VERSION 5.8 ;
BUSBITCHARS "[]" ;
DIVIDERCHAR "/" ;

PROPERTYDEFINITIONS
  MACRO CatenaDesignType STRING ;
  MACRO oaTaper STRING ;
END PROPERTYDEFINITIONS

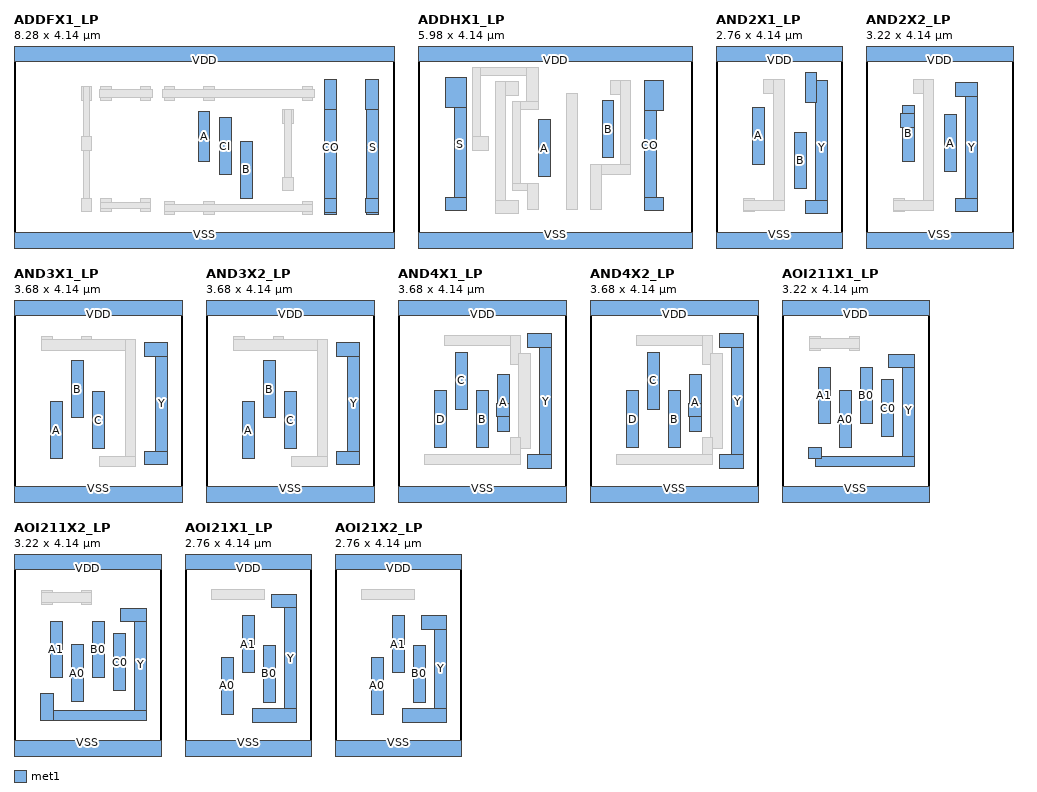
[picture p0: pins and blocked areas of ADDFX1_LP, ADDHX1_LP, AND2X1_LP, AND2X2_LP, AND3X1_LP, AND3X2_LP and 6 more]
MACRO ADDFX1_LP
  CLASS CORE ;
  ORIGIN 0 0 ;
  FOREIGN ADDFX1_LP 0 0 ;
  SIZE 8.28 BY 4.14 ;
  SYMMETRY X Y ;
  SITE CoreSite ;
  PIN A
    DIRECTION INPUT ;
    USE SIGNAL ;
    PORT
      LAYER met1 ;
        RECT 4.01 1.745 4.27 2.85 ;
    END
  END A
  PIN B
    DIRECTION INPUT ;
    USE SIGNAL ;
    PORT
      LAYER met1 ;
        RECT 4.93 0.955 5.19 2.195 ;
    END
  END B
  PIN CI
    DIRECTION INPUT ;
    USE SIGNAL ;
    PORT
      LAYER met1 ;
        RECT 4.47 1.47 4.73 2.71 ;
    END
  END CI
  PIN CO
    DIRECTION OUTPUT ;
    USE SIGNAL ;
    PORT
      LAYER met1 ;
        RECT 6.77 2.88 7.035 3.53 ;
        RECT 6.77 0.65 7.035 0.94 ;
        RECT 6.77 0.61 7.03 3.53 ;
    END
  END CO
  PIN S
    DIRECTION OUTPUT ;
    USE SIGNAL ;
    PORT
      LAYER met1 ;
        RECT 7.665 2.88 7.95 3.53 ;
        RECT 7.69 0.61 7.95 3.53 ;
        RECT 7.665 0.65 7.95 0.94 ;
    END
  END S
  PIN VDD
    DIRECTION INPUT ;
    USE POWER ;
    SHAPE ABUTMENT ;
    NETEXPR "VDD VDD!" ;
    PORT
      LAYER met1 ;
        RECT 0 3.94 8.28 4.34 ;
    END
  END VDD
  PIN VSS
    DIRECTION INPUT ;
    USE GROUND ;
    SHAPE ABUTMENT ;
    NETEXPR "VSS VSS!" ;
    PORT
      LAYER met1 ;
        RECT 0 -0.2 8.28 0.2 ;
    END
  END VSS
  OBS
    LAYER met1 ;
      RECT 6.285 3.09 6.515 3.38 ;
      RECT 4.135 3.09 4.365 3.38 ;
      RECT 3.275 3.09 3.505 3.38 ;
      RECT 3.245 3.15 6.545 3.32 ;
      RECT 6.285 0.6 6.515 0.89 ;
      RECT 4.135 0.6 4.365 0.89 ;
      RECT 3.275 0.6 3.505 0.89 ;
      RECT 3.275 0.675 6.515 0.815 ;
      RECT 5.855 2.59 6.085 2.88 ;
      RECT 5.9 1.125 6.04 2.88 ;
      RECT 5.855 1.125 6.085 1.415 ;
      RECT 2.755 3.09 2.985 3.38 ;
      RECT 1.895 3.09 2.125 3.38 ;
      RECT 1.865 3.15 3.015 3.32 ;
      RECT 2.755 0.655 2.985 0.945 ;
      RECT 1.895 0.655 2.125 0.945 ;
      RECT 1.895 0.73 2.985 0.87 ;
      RECT 1.465 3.09 1.695 3.38 ;
      RECT 1.51 0.655 1.65 3.38 ;
      RECT 1.465 2 1.695 2.29 ;
      RECT 1.465 0.655 1.695 0.945 ;
  END
  PROPERTY CatenaDesignType "deviceLevel" ;
END ADDFX1_LP

MACRO ADDHX1_LP
  CLASS CORE ;
  ORIGIN 0 0 ;
  FOREIGN ADDHX1_LP 0 0 ;
  SIZE 5.98 BY 4.14 ;
  SYMMETRY X Y ;
  SITE CoreSite ;
  PIN A
    DIRECTION INPUT ;
    USE SIGNAL ;
    PORT
      LAYER met1 ;
        RECT 2.63 1.425 2.89 2.665 ;
    END
  END A
  PIN B
    DIRECTION INPUT ;
    USE SIGNAL ;
    PORT
      LAYER met1 ;
        RECT 4.01 1.84 4.27 3.08 ;
    END
  END B
  PIN CO
    DIRECTION OUTPUT ;
    USE SIGNAL ;
    PORT
      LAYER met1 ;
        RECT 4.93 2.875 5.345 3.525 ;
        RECT 4.93 0.68 5.345 0.97 ;
        RECT 4.93 0.68 5.19 3.525 ;
    END
  END CO
  PIN S
    DIRECTION OUTPUT ;
    USE SIGNAL ;
    PORT
      LAYER met1 ;
        RECT 0.605 2.925 1.05 3.575 ;
        RECT 0.79 0.68 1.05 3.575 ;
        RECT 0.605 0.68 1.05 0.97 ;
    END
  END S
  PIN VDD
    DIRECTION INPUT ;
    USE POWER ;
    SHAPE ABUTMENT ;
    NETEXPR "VDD VDD!" ;
    PORT
      LAYER met1 ;
        RECT 0 3.94 5.98 4.34 ;
    END
  END VDD
  PIN VSS
    DIRECTION INPUT ;
    USE GROUND ;
    SHAPE ABUTMENT ;
    NETEXPR "VSS VSS!" ;
    PORT
      LAYER met1 ;
        RECT 0 -0.2 5.98 0.2 ;
    END
  END VSS
  OBS
    LAYER met1 ;
      RECT 4.195 3.22 4.64 3.51 ;
      RECT 4.41 1.46 4.64 3.51 ;
      RECT 3.765 1.46 4.64 1.69 ;
      RECT 3.765 0.705 3.995 1.69 ;
      RECT 1.19 3.63 2.615 3.8 ;
      RECT 2.355 2.89 2.615 3.8 ;
      RECT 1.19 2 1.36 3.8 ;
      RECT 2.065 2.89 2.615 3.06 ;
      RECT 2.065 1.115 2.235 3.06 ;
      RECT 1.19 2 1.54 2.29 ;
      RECT 2.065 1.115 2.615 1.285 ;
      RECT 2.385 0.705 2.615 1.285 ;
      RECT 1.68 3.2 2.185 3.49 ;
      RECT 1.68 0.615 1.91 3.49 ;
      RECT 1.68 0.615 2.185 0.905 ;
      RECT 3.245 0.705 3.475 3.235 ;
  END
  PROPERTY CatenaDesignType "deviceLevel" ;
END ADDHX1_LP

MACRO AND2X1_LP
  CLASS CORE ;
  ORIGIN 0 0 ;
  FOREIGN AND2X1_LP 0 0 ;
  SIZE 2.76 BY 4.14 ;
  SYMMETRY X Y ;
  SITE CoreSite ;
  PIN A
    DIRECTION INPUT ;
    USE SIGNAL ;
    PORT
      LAYER met1 ;
        RECT 0.79 1.695 1.05 2.935 ;
    END
  END A
  PIN B
    DIRECTION INPUT ;
    USE SIGNAL ;
    PORT
      LAYER met1 ;
        RECT 1.71 1.155 1.97 2.395 ;
    END
  END B
  PIN VDD
    DIRECTION INPUT ;
    USE POWER ;
    SHAPE ABUTMENT ;
    NETEXPR "VDD VDD!" ;
    PORT
      LAYER met1 ;
        RECT 0 3.94 2.76 4.34 ;
    END
  END VDD
  PIN VSS
    DIRECTION INPUT ;
    USE GROUND ;
    SHAPE ABUTMENT ;
    NETEXPR "VSS VSS!" ;
    PORT
      LAYER met1 ;
        RECT 0 -0.2 2.76 0.2 ;
    END
  END VSS
  PIN Y
    DIRECTION OUTPUT ;
    USE SIGNAL ;
    PORT
      LAYER met1 ;
        RECT 2.17 0.625 2.43 3.51 ;
        RECT 1.955 3.05 2.185 3.7 ;
        RECT 1.955 0.625 2.43 0.915 ;
    END
  END Y
  OBS
    LAYER met1 ;
      RECT 1.035 3.24 1.49 3.53 ;
      RECT 1.26 0.685 1.49 3.53 ;
      RECT 0.605 0.655 0.835 0.945 ;
      RECT 0.605 0.685 1.49 0.915 ;
  END
  PROPERTY CatenaDesignType "deviceLevel" ;
END AND2X1_LP

MACRO AND2X2_LP
  CLASS CORE ;
  ORIGIN 0 0 ;
  FOREIGN AND2X2_LP 0 0 ;
  SIZE 3.22 BY 4.14 ;
  SYMMETRY X Y ;
  SITE CoreSite ;
  PIN A
    DIRECTION INPUT ;
    USE SIGNAL ;
    PORT
      LAYER met1 ;
        RECT 1.71 1.535 1.97 2.775 ;
    END
  END A
  PIN B
    DIRECTION INPUT ;
    USE SIGNAL ;
    PORT
      LAYER met1 ;
        RECT 0.79 1.745 1.05 2.985 ;
        RECT 0.745 2.505 1.05 2.795 ;
    END
  END B
  PIN VDD
    DIRECTION INPUT ;
    USE POWER ;
    SHAPE ABUTMENT ;
    NETEXPR "VDD VDD!" ;
    PORT
      LAYER met1 ;
        RECT 0 3.94 3.22 4.34 ;
    END
  END VDD
  PIN VSS
    DIRECTION INPUT ;
    USE GROUND ;
    SHAPE ABUTMENT ;
    NETEXPR "VSS VSS!" ;
    PORT
      LAYER met1 ;
        RECT 0 -0.2 3.22 0.2 ;
    END
  END VSS
  PIN Y
    DIRECTION OUTPUT ;
    USE SIGNAL ;
    PORT
      LAYER met1 ;
        RECT 1.955 3.18 2.43 3.47 ;
        RECT 2.17 0.655 2.43 3.47 ;
        RECT 1.955 0.655 2.43 0.945 ;
    END
  END Y
  OBS
    LAYER met1 ;
      RECT 1.035 3.24 1.48 3.53 ;
      RECT 1.25 0.685 1.48 3.53 ;
      RECT 0.605 0.655 0.835 0.945 ;
      RECT 0.605 0.685 1.48 0.915 ;
  END
  PROPERTY CatenaDesignType "deviceLevel" ;
END AND2X2_LP

MACRO AND3X1_LP
  CLASS CORE ;
  ORIGIN 0 0 ;
  FOREIGN AND3X1_LP 0 0 ;
  SIZE 3.68 BY 4.14 ;
  SYMMETRY X Y ;
  SITE CoreSite ;
  PIN A
    DIRECTION INPUT ;
    USE SIGNAL ;
    PORT
      LAYER met1 ;
        RECT 0.79 0.815 1.05 2.055 ;
    END
  END A
  PIN B
    DIRECTION INPUT ;
    USE SIGNAL ;
    PORT
      LAYER met1 ;
        RECT 1.25 1.705 1.51 2.945 ;
    END
  END B
  PIN C
    DIRECTION INPUT ;
    USE SIGNAL ;
    PORT
      LAYER met1 ;
        RECT 1.71 1.03 1.97 2.27 ;
    END
  END C
  PIN VDD
    DIRECTION INPUT ;
    USE POWER ;
    SHAPE ABUTMENT ;
    NETEXPR "VDD VDD!" ;
    PORT
      LAYER met1 ;
        RECT 0 3.94 3.68 4.34 ;
    END
  END VDD
  PIN VSS
    DIRECTION INPUT ;
    USE GROUND ;
    SHAPE ABUTMENT ;
    NETEXPR "VSS VSS!" ;
    PORT
      LAYER met1 ;
        RECT 0 -0.2 3.68 0.2 ;
    END
  END VSS
  PIN Y
    DIRECTION OUTPUT ;
    USE SIGNAL ;
    PORT
      LAYER met1 ;
        RECT 2.845 3.045 3.35 3.335 ;
        RECT 3.09 0.69 3.35 3.335 ;
        RECT 2.845 0.69 3.35 0.98 ;
    END
  END Y
  OBS
    LAYER met1 ;
      RECT 1.465 3.175 1.695 3.465 ;
      RECT 0.605 3.175 0.835 3.465 ;
      RECT 0.605 3.175 2.65 3.405 ;
      RECT 2.42 0.64 2.65 3.405 ;
      RECT 1.865 0.64 2.65 0.87 ;
  END
  PROPERTY CatenaDesignType "deviceLevel" ;
END AND3X1_LP

MACRO AND3X2_LP
  CLASS CORE ;
  ORIGIN 0 0 ;
  FOREIGN AND3X2_LP 0 0 ;
  SIZE 3.68 BY 4.14 ;
  SYMMETRY X Y ;
  SITE CoreSite ;
  PIN A
    DIRECTION INPUT ;
    USE SIGNAL ;
    PORT
      LAYER met1 ;
        RECT 0.79 0.815 1.05 2.055 ;
    END
  END A
  PIN B
    DIRECTION INPUT ;
    USE SIGNAL ;
    PORT
      LAYER met1 ;
        RECT 1.25 1.705 1.51 2.945 ;
    END
  END B
  PIN C
    DIRECTION INPUT ;
    USE SIGNAL ;
    PORT
      LAYER met1 ;
        RECT 1.71 1.03 1.97 2.27 ;
    END
  END C
  PIN VDD
    DIRECTION INPUT ;
    USE POWER ;
    SHAPE ABUTMENT ;
    NETEXPR "VDD VDD!" ;
    PORT
      LAYER met1 ;
        RECT 0 3.94 3.68 4.34 ;
    END
  END VDD
  PIN VSS
    DIRECTION INPUT ;
    USE GROUND ;
    SHAPE ABUTMENT ;
    NETEXPR "VSS VSS!" ;
    PORT
      LAYER met1 ;
        RECT 0 -0.2 3.68 0.2 ;
    END
  END VSS
  PIN Y
    DIRECTION OUTPUT ;
    USE SIGNAL ;
    PORT
      LAYER met1 ;
        RECT 2.845 3.045 3.35 3.335 ;
        RECT 3.09 0.69 3.35 3.335 ;
        RECT 2.845 0.69 3.35 0.98 ;
    END
  END Y
  OBS
    LAYER met1 ;
      RECT 1.465 3.175 1.695 3.465 ;
      RECT 0.605 3.175 0.835 3.465 ;
      RECT 0.605 3.175 2.65 3.405 ;
      RECT 2.42 0.64 2.65 3.405 ;
      RECT 1.865 0.64 2.65 0.87 ;
  END
  PROPERTY CatenaDesignType "deviceLevel" ;
END AND3X2_LP

MACRO AND4X1_LP
  CLASS CORE ;
  ORIGIN 0 0 ;
  FOREIGN AND4X1_LP 0 0 ;
  SIZE 3.68 BY 4.14 ;
  SYMMETRY X Y ;
  SITE CoreSite ;
  PIN A
    DIRECTION INPUT ;
    USE SIGNAL ;
    PORT
      LAYER met1 ;
        RECT 2.17 1.41 2.43 2.65 ;
        RECT 2.14 1.73 2.43 2.02 ;
    END
  END A
  PIN B
    DIRECTION INPUT ;
    USE SIGNAL ;
    PORT
      LAYER met1 ;
        RECT 1.71 1.055 1.97 2.295 ;
    END
  END B
  PIN C
    DIRECTION INPUT ;
    USE SIGNAL ;
    PORT
      LAYER met1 ;
        RECT 1.25 1.89 1.51 3.13 ;
    END
  END C
  PIN D
    DIRECTION INPUT ;
    USE SIGNAL ;
    PORT
      LAYER met1 ;
        RECT 0.79 1.055 1.05 2.295 ;
    END
  END D
  PIN VDD
    DIRECTION INPUT ;
    USE POWER ;
    SHAPE ABUTMENT ;
    NETEXPR "VDD VDD!" ;
    PORT
      LAYER met1 ;
        RECT 0 3.94 3.68 4.34 ;
    END
  END VDD
  PIN VSS
    DIRECTION INPUT ;
    USE GROUND ;
    SHAPE ABUTMENT ;
    NETEXPR "VSS VSS!" ;
    PORT
      LAYER met1 ;
        RECT 0 -0.2 3.68 0.2 ;
    END
  END VSS
  PIN Y
    DIRECTION OUTPUT ;
    USE SIGNAL ;
    PORT
      LAYER met1 ;
        RECT 2.815 3.24 3.35 3.53 ;
        RECT 3.09 0.61 3.35 3.53 ;
        RECT 2.815 0.61 3.35 0.9 ;
    END
  END Y
  OBS
    LAYER met1 ;
      RECT 1.005 3.27 2.675 3.5 ;
      RECT 2.445 2.87 2.675 3.5 ;
      RECT 2.63 1.04 2.89 3.1 ;
      RECT 2.445 0.685 2.675 1.27 ;
      RECT 0.575 0.685 2.675 0.915 ;
  END
  PROPERTY CatenaDesignType "deviceLevel" ;
END AND4X1_LP

MACRO AND4X2_LP
  CLASS CORE ;
  ORIGIN 0 0 ;
  FOREIGN AND4X2_LP 0 0 ;
  SIZE 3.68 BY 4.14 ;
  SYMMETRY X Y ;
  SITE CoreSite ;
  PIN A
    DIRECTION INPUT ;
    USE SIGNAL ;
    PORT
      LAYER met1 ;
        RECT 2.17 1.41 2.43 2.65 ;
        RECT 2.14 1.73 2.43 2.02 ;
    END
  END A
  PIN B
    DIRECTION INPUT ;
    USE SIGNAL ;
    PORT
      LAYER met1 ;
        RECT 1.71 1.055 1.97 2.295 ;
    END
  END B
  PIN C
    DIRECTION INPUT ;
    USE SIGNAL ;
    PORT
      LAYER met1 ;
        RECT 1.25 1.89 1.51 3.13 ;
    END
  END C
  PIN D
    DIRECTION INPUT ;
    USE SIGNAL ;
    PORT
      LAYER met1 ;
        RECT 0.79 1.055 1.05 2.295 ;
    END
  END D
  PIN VDD
    DIRECTION INPUT ;
    USE POWER ;
    SHAPE ABUTMENT ;
    NETEXPR "VDD VDD!" ;
    PORT
      LAYER met1 ;
        RECT 0 3.94 3.68 4.34 ;
    END
  END VDD
  PIN VSS
    DIRECTION INPUT ;
    USE GROUND ;
    SHAPE ABUTMENT ;
    NETEXPR "VSS VSS!" ;
    PORT
      LAYER met1 ;
        RECT 0 -0.2 3.68 0.2 ;
    END
  END VSS
  PIN Y
    DIRECTION OUTPUT ;
    USE SIGNAL ;
    PORT
      LAYER met1 ;
        RECT 2.815 3.24 3.35 3.53 ;
        RECT 3.09 0.61 3.35 3.53 ;
        RECT 2.815 0.61 3.35 0.9 ;
    END
  END Y
  OBS
    LAYER met1 ;
      RECT 1.005 3.27 2.675 3.5 ;
      RECT 2.445 2.87 2.675 3.5 ;
      RECT 2.63 1.04 2.89 3.1 ;
      RECT 2.445 0.685 2.675 1.27 ;
      RECT 0.575 0.685 2.675 0.915 ;
  END
  PROPERTY CatenaDesignType "deviceLevel" ;
END AND4X2_LP

MACRO AOI211X1_LP
  CLASS CORE ;
  ORIGIN 0 0 ;
  FOREIGN AOI211X1_LP 0 0 ;
  SIZE 3.22 BY 4.14 ;
  SYMMETRY X Y ;
  SITE CoreSite ;
  PIN A0
    DIRECTION INPUT ;
    USE SIGNAL ;
    PORT
      LAYER met1 ;
        RECT 1.25 1.05 1.51 2.29 ;
    END
  END A0
  PIN A1
    DIRECTION INPUT ;
    USE SIGNAL ;
    PORT
      LAYER met1 ;
        RECT 0.79 1.57 1.05 2.81 ;
    END
  END A1
  PIN B0
    DIRECTION INPUT ;
    USE SIGNAL ;
    PORT
      LAYER met1 ;
        RECT 1.71 1.57 1.97 2.81 ;
    END
  END B0
  PIN C0
    DIRECTION INPUT ;
    USE SIGNAL ;
    PORT
      LAYER met1 ;
        RECT 2.17 1.29 2.43 2.53 ;
    END
  END C0
  PIN VDD
    DIRECTION INPUT ;
    USE POWER ;
    SHAPE ABUTMENT ;
    NETEXPR "VDD VDD!" ;
    PORT
      LAYER met1 ;
        RECT 0 3.94 3.22 4.34 ;
    END
  END VDD
  PIN VSS
    DIRECTION INPUT ;
    USE GROUND ;
    SHAPE ABUTMENT ;
    NETEXPR "VSS VSS!" ;
    PORT
      LAYER met1 ;
        RECT 0 -0.2 3.22 0.2 ;
    END
  END VSS
  PIN Y
    DIRECTION OUTPUT ;
    USE SIGNAL ;
    PORT
      LAYER met1 ;
        RECT 2.33 2.79 2.89 3.08 ;
        RECT 2.63 0.64 2.89 3.08 ;
        RECT 0.72 0.64 2.89 0.87 ;
        RECT 0.575 0.82 0.865 1.05 ;
    END
  END Y
  OBS
    LAYER met1 ;
      RECT 1.465 3.18 1.695 3.47 ;
      RECT 0.605 3.18 0.835 3.47 ;
      RECT 0.605 3.21 1.695 3.44 ;
  END
  PROPERTY CatenaDesignType "deviceLevel" ;
END AOI211X1_LP

MACRO AOI211X2_LP
  CLASS CORE ;
  ORIGIN 0 0 ;
  FOREIGN AOI211X2_LP 0 0 ;
  SIZE 3.22 BY 4.14 ;
  SYMMETRY X Y ;
  SITE CoreSite ;
  PIN A0
    DIRECTION INPUT ;
    USE SIGNAL ;
    PORT
      LAYER met1 ;
        RECT 1.25 1.05 1.51 2.29 ;
    END
  END A0
  PIN A1
    DIRECTION INPUT ;
    USE SIGNAL ;
    PORT
      LAYER met1 ;
        RECT 0.79 1.57 1.05 2.81 ;
    END
  END A1
  PIN B0
    DIRECTION INPUT ;
    USE SIGNAL ;
    PORT
      LAYER met1 ;
        RECT 1.71 1.57 1.97 2.81 ;
    END
  END B0
  PIN C0
    DIRECTION INPUT ;
    USE SIGNAL ;
    PORT
      LAYER met1 ;
        RECT 2.17 1.29 2.43 2.53 ;
    END
  END C0
  PIN VDD
    DIRECTION INPUT ;
    USE POWER ;
    SHAPE ABUTMENT ;
    NETEXPR "VDD VDD!" ;
    PORT
      LAYER met1 ;
        RECT 0 3.94 3.22 4.34 ;
    END
  END VDD
  PIN VSS
    DIRECTION INPUT ;
    USE GROUND ;
    SHAPE ABUTMENT ;
    NETEXPR "VSS VSS!" ;
    PORT
      LAYER met1 ;
        RECT 0 -0.2 3.22 0.2 ;
    END
  END VSS
  PIN Y
    DIRECTION OUTPUT ;
    USE SIGNAL ;
    PORT
      LAYER met1 ;
        RECT 2.33 2.79 2.89 3.08 ;
        RECT 2.63 0.64 2.89 3.08 ;
        RECT 0.575 0.64 2.89 0.87 ;
        RECT 0.575 0.64 0.865 1.23 ;
    END
  END Y
  OBS
    LAYER met1 ;
      RECT 1.465 3.18 1.695 3.47 ;
      RECT 0.605 3.18 0.835 3.47 ;
      RECT 0.605 3.21 1.695 3.44 ;
  END
  PROPERTY CatenaDesignType "deviceLevel" ;
END AOI211X2_LP

MACRO AOI21X1_LP
  CLASS CORE ;
  ORIGIN 0 0 ;
  FOREIGN AOI21X1_LP 0 0 ;
  SIZE 2.76 BY 4.14 ;
  SYMMETRY X Y ;
  SITE CoreSite ;
  PIN A0
    DIRECTION INPUT ;
    USE SIGNAL ;
    PORT
      LAYER met1 ;
        RECT 0.79 0.775 1.05 2.015 ;
    END
  END A0
  PIN A1
    DIRECTION INPUT ;
    USE SIGNAL ;
    PORT
      LAYER met1 ;
        RECT 1.25 1.685 1.51 2.925 ;
    END
  END A1
  PIN B0
    DIRECTION INPUT ;
    USE SIGNAL ;
    PORT
      LAYER met1 ;
        RECT 1.71 1.04 1.97 2.28 ;
    END
  END B0
  PIN VDD
    DIRECTION INPUT ;
    USE POWER ;
    SHAPE ABUTMENT ;
    NETEXPR "VDD VDD!" ;
    PORT
      LAYER met1 ;
        RECT 0 3.94 2.76 4.34 ;
    END
  END VDD
  PIN VSS
    DIRECTION INPUT ;
    USE GROUND ;
    SHAPE ABUTMENT ;
    NETEXPR "VSS VSS!" ;
    PORT
      LAYER met1 ;
        RECT 0 -0.2 2.76 0.2 ;
    END
  END VSS
  PIN Y
    DIRECTION OUTPUT ;
    USE SIGNAL ;
    PORT
      LAYER met1 ;
        RECT 1.895 3.095 2.43 3.385 ;
        RECT 2.17 0.61 2.43 3.385 ;
        RECT 1.465 0.61 2.43 0.9 ;
    END
  END Y
  OBS
    LAYER met1 ;
      RECT 0.575 3.27 1.725 3.5 ;
  END
  PROPERTY CatenaDesignType "deviceLevel" ;
END AOI21X1_LP

MACRO AOI21X2_LP
  CLASS CORE ;
  ORIGIN 0 0 ;
  FOREIGN AOI21X2_LP 0 0 ;
  SIZE 2.76 BY 4.14 ;
  SYMMETRY X Y ;
  SITE CoreSite ;
  PIN A0
    DIRECTION INPUT ;
    USE SIGNAL ;
    PORT
      LAYER met1 ;
        RECT 0.79 0.775 1.05 2.015 ;
    END
  END A0
  PIN A1
    DIRECTION INPUT ;
    USE SIGNAL ;
    PORT
      LAYER met1 ;
        RECT 1.25 1.685 1.51 2.925 ;
    END
  END A1
  PIN B0
    DIRECTION INPUT ;
    USE SIGNAL ;
    PORT
      LAYER met1 ;
        RECT 1.71 1.04 1.97 2.28 ;
    END
  END B0
  PIN VDD
    DIRECTION INPUT ;
    USE POWER ;
    SHAPE ABUTMENT ;
    NETEXPR "VDD VDD!" ;
    PORT
      LAYER met1 ;
        RECT 0 3.94 2.76 4.34 ;
    END
  END VDD
  PIN VSS
    DIRECTION INPUT ;
    USE GROUND ;
    SHAPE ABUTMENT ;
    NETEXPR "VSS VSS!" ;
    PORT
      LAYER met1 ;
        RECT 0 -0.2 2.76 0.2 ;
    END
  END VSS
  PIN Y
    DIRECTION OUTPUT ;
    USE SIGNAL ;
    PORT
      LAYER met1 ;
        RECT 1.895 2.635 2.43 2.925 ;
        RECT 2.17 0.61 2.43 2.925 ;
        RECT 1.465 0.61 2.43 0.9 ;
    END
  END Y
  OBS
    LAYER met1 ;
      RECT 0.575 3.27 1.725 3.5 ;
  END
  PROPERTY CatenaDesignType "deviceLevel" ;
END AOI21X2_LP

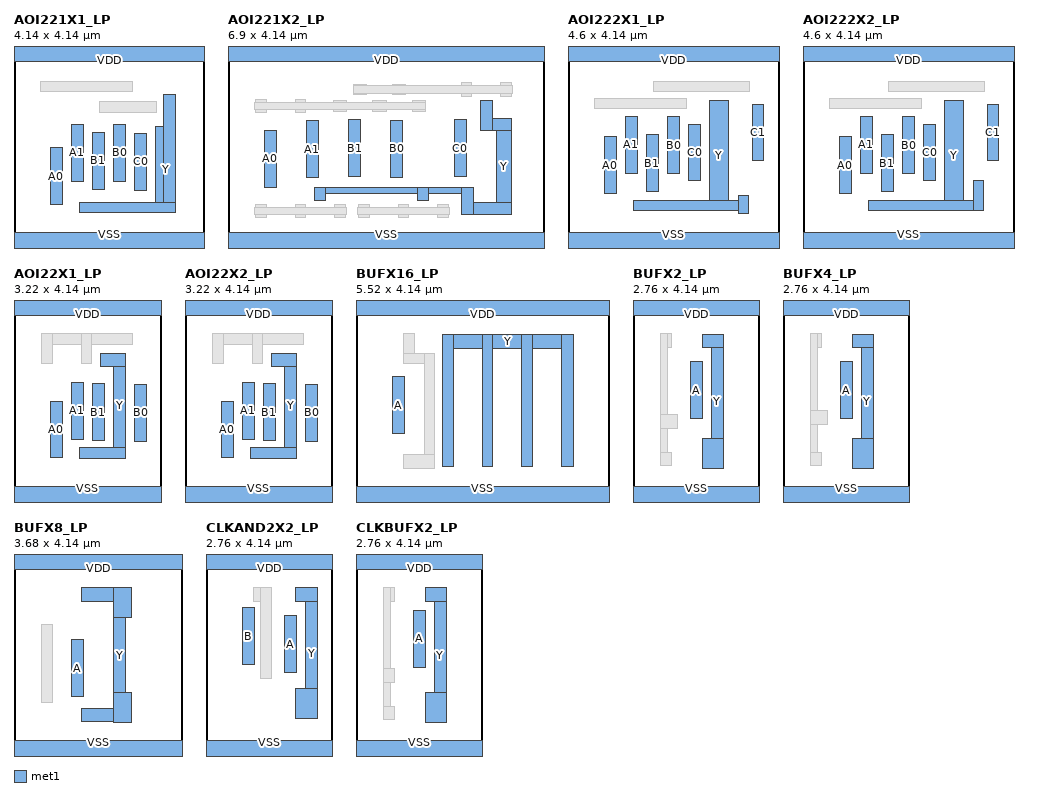
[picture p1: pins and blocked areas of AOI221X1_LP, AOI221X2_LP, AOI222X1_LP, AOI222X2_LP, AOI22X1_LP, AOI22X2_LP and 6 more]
MACRO AOI221X1_LP
  CLASS CORE ;
  ORIGIN 0 0 ;
  FOREIGN AOI221X1_LP 0 0 ;
  SIZE 4.14 BY 4.14 ;
  SYMMETRY X Y ;
  SITE CoreSite ;
  PIN A0
    DIRECTION INPUT ;
    USE SIGNAL ;
    PORT
      LAYER met1 ;
        RECT 0.79 0.81 1.05 2.05 ;
    END
  END A0
  PIN A1
    DIRECTION INPUT ;
    USE SIGNAL ;
    PORT
      LAYER met1 ;
        RECT 1.25 1.325 1.51 2.565 ;
    END
  END A1
  PIN B0
    DIRECTION INPUT ;
    USE SIGNAL ;
    PORT
      LAYER met1 ;
        RECT 2.17 1.325 2.43 2.565 ;
    END
  END B0
  PIN B1
    DIRECTION INPUT ;
    USE SIGNAL ;
    PORT
      LAYER met1 ;
        RECT 1.71 1.15 1.97 2.39 ;
    END
  END B1
  PIN C0
    DIRECTION INPUT ;
    USE SIGNAL ;
    PORT
      LAYER met1 ;
        RECT 2.63 1.13 2.89 2.37 ;
    END
  END C0
  PIN VDD
    DIRECTION INPUT ;
    USE POWER ;
    SHAPE ABUTMENT ;
    NETEXPR "VDD VDD!" ;
    PORT
      LAYER met1 ;
        RECT 0 3.94 4.14 4.34 ;
    END
  END VDD
  PIN VSS
    DIRECTION INPUT ;
    USE GROUND ;
    SHAPE ABUTMENT ;
    NETEXPR "VSS VSS!" ;
    PORT
      LAYER met1 ;
        RECT 0 -0.2 4.14 0.2 ;
    END
  END VSS
  PIN Y
    DIRECTION OUTPUT ;
    USE SIGNAL ;
    PORT
      LAYER met1 ;
        RECT 3.26 0.64 3.52 3.215 ;
        RECT 3.09 0.64 3.52 2.525 ;
        RECT 1.435 0.64 3.52 0.87 ;
    END
  END Y
  OBS
    LAYER met1 ;
      RECT 1.865 2.83 3.105 3.06 ;
      RECT 0.575 3.27 2.585 3.5 ;
  END
  PROPERTY CatenaDesignType "deviceLevel" ;
END AOI221X1_LP

MACRO AOI221X2_LP
  CLASS CORE ;
  ORIGIN 0 0 ;
  FOREIGN AOI221X2_LP 0 0 ;
  SIZE 6.9 BY 4.14 ;
  SYMMETRY X Y ;
  SITE CoreSite ;
  PIN A0
    DIRECTION INPUT ;
    USE SIGNAL ;
    PORT
      LAYER met1 ;
        RECT 0.79 1.19 1.05 2.43 ;
    END
  END A0
  PIN A1
    DIRECTION INPUT ;
    USE SIGNAL ;
    PORT
      LAYER met1 ;
        RECT 1.71 1.4 1.97 2.64 ;
    END
  END A1
  PIN B0
    DIRECTION INPUT ;
    USE SIGNAL ;
    PORT
      LAYER met1 ;
        RECT 3.55 1.415 3.81 2.655 ;
    END
  END B0
  PIN B1
    DIRECTION INPUT ;
    USE SIGNAL ;
    PORT
      LAYER met1 ;
        RECT 2.63 1.42 2.89 2.66 ;
    END
  END B1
  PIN C0
    DIRECTION INPUT ;
    USE SIGNAL ;
    PORT
      LAYER met1 ;
        RECT 4.93 1.425 5.19 2.665 ;
    END
  END C0
  PIN VDD
    DIRECTION INPUT ;
    USE POWER ;
    SHAPE ABUTMENT ;
    NETEXPR "VDD VDD!" ;
    PORT
      LAYER met1 ;
        RECT 0 3.94 6.9 4.34 ;
    END
  END VDD
  PIN VSS
    DIRECTION INPUT ;
    USE GROUND ;
    SHAPE ABUTMENT ;
    NETEXPR "VSS VSS!" ;
    PORT
      LAYER met1 ;
        RECT 0 -0.2 6.9 0.2 ;
    END
  END VSS
  PIN Y
    DIRECTION OUTPUT ;
    USE SIGNAL ;
    PORT
      LAYER met1 ;
        RECT 5.51 2.43 6.175 2.69 ;
        RECT 5.85 0.59 6.175 2.69 ;
        RECT 5.08 0.59 6.175 0.85 ;
        RECT 5.51 2.43 5.77 3.08 ;
        RECT 1.895 1.05 5.34 1.19 ;
        RECT 5.08 0.59 5.34 1.19 ;
        RECT 4.135 0.9 4.365 1.19 ;
        RECT 1.895 0.9 2.125 1.19 ;
    END
  END Y
  OBS
    LAYER met1 ;
      RECT 5.945 3.18 6.175 3.47 ;
      RECT 5.085 3.18 5.315 3.47 ;
      RECT 3.585 3.21 3.875 3.44 ;
      RECT 2.725 3.21 3.015 3.44 ;
      RECT 2.725 3.24 6.205 3.41 ;
      RECT 4.565 0.53 4.795 0.82 ;
      RECT 3.705 0.53 3.935 0.82 ;
      RECT 2.845 0.53 3.075 0.82 ;
      RECT 2.815 0.59 4.825 0.76 ;
      RECT 1.465 2.82 1.695 3.11 ;
      RECT 0.605 2.82 0.835 3.11 ;
      RECT 4.015 2.85 4.305 3.08 ;
      RECT 3.155 2.85 3.445 3.08 ;
      RECT 2.295 2.85 2.585 3.08 ;
      RECT 0.575 2.88 4.305 3.05 ;
      RECT 2.325 0.53 2.555 0.82 ;
      RECT 1.465 0.53 1.695 0.82 ;
      RECT 0.605 0.53 0.835 0.82 ;
      RECT 0.575 0.59 2.585 0.76 ;
  END
  PROPERTY CatenaDesignType "deviceLevel" ;
END AOI221X2_LP

MACRO AOI222X1_LP
  CLASS CORE ;
  ORIGIN 0 0 ;
  FOREIGN AOI222X1_LP 0 0 ;
  SIZE 4.6 BY 4.14 ;
  SYMMETRY X Y ;
  SITE CoreSite ;
  PIN A0
    DIRECTION INPUT ;
    USE SIGNAL ;
    PORT
      LAYER met1 ;
        RECT 0.79 1.05 1.05 2.29 ;
    END
  END A0
  PIN A1
    DIRECTION INPUT ;
    USE SIGNAL ;
    PORT
      LAYER met1 ;
        RECT 1.25 1.495 1.51 2.735 ;
    END
  END A1
  PIN B0
    DIRECTION INPUT ;
    USE SIGNAL ;
    PORT
      LAYER met1 ;
        RECT 2.17 1.49 2.43 2.73 ;
    END
  END B0
  PIN B1
    DIRECTION INPUT ;
    USE SIGNAL ;
    PORT
      LAYER met1 ;
        RECT 1.71 1.1 1.97 2.34 ;
    END
  END B1
  PIN C0
    DIRECTION INPUT ;
    USE SIGNAL ;
    PORT
      LAYER met1 ;
        RECT 2.63 1.33 2.89 2.57 ;
    END
  END C0
  PIN C1
    DIRECTION INPUT ;
    USE SIGNAL ;
    PORT
      LAYER met1 ;
        RECT 4.01 1.765 4.27 3.005 ;
    END
  END C1
  PIN VDD
    DIRECTION INPUT ;
    USE POWER ;
    SHAPE ABUTMENT ;
    NETEXPR "VDD VDD!" ;
    PORT
      LAYER met1 ;
        RECT 0 3.94 4.6 4.34 ;
    END
  END VDD
  PIN VSS
    DIRECTION INPUT ;
    USE GROUND ;
    SHAPE ABUTMENT ;
    NETEXPR "VSS VSS!" ;
    PORT
      LAYER met1 ;
        RECT 0 -0.2 4.6 0.2 ;
    END
  END VSS
  PIN Y
    DIRECTION OUTPUT ;
    USE SIGNAL ;
    PORT
      LAYER met1 ;
        RECT 3.705 0.62 3.935 1.005 ;
        RECT 1.435 0.68 3.935 0.91 ;
        RECT 3.09 0.68 3.505 3.09 ;
    END
  END Y
  OBS
    LAYER met1 ;
      RECT 1.865 3.27 3.965 3.5 ;
      RECT 0.575 2.9 2.585 3.13 ;
  END
  PROPERTY CatenaDesignType "deviceLevel" ;
END AOI222X1_LP

MACRO AOI222X2_LP
  CLASS CORE ;
  ORIGIN 0 0 ;
  FOREIGN AOI222X2_LP 0 0 ;
  SIZE 4.6 BY 4.14 ;
  SYMMETRY X Y ;
  SITE CoreSite ;
  PIN A0
    DIRECTION INPUT ;
    USE SIGNAL ;
    PORT
      LAYER met1 ;
        RECT 0.79 1.05 1.05 2.29 ;
    END
  END A0
  PIN A1
    DIRECTION INPUT ;
    USE SIGNAL ;
    PORT
      LAYER met1 ;
        RECT 1.25 1.495 1.51 2.735 ;
    END
  END A1
  PIN B0
    DIRECTION INPUT ;
    USE SIGNAL ;
    PORT
      LAYER met1 ;
        RECT 2.17 1.49 2.43 2.73 ;
    END
  END B0
  PIN B1
    DIRECTION INPUT ;
    USE SIGNAL ;
    PORT
      LAYER met1 ;
        RECT 1.71 1.1 1.97 2.34 ;
    END
  END B1
  PIN C0
    DIRECTION INPUT ;
    USE SIGNAL ;
    PORT
      LAYER met1 ;
        RECT 2.63 1.33 2.89 2.57 ;
    END
  END C0
  PIN C1
    DIRECTION INPUT ;
    USE SIGNAL ;
    PORT
      LAYER met1 ;
        RECT 4.01 1.765 4.27 3.005 ;
    END
  END C1
  PIN VDD
    DIRECTION INPUT ;
    USE POWER ;
    SHAPE ABUTMENT ;
    NETEXPR "VDD VDD!" ;
    PORT
      LAYER met1 ;
        RECT 0 3.94 4.6 4.34 ;
    END
  END VDD
  PIN VSS
    DIRECTION INPUT ;
    USE GROUND ;
    SHAPE ABUTMENT ;
    NETEXPR "VSS VSS!" ;
    PORT
      LAYER met1 ;
        RECT 0 -0.2 4.6 0.2 ;
    END
  END VSS
  PIN Y
    DIRECTION OUTPUT ;
    USE SIGNAL ;
    PORT
      LAYER met1 ;
        RECT 3.705 0.68 3.935 1.33 ;
        RECT 1.435 0.68 3.935 0.91 ;
        RECT 3.09 0.68 3.505 3.09 ;
    END
  END Y
  OBS
    LAYER met1 ;
      RECT 1.865 3.27 3.965 3.5 ;
      RECT 0.575 2.9 2.585 3.13 ;
  END
  PROPERTY CatenaDesignType "deviceLevel" ;
END AOI222X2_LP

MACRO AOI22X1_LP
  CLASS CORE ;
  ORIGIN 0 0 ;
  FOREIGN AOI22X1_LP 0 0 ;
  SIZE 3.22 BY 4.14 ;
  SYMMETRY X Y ;
  SITE CoreSite ;
  PIN A0
    DIRECTION INPUT ;
    USE SIGNAL ;
    PORT
      LAYER met1 ;
        RECT 0.79 0.83 1.05 2.07 ;
    END
  END A0
  PIN A1
    DIRECTION INPUT ;
    USE SIGNAL ;
    PORT
      LAYER met1 ;
        RECT 1.25 1.24 1.51 2.48 ;
    END
  END A1
  PIN B0
    DIRECTION INPUT ;
    USE SIGNAL ;
    PORT
      LAYER met1 ;
        RECT 2.63 1.195 2.89 2.435 ;
    END
  END B0
  PIN B1
    DIRECTION INPUT ;
    USE SIGNAL ;
    PORT
      LAYER met1 ;
        RECT 1.71 1.205 1.97 2.445 ;
    END
  END B1
  PIN VDD
    DIRECTION INPUT ;
    USE POWER ;
    SHAPE ABUTMENT ;
    NETEXPR "VDD VDD!" ;
    PORT
      LAYER met1 ;
        RECT 0 3.94 3.22 4.34 ;
    END
  END VDD
  PIN VSS
    DIRECTION INPUT ;
    USE GROUND ;
    SHAPE ABUTMENT ;
    NETEXPR "VSS VSS!" ;
    PORT
      LAYER met1 ;
        RECT 0 -0.2 3.22 0.2 ;
    END
  END VSS
  PIN Y
    DIRECTION OUTPUT ;
    USE SIGNAL ;
    PORT
      LAYER met1 ;
        RECT 1.895 2.82 2.43 3.11 ;
        RECT 2.17 0.82 2.43 3.11 ;
        RECT 1.435 0.82 2.43 1.05 ;
    END
  END Y
  OBS
    LAYER met1 ;
      RECT 0.605 3.3 2.585 3.53 ;
      RECT 1.465 2.88 1.695 3.53 ;
      RECT 0.605 2.88 0.835 3.53 ;
  END
  PROPERTY CatenaDesignType "deviceLevel" ;
END AOI22X1_LP

MACRO AOI22X2_LP
  CLASS CORE ;
  ORIGIN 0 0 ;
  FOREIGN AOI22X2_LP 0 0 ;
  SIZE 3.22 BY 4.14 ;
  SYMMETRY X Y ;
  SITE CoreSite ;
  PIN A0
    DIRECTION INPUT ;
    USE SIGNAL ;
    PORT
      LAYER met1 ;
        RECT 0.79 0.83 1.05 2.07 ;
    END
  END A0
  PIN A1
    DIRECTION INPUT ;
    USE SIGNAL ;
    PORT
      LAYER met1 ;
        RECT 1.25 1.24 1.51 2.48 ;
    END
  END A1
  PIN B0
    DIRECTION INPUT ;
    USE SIGNAL ;
    PORT
      LAYER met1 ;
        RECT 2.63 1.195 2.89 2.435 ;
    END
  END B0
  PIN B1
    DIRECTION INPUT ;
    USE SIGNAL ;
    PORT
      LAYER met1 ;
        RECT 1.71 1.205 1.97 2.445 ;
    END
  END B1
  PIN VDD
    DIRECTION INPUT ;
    USE POWER ;
    SHAPE ABUTMENT ;
    NETEXPR "VDD VDD!" ;
    PORT
      LAYER met1 ;
        RECT 0 3.94 3.22 4.34 ;
    END
  END VDD
  PIN VSS
    DIRECTION INPUT ;
    USE GROUND ;
    SHAPE ABUTMENT ;
    NETEXPR "VSS VSS!" ;
    PORT
      LAYER met1 ;
        RECT 0 -0.2 3.22 0.2 ;
    END
  END VSS
  PIN Y
    DIRECTION OUTPUT ;
    USE SIGNAL ;
    PORT
      LAYER met1 ;
        RECT 1.895 2.82 2.43 3.11 ;
        RECT 2.17 0.82 2.43 3.11 ;
        RECT 1.435 0.82 2.43 1.05 ;
    END
  END Y
  OBS
    LAYER met1 ;
      RECT 0.605 3.3 2.585 3.53 ;
      RECT 1.465 2.88 1.695 3.53 ;
      RECT 0.605 2.88 0.835 3.53 ;
  END
  PROPERTY CatenaDesignType "deviceLevel" ;
END AOI22X2_LP

MACRO BUFX16_LP
  CLASS CORE ;
  ORIGIN 0 0 ;
  FOREIGN BUFX16_LP 0 0 ;
  SIZE 5.52 BY 4.14 ;
  SYMMETRY X Y ;
  SITE CoreSite ;
  PIN A
    DIRECTION INPUT ;
    USE SIGNAL ;
    PORT
      LAYER met1 ;
        RECT 0.79 1.355 1.05 2.595 ;
    END
  END A
  PIN VDD
    DIRECTION INPUT ;
    USE POWER ;
    SHAPE ABUTMENT ;
    NETEXPR "VDD VDD!" ;
    PORT
      LAYER met1 ;
        RECT 0 3.94 5.52 4.34 ;
    END
  END VDD
  PIN VSS
    DIRECTION INPUT ;
    USE GROUND ;
    SHAPE ABUTMENT ;
    NETEXPR "VSS VSS!" ;
    PORT
      LAYER met1 ;
        RECT 0 -0.2 5.52 0.2 ;
    END
  END VSS
  PIN Y
    DIRECTION OUTPUT ;
    USE SIGNAL ;
    PORT
      LAYER met1 ;
        RECT 1.895 3.22 4.73 3.51 ;
        RECT 4.47 0.635 4.73 3.51 ;
        RECT 3.615 0.635 3.845 3.51 ;
        RECT 2.755 0.635 2.985 3.51 ;
        RECT 1.895 0.635 2.125 3.51 ;
    END
  END Y
  OBS
    LAYER met1 ;
      RECT 1.035 2.88 1.265 3.53 ;
      RECT 1.035 2.88 1.72 3.11 ;
      RECT 1.49 0.61 1.72 3.11 ;
      RECT 1.035 0.61 1.72 0.9 ;
  END
  PROPERTY CatenaDesignType "deviceLevel" ;
END BUFX16_LP

MACRO BUFX2_LP
  CLASS CORE ;
  ORIGIN 0 0 ;
  FOREIGN BUFX2_LP 0 0 ;
  SIZE 2.76 BY 4.14 ;
  SYMMETRY X Y ;
  SITE CoreSite ;
  PIN A
    DIRECTION INPUT ;
    USE SIGNAL ;
    PORT
      LAYER met1 ;
        RECT 1.25 1.685 1.51 2.925 ;
    END
  END A
  PIN VDD
    DIRECTION INPUT ;
    USE POWER ;
    SHAPE ABUTMENT ;
    NETEXPR "VDD VDD!" ;
    PORT
      LAYER met1 ;
        RECT 0 3.94 2.76 4.34 ;
    END
  END VDD
  PIN VSS
    DIRECTION INPUT ;
    USE GROUND ;
    SHAPE ABUTMENT ;
    NETEXPR "VSS VSS!" ;
    PORT
      LAYER met1 ;
        RECT 0 -0.2 2.76 0.2 ;
    END
  END VSS
  PIN Y
    DIRECTION OUTPUT ;
    USE SIGNAL ;
    PORT
      LAYER met1 ;
        RECT 1.525 3.23 1.97 3.52 ;
        RECT 1.71 0.61 1.97 3.52 ;
        RECT 1.525 0.61 1.97 1.26 ;
    END
  END Y
  OBS
    LAYER met1 ;
      RECT 0.605 3.24 0.835 3.53 ;
      RECT 0.605 0.655 0.745 3.53 ;
      RECT 0.605 1.48 0.975 1.77 ;
      RECT 0.605 0.655 0.835 0.945 ;
  END
  PROPERTY CatenaDesignType "deviceLevel" ;
END BUFX2_LP

MACRO BUFX4_LP
  CLASS CORE ;
  ORIGIN 0 0 ;
  FOREIGN BUFX4_LP 0 0 ;
  SIZE 2.76 BY 4.14 ;
  SYMMETRY X Y ;
  SITE CoreSite ;
  PIN A
    DIRECTION INPUT ;
    USE SIGNAL ;
    PORT
      LAYER met1 ;
        RECT 1.25 1.685 1.51 2.925 ;
    END
  END A
  PIN VDD
    DIRECTION INPUT ;
    USE POWER ;
    SHAPE ABUTMENT ;
    NETEXPR "VDD VDD!" ;
    PORT
      LAYER met1 ;
        RECT 0 3.94 2.76 4.34 ;
    END
  END VDD
  PIN VSS
    DIRECTION INPUT ;
    USE GROUND ;
    SHAPE ABUTMENT ;
    NETEXPR "VSS VSS!" ;
    PORT
      LAYER met1 ;
        RECT 0 -0.2 2.76 0.2 ;
    END
  END VSS
  PIN Y
    DIRECTION OUTPUT ;
    USE SIGNAL ;
    PORT
      LAYER met1 ;
        RECT 1.525 3.23 1.97 3.52 ;
        RECT 1.71 0.61 1.97 3.52 ;
        RECT 1.525 0.61 1.97 1.26 ;
    END
  END Y
  OBS
    LAYER met1 ;
      RECT 0.605 3.24 0.835 3.53 ;
      RECT 0.605 0.655 0.745 3.53 ;
      RECT 0.605 1.565 0.975 1.855 ;
      RECT 0.605 0.655 0.835 0.945 ;
  END
  PROPERTY CatenaDesignType "deviceLevel" ;
END BUFX4_LP

MACRO BUFX8_LP
  CLASS CORE ;
  ORIGIN 0 0 ;
  FOREIGN BUFX8_LP 0 0 ;
  SIZE 3.68 BY 4.14 ;
  SYMMETRY X Y ;
  SITE CoreSite ;
  PIN A
    DIRECTION INPUT ;
    USE SIGNAL ;
    PORT
      LAYER met1 ;
        RECT 1.25 1.165 1.51 2.405 ;
    END
  END A
  PIN VDD
    DIRECTION INPUT ;
    USE POWER ;
    SHAPE ABUTMENT ;
    NETEXPR "VDD VDD!" ;
    PORT
      LAYER met1 ;
        RECT 0 3.94 3.68 4.34 ;
    END
  END VDD
  PIN VSS
    DIRECTION INPUT ;
    USE GROUND ;
    SHAPE ABUTMENT ;
    NETEXPR "VSS VSS!" ;
    PORT
      LAYER met1 ;
        RECT 0 -0.2 3.68 0.2 ;
    END
  END VSS
  PIN Y
    DIRECTION OUTPUT ;
    USE SIGNAL ;
    PORT
      LAYER met1 ;
        RECT 1.465 3.24 2.555 3.53 ;
        RECT 2.17 2.88 2.555 3.53 ;
        RECT 2.17 0.61 2.555 1.26 ;
        RECT 2.17 0.61 2.43 3.53 ;
        RECT 1.465 0.615 2.555 0.905 ;
    END
  END Y
  OBS
    LAYER met1 ;
      RECT 0.605 1.04 0.835 2.73 ;
  END
  PROPERTY CatenaDesignType "deviceLevel" ;
END BUFX8_LP

MACRO CLKAND2X2_LP
  CLASS CORE ;
  ORIGIN 0 0 ;
  FOREIGN CLKAND2X2_LP 0 0 ;
  SIZE 2.76 BY 4.14 ;
  SYMMETRY X Y ;
  SITE CoreSite ;
  PIN A
    DIRECTION INPUT ;
    USE SIGNAL ;
    PORT
      LAYER met1 ;
        RECT 1.71 1.685 1.97 2.925 ;
    END
  END A
  PIN B
    DIRECTION INPUT ;
    USE SIGNAL ;
    PORT
      LAYER met1 ;
        RECT 0.79 1.855 1.05 3.095 ;
    END
  END B
  PIN VDD
    DIRECTION INPUT ;
    USE POWER ;
    SHAPE ABUTMENT ;
    NETEXPR "VDD VDD!" ;
    PORT
      LAYER met1 ;
        RECT 0 3.94 2.76 4.34 ;
    END
  END VDD
  PIN VSS
    DIRECTION INPUT ;
    USE GROUND ;
    SHAPE ABUTMENT ;
    NETEXPR "VSS VSS!" ;
    PORT
      LAYER met1 ;
        RECT 0 -0.2 2.76 0.2 ;
    END
  END VSS
  PIN Y
    DIRECTION OUTPUT ;
    USE SIGNAL ;
    PORT
      LAYER met1 ;
        RECT 1.95 3.24 2.43 3.53 ;
        RECT 2.17 0.68 2.43 3.53 ;
        RECT 1.955 0.68 2.43 1.33 ;
    END
  END Y
  OBS
    LAYER met1 ;
      RECT 1.035 3.24 1.42 3.53 ;
      RECT 1.19 1.55 1.42 3.53 ;
  END
  PROPERTY CatenaDesignType "deviceLevel" ;
END CLKAND2X2_LP

MACRO CLKBUFX2_LP
  CLASS CORE ;
  ORIGIN 0 0 ;
  FOREIGN CLKBUFX2_LP 0 0 ;
  SIZE 2.76 BY 4.14 ;
  SYMMETRY X Y ;
  SITE CoreSite ;
  PIN A
    DIRECTION INPUT ;
    USE SIGNAL ;
    PORT
      LAYER met1 ;
        RECT 1.25 1.805 1.51 3.045 ;
    END
  END A
  PIN VDD
    DIRECTION INPUT ;
    USE POWER ;
    SHAPE ABUTMENT ;
    NETEXPR "VDD VDD!" ;
    PORT
      LAYER met1 ;
        RECT 0 3.94 2.76 4.34 ;
    END
  END VDD
  PIN VSS
    DIRECTION INPUT ;
    USE GROUND ;
    SHAPE ABUTMENT ;
    NETEXPR "VSS VSS!" ;
    PORT
      LAYER met1 ;
        RECT 0 -0.2 2.76 0.2 ;
    END
  END VSS
  PIN Y
    DIRECTION OUTPUT ;
    USE SIGNAL ;
    PORT
      LAYER met1 ;
        RECT 1.525 3.24 1.97 3.53 ;
        RECT 1.71 0.61 1.97 3.53 ;
        RECT 1.525 0.61 1.97 1.26 ;
    END
  END Y
  OBS
    LAYER met1 ;
      RECT 0.605 3.24 0.835 3.53 ;
      RECT 0.605 0.655 0.745 3.53 ;
      RECT 0.605 1.48 0.835 1.77 ;
      RECT 0.605 0.655 0.835 0.945 ;
  END
  PROPERTY CatenaDesignType "deviceLevel" ;
END CLKBUFX2_LP

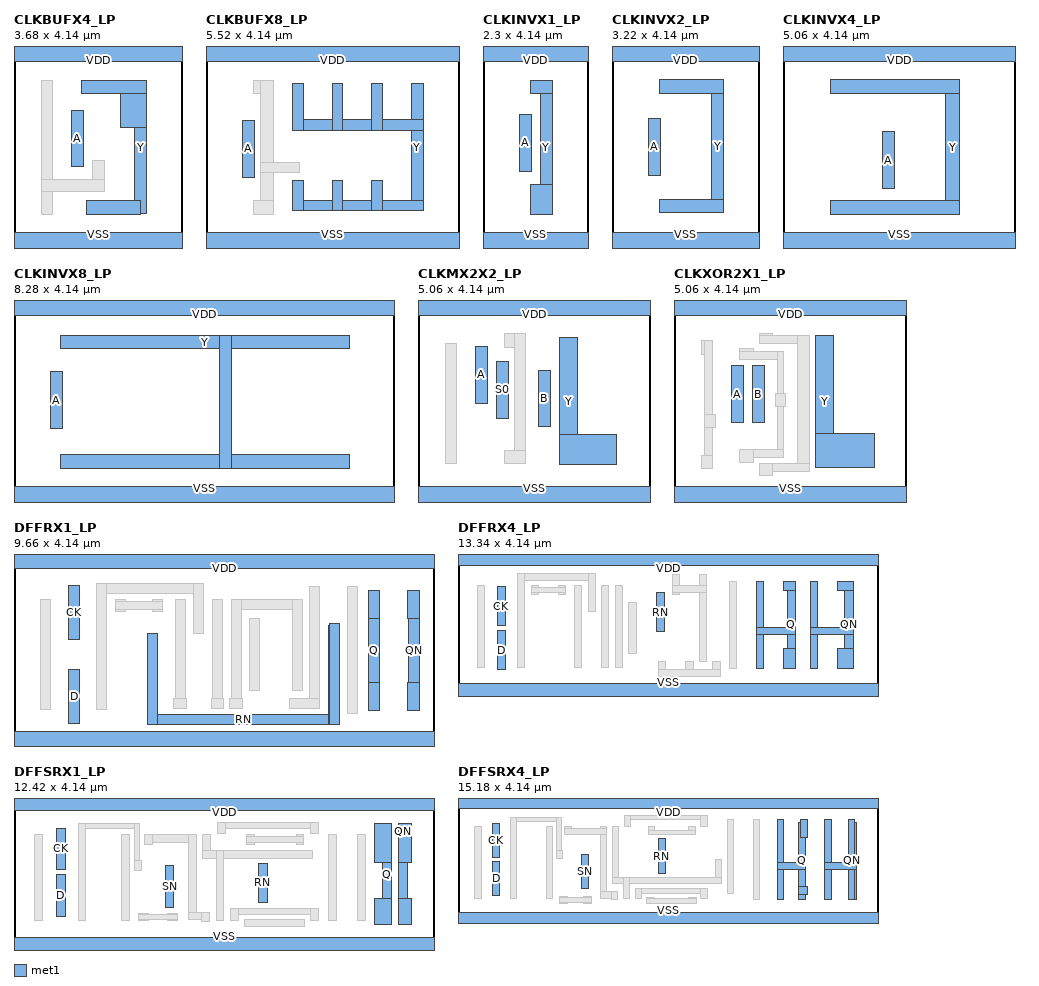
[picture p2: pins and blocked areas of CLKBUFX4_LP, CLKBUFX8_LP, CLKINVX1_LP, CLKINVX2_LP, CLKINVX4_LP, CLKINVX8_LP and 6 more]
MACRO CLKBUFX4_LP
  CLASS CORE ;
  ORIGIN 0 0 ;
  FOREIGN CLKBUFX4_LP 0 0 ;
  SIZE 3.68 BY 4.14 ;
  SYMMETRY X Y ;
  SITE CoreSite ;
  PIN A
    DIRECTION INPUT ;
    USE SIGNAL ;
    PORT
      LAYER met1 ;
        RECT 1.25 1.635 1.51 2.875 ;
    END
  END A
  PIN VDD
    DIRECTION INPUT ;
    USE POWER ;
    SHAPE ABUTMENT ;
    NETEXPR "VDD VDD!" ;
    PORT
      LAYER met1 ;
        RECT 0 3.94 3.68 4.34 ;
    END
  END VDD
  PIN VSS
    DIRECTION INPUT ;
    USE GROUND ;
    SHAPE ABUTMENT ;
    NETEXPR "VSS VSS!" ;
    PORT
      LAYER met1 ;
        RECT 0 -0.2 3.68 0.2 ;
    END
  END VSS
  PIN Y
    DIRECTION OUTPUT ;
    USE SIGNAL ;
    PORT
      LAYER met1 ;
        RECT 1.465 3.225 2.89 3.515 ;
        RECT 2.63 0.615 2.89 3.515 ;
        RECT 1.58 0.61 2.76 0.9 ;
        RECT 2.325 2.505 2.89 3.515 ;
    END
  END Y
  OBS
    LAYER met1 ;
      RECT 0.605 0.61 0.835 3.515 ;
      RECT 1.72 1.11 1.98 1.77 ;
      RECT 0.605 1.11 1.98 1.37 ;
  END
  PROPERTY CatenaDesignType "deviceLevel" ;
END CLKBUFX4_LP

MACRO CLKBUFX8_LP
  CLASS CORE ;
  ORIGIN 0 0 ;
  FOREIGN CLKBUFX8_LP 0 0 ;
  SIZE 5.52 BY 4.14 ;
  SYMMETRY X Y ;
  SITE CoreSite ;
  PIN A
    DIRECTION INPUT ;
    USE SIGNAL ;
    PORT
      LAYER met1 ;
        RECT 0.79 1.415 1.05 2.655 ;
    END
  END A
  PIN VDD
    DIRECTION INPUT ;
    USE POWER ;
    SHAPE ABUTMENT ;
    NETEXPR "VDD VDD!" ;
    PORT
      LAYER met1 ;
        RECT 0 3.94 5.52 4.34 ;
    END
  END VDD
  PIN VSS
    DIRECTION INPUT ;
    USE GROUND ;
    SHAPE ABUTMENT ;
    NETEXPR "VSS VSS!" ;
    PORT
      LAYER met1 ;
        RECT 0 -0.2 5.52 0.2 ;
    END
  END VSS
  PIN Y
    DIRECTION OUTPUT ;
    USE SIGNAL ;
    PORT
      LAYER met1 ;
        RECT 4.47 0.68 4.73 3.45 ;
        RECT 1.895 2.44 4.73 2.67 ;
        RECT 1.895 0.68 4.73 0.91 ;
        RECT 3.615 2.44 3.845 3.45 ;
        RECT 3.615 0.68 3.845 1.33 ;
        RECT 2.755 2.44 2.985 3.45 ;
        RECT 2.755 0.68 2.985 1.33 ;
        RECT 1.895 2.44 2.125 3.45 ;
        RECT 1.895 0.68 2.125 1.33 ;
    END
  END Y
  OBS
    LAYER met1 ;
      RECT 1.035 3.235 1.48 3.525 ;
      RECT 1.19 0.61 1.48 3.525 ;
      RECT 1.19 1.51 2.03 1.74 ;
      RECT 1.035 0.61 1.48 0.9 ;
  END
  PROPERTY CatenaDesignType "deviceLevel" ;
END CLKBUFX8_LP

MACRO CLKINVX1_LP
  CLASS CORE ;
  ORIGIN 0 0 ;
  FOREIGN CLKINVX1_LP 0 0 ;
  SIZE 2.3 BY 4.14 ;
  SYMMETRY X Y ;
  SITE CoreSite ;
  PIN A
    DIRECTION INPUT ;
    USE SIGNAL ;
    PORT
      LAYER met1 ;
        RECT 0.79 1.54 1.05 2.78 ;
    END
  END A
  PIN VDD
    DIRECTION INPUT ;
    USE POWER ;
    SHAPE ABUTMENT ;
    NETEXPR "VDD VDD!" ;
    PORT
      LAYER met1 ;
        RECT 0 3.94 2.3 4.34 ;
    END
  END VDD
  PIN VSS
    DIRECTION INPUT ;
    USE GROUND ;
    SHAPE ABUTMENT ;
    NETEXPR "VSS VSS!" ;
    PORT
      LAYER met1 ;
        RECT 0 -0.2 2.3 0.2 ;
    END
  END VSS
  PIN Y
    DIRECTION OUTPUT ;
    USE SIGNAL ;
    PORT
      LAYER met1 ;
        RECT 1.035 3.235 1.51 3.525 ;
        RECT 1.25 0.61 1.51 3.525 ;
        RECT 1.035 0.61 1.51 1.26 ;
    END
  END Y
  PROPERTY CatenaDesignType "deviceLevel" ;
END CLKINVX1_LP

MACRO CLKINVX2_LP
  CLASS CORE ;
  ORIGIN 0 0 ;
  FOREIGN CLKINVX2_LP 0 0 ;
  SIZE 3.22 BY 4.14 ;
  SYMMETRY X Y ;
  SITE CoreSite ;
  PIN A
    DIRECTION INPUT ;
    USE SIGNAL ;
    PORT
      LAYER met1 ;
        RECT 0.79 1.455 1.05 2.695 ;
    END
  END A
  PIN VDD
    DIRECTION INPUT ;
    USE POWER ;
    SHAPE ABUTMENT ;
    NETEXPR "VDD VDD!" ;
    PORT
      LAYER met1 ;
        RECT 0 3.94 3.22 4.34 ;
    END
  END VDD
  PIN VSS
    DIRECTION INPUT ;
    USE GROUND ;
    SHAPE ABUTMENT ;
    NETEXPR "VSS VSS!" ;
    PORT
      LAYER met1 ;
        RECT 0 -0.2 3.22 0.2 ;
    END
  END VSS
  PIN Y
    DIRECTION OUTPUT ;
    USE SIGNAL ;
    PORT
      LAYER met1 ;
        RECT 1.035 3.24 2.43 3.53 ;
        RECT 2.17 0.64 2.43 3.53 ;
        RECT 1.035 0.64 2.43 0.93 ;
    END
  END Y
  PROPERTY CatenaDesignType "deviceLevel" ;
END CLKINVX2_LP

MACRO CLKINVX4_LP
  CLASS CORE ;
  ORIGIN 0 0 ;
  FOREIGN CLKINVX4_LP 0 0 ;
  SIZE 5.06 BY 4.14 ;
  SYMMETRY X Y ;
  SITE CoreSite ;
  PIN A
    DIRECTION INPUT ;
    USE SIGNAL ;
    PORT
      LAYER met1 ;
        RECT 2.17 1.165 2.43 2.405 ;
    END
  END A
  PIN VDD
    DIRECTION INPUT ;
    USE POWER ;
    SHAPE ABUTMENT ;
    NETEXPR "VDD VDD!" ;
    PORT
      LAYER met1 ;
        RECT 0 3.94 5.06 4.34 ;
    END
  END VDD
  PIN VSS
    DIRECTION INPUT ;
    USE GROUND ;
    SHAPE ABUTMENT ;
    NETEXPR "VSS VSS!" ;
    PORT
      LAYER met1 ;
        RECT 0 -0.2 5.06 0.2 ;
    END
  END VSS
  PIN Y
    DIRECTION OUTPUT ;
    USE SIGNAL ;
    PORT
      LAYER met1 ;
        RECT 1.035 3.24 3.845 3.53 ;
        RECT 3.55 0.61 3.845 3.53 ;
        RECT 1.035 0.61 3.845 0.9 ;
    END
  END Y
  PROPERTY CatenaDesignType "deviceLevel" ;
END CLKINVX4_LP

MACRO CLKINVX8_LP
  CLASS CORE ;
  ORIGIN 0 0 ;
  FOREIGN CLKINVX8_LP 0 0 ;
  SIZE 8.28 BY 4.14 ;
  SYMMETRY X Y ;
  SITE CoreSite ;
  PIN A
    DIRECTION INPUT ;
    USE SIGNAL ;
    PORT
      LAYER met1 ;
        RECT 0.79 1.465 1.05 2.705 ;
    END
  END A
  PIN VDD
    DIRECTION INPUT ;
    USE POWER ;
    SHAPE ABUTMENT ;
    NETEXPR "VDD VDD!" ;
    PORT
      LAYER met1 ;
        RECT 0 3.94 8.28 4.34 ;
    END
  END VDD
  PIN VSS
    DIRECTION INPUT ;
    USE GROUND ;
    SHAPE ABUTMENT ;
    NETEXPR "VSS VSS!" ;
    PORT
      LAYER met1 ;
        RECT 0 -0.2 8.28 0.2 ;
    END
  END VSS
  PIN Y
    DIRECTION OUTPUT ;
    USE SIGNAL ;
    PORT
      LAYER met1 ;
        RECT 1.005 3.21 7.315 3.5 ;
        RECT 1.005 0.61 7.315 0.9 ;
        RECT 4.47 0.61 4.73 3.5 ;
    END
  END Y
  PROPERTY CatenaDesignType "deviceLevel" ;
END CLKINVX8_LP

MACRO CLKMX2X2_LP
  CLASS CORE ;
  ORIGIN 0 0 ;
  FOREIGN CLKMX2X2_LP 0 0 ;
  SIZE 5.06 BY 4.14 ;
  SYMMETRY X Y ;
  SITE CoreSite ;
  PIN A
    DIRECTION INPUT ;
    USE SIGNAL ;
    PORT
      LAYER met1 ;
        RECT 1.25 2.02 1.51 3.26 ;
    END
  END A
  PIN B
    DIRECTION INPUT ;
    USE SIGNAL ;
    PORT
      LAYER met1 ;
        RECT 2.63 1.505 2.89 2.745 ;
    END
  END B
  PIN S0
    DIRECTION INPUT ;
    USE SIGNAL ;
    PORT
      LAYER met1 ;
        RECT 1.71 1.69 1.97 2.93 ;
    END
  END S0
  PIN VDD
    DIRECTION INPUT ;
    USE POWER ;
    SHAPE ABUTMENT ;
    NETEXPR "VDD VDD!" ;
    PORT
      LAYER met1 ;
        RECT 0 3.94 5.06 4.34 ;
    END
  END VDD
  PIN VSS
    DIRECTION INPUT ;
    USE GROUND ;
    SHAPE ABUTMENT ;
    NETEXPR "VSS VSS!" ;
    PORT
      LAYER met1 ;
        RECT 0 -0.2 5.06 0.2 ;
    END
  END VSS
  PIN Y
    DIRECTION OUTPUT ;
    USE SIGNAL ;
    PORT
      LAYER met1 ;
        RECT 3.09 0.68 4.335 1.33 ;
        RECT 3.09 0.68 3.475 3.45 ;
    END
  END Y
  OBS
    LAYER met1 ;
      RECT 1.895 3.24 2.34 3.53 ;
      RECT 2.11 0.705 2.34 3.53 ;
      RECT 1.895 0.705 2.34 0.995 ;
      RECT 0.605 0.705 0.835 3.32 ;
  END
  PROPERTY CatenaDesignType "deviceLevel" ;
END CLKMX2X2_LP

MACRO CLKXOR2X1_LP
  CLASS CORE ;
  ORIGIN 0 0 ;
  FOREIGN CLKXOR2X1_LP 0 0 ;
  SIZE 5.06 BY 4.14 ;
  SYMMETRY X Y ;
  SITE CoreSite ;
  PIN A
    DIRECTION INPUT ;
    USE SIGNAL ;
    PORT
      LAYER met1 ;
        RECT 1.25 1.595 1.51 2.835 ;
    END
  END A
  PIN B
    DIRECTION INPUT ;
    USE SIGNAL ;
    PORT
      LAYER met1 ;
        RECT 1.71 1.595 1.97 2.835 ;
    END
  END B
  PIN VDD
    DIRECTION INPUT ;
    USE POWER ;
    SHAPE ABUTMENT ;
    NETEXPR "VDD VDD!" ;
    PORT
      LAYER met1 ;
        RECT 0 3.94 5.06 4.34 ;
    END
  END VDD
  PIN VSS
    DIRECTION INPUT ;
    USE GROUND ;
    SHAPE ABUTMENT ;
    NETEXPR "VSS VSS!" ;
    PORT
      LAYER met1 ;
        RECT 0 -0.2 5.06 0.2 ;
    END
  END VSS
  PIN Y
    DIRECTION OUTPUT ;
    USE SIGNAL ;
    PORT
      LAYER met1 ;
        RECT 3.09 0.625 4.36 1.355 ;
        RECT 3.09 0.62 3.475 3.495 ;
    END
  END Y
  OBS
    LAYER met1 ;
      RECT 1.865 3.32 2.155 3.55 ;
      RECT 1.865 3.32 2.95 3.49 ;
      RECT 2.69 0.535 2.95 3.49 ;
      RECT 1.865 0.535 2.95 0.705 ;
      RECT 1.865 0.45 2.155 0.705 ;
      RECT 1.435 2.98 1.725 3.21 ;
      RECT 1.435 2.98 2.395 3.15 ;
      RECT 2.255 0.845 2.395 3.15 ;
      RECT 2.205 1.95 2.435 2.24 ;
      RECT 1.435 0.845 2.395 1.015 ;
      RECT 1.435 0.735 1.725 1.015 ;
      RECT 0.605 3.09 0.835 3.38 ;
      RECT 0.665 0.6 0.835 3.38 ;
      RECT 0.665 1.495 0.895 1.785 ;
      RECT 0.605 0.6 0.835 0.89 ;
  END
  PROPERTY CatenaDesignType "deviceLevel" ;
END CLKXOR2X1_LP

MACRO DFFRX1_LP
  CLASS CORE ;
  ORIGIN 0 0 ;
  FOREIGN DFFRX1_LP 0 0 ;
  SIZE 9.66 BY 4.14 ;
  SYMMETRY X Y ;
  SITE CoreSite ;
  PIN CK
    DIRECTION INPUT ;
    USE SIGNAL ;
    PORT
      LAYER met1 ;
        RECT 1.25 2.315 1.51 3.555 ;
    END
  END CK
  PIN D
    DIRECTION INPUT ;
    USE SIGNAL ;
    PORT
      LAYER met1 ;
        RECT 1.25 0.385 1.51 1.625 ;
    END
  END D
  PIN Q
    DIRECTION OUTPUT ;
    USE SIGNAL ;
    PORT
      LAYER met1 ;
        RECT 8.15 2.8 8.415 3.45 ;
        RECT 8.15 0.68 8.415 1.33 ;
        RECT 8.15 0.68 8.41 3.45 ;
    END
  END Q
  PIN QN
    DIRECTION OUTPUT ;
    USE SIGNAL ;
    PORT
      LAYER met1 ;
        RECT 9.045 2.8 9.33 3.45 ;
        RECT 9.07 0.68 9.33 3.45 ;
        RECT 9.045 0.68 9.33 1.33 ;
    END
  END QN
  PIN RN
    DIRECTION INPUT ;
    USE SIGNAL ;
    PORT
      LAYER met1 ;
        RECT 7.23 0.36 7.49 2.645 ;
        RECT 7.245 0.36 7.475 2.67 ;
        RECT 3.06 0.36 7.49 0.59 ;
        RECT 3.06 0.36 3.29 2.455 ;
    END
  END RN
  PIN VDD
    DIRECTION INPUT ;
    USE POWER ;
    SHAPE ABUTMENT ;
    NETEXPR "VDD VDD!" ;
    PORT
      LAYER met1 ;
        RECT 0 3.94 9.66 4.34 ;
    END
  END VDD
  PIN VSS
    DIRECTION INPUT ;
    USE GROUND ;
    SHAPE ABUTMENT ;
    NETEXPR "VSS VSS!" ;
    PORT
      LAYER met1 ;
        RECT 0 -0.2 9.66 0.2 ;
    END
  END VSS
  OBS
    LAYER met1 ;
      RECT 6.805 0.735 7.035 3.53 ;
      RECT 6.345 0.735 7.035 0.965 ;
      RECT 4.995 3.005 6.63 3.235 ;
      RECT 6.4 1.145 6.63 3.235 ;
      RECT 4.995 0.735 5.225 3.235 ;
      RECT 4.965 0.735 5.255 0.965 ;
      RECT 4.565 0.735 4.795 3.235 ;
      RECT 4.535 0.735 4.825 0.965 ;
      RECT 1.895 3.375 4.365 3.605 ;
      RECT 4.135 2.455 4.365 3.605 ;
      RECT 1.895 0.705 2.125 3.605 ;
      RECT 3.705 0.73 3.935 3.235 ;
      RECT 3.675 0.73 3.965 0.96 ;
      RECT 3.185 2.945 3.415 3.235 ;
      RECT 2.325 2.945 2.555 3.235 ;
      RECT 2.325 3.005 3.415 3.175 ;
      RECT 7.665 0.61 7.895 3.53 ;
      RECT 5.425 1.145 5.655 2.795 ;
      RECT 0.605 0.705 0.835 3.235 ;
  END
  PROPERTY CatenaDesignType "deviceLevel" ;
END DFFRX1_LP

MACRO DFFRX4_LP
  CLASS CORE ;
  ORIGIN 0 0 ;
  FOREIGN DFFRX4_LP 0 0 ;
  SIZE 13.34 BY 4.14 ;
  SYMMETRY X Y ;
  SITE CoreSite ;
  PIN CK
    DIRECTION INPUT ;
    USE SIGNAL ;
    PORT
      LAYER met1 ;
        RECT 1.25 2.045 1.51 3.285 ;
    END
  END CK
  PIN D
    DIRECTION INPUT ;
    USE SIGNAL ;
    PORT
      LAYER met1 ;
        RECT 1.25 0.645 1.51 1.885 ;
    END
  END D
  PIN Q
    DIRECTION OUTPUT ;
    USE SIGNAL ;
    PORT
      LAYER met1 ;
        RECT 10.335 3.16 10.71 3.45 ;
        RECT 10.45 0.68 10.71 3.45 ;
        RECT 9.475 1.77 10.71 2 ;
        RECT 10.335 0.68 10.71 1.33 ;
        RECT 9.475 0.68 9.705 3.45 ;
    END
  END Q
  PIN QN
    DIRECTION OUTPUT ;
    USE SIGNAL ;
    PORT
      LAYER met1 ;
        RECT 12.055 3.16 12.55 3.45 ;
        RECT 12.29 0.68 12.55 3.45 ;
        RECT 11.195 1.77 12.55 2 ;
        RECT 12.055 0.68 12.55 1.33 ;
        RECT 11.195 0.68 11.425 3.45 ;
    END
  END QN
  PIN RN
    DIRECTION INPUT ;
    USE SIGNAL ;
    PORT
      LAYER met1 ;
        RECT 6.31 1.85 6.57 3.09 ;
    END
  END RN
  PIN VDD
    DIRECTION INPUT ;
    USE POWER ;
    SHAPE ABUTMENT ;
    NETEXPR "VDD VDD!" ;
    PORT
      LAYER met1 ;
        RECT 0 3.94 13.34 4.34 ;
    END
  END VDD
  PIN VSS
    DIRECTION INPUT ;
    USE GROUND ;
    SHAPE ABUTMENT ;
    NETEXPR "VSS VSS!" ;
    PORT
      LAYER met1 ;
        RECT 0 -0.2 13.34 0.2 ;
    END
  END VSS
  OBS
    LAYER met1 ;
      RECT 8.095 0.43 8.325 0.9 ;
      RECT 7.235 0.43 7.465 0.9 ;
      RECT 6.375 0.43 6.605 0.9 ;
      RECT 6.375 0.43 8.325 0.66 ;
      RECT 7.665 0.89 7.895 3.68 ;
      RECT 6.805 3.03 7.035 3.68 ;
      RECT 6.805 3.1 7.895 3.33 ;
      RECT 1.895 3.47 4.365 3.7 ;
      RECT 4.135 2.505 4.365 3.7 ;
      RECT 1.895 0.705 2.125 3.7 ;
      RECT 3.185 3.03 3.415 3.32 ;
      RECT 2.325 3.03 2.555 3.32 ;
      RECT 2.325 3.09 3.415 3.26 ;
      RECT 8.615 0.68 8.845 3.45 ;
      RECT 5.425 1.145 5.655 2.795 ;
      RECT 4.995 0.705 5.225 3.32 ;
      RECT 4.565 0.705 4.795 3.32 ;
      RECT 3.705 0.705 3.935 3.32 ;
      RECT 0.605 0.705 0.835 3.32 ;
  END
  PROPERTY CatenaDesignType "deviceLevel" ;
END DFFRX4_LP

MACRO DFFSRX1_LP
  CLASS CORE ;
  ORIGIN 0 0 ;
  FOREIGN DFFSRX1_LP 0 0 ;
  SIZE 12.42 BY 4.14 ;
  SYMMETRY X Y ;
  SITE CoreSite ;
  PIN CK
    DIRECTION INPUT ;
    USE SIGNAL ;
    PORT
      LAYER met1 ;
        RECT 1.25 2.19 1.51 3.43 ;
    END
  END CK
  PIN D
    DIRECTION INPUT ;
    USE SIGNAL ;
    PORT
      LAYER met1 ;
        RECT 1.25 0.805 1.51 2.045 ;
    END
  END D
  PIN Q
    DIRECTION OUTPUT ;
    USE SIGNAL ;
    PORT
      LAYER met1 ;
        RECT 10.675 2.42 11.17 3.57 ;
        RECT 10.91 0.57 11.17 3.57 ;
        RECT 10.675 0.57 11.17 1.35 ;
    END
  END Q
  PIN QN
    DIRECTION OUTPUT ;
    USE SIGNAL ;
    PORT
      LAYER met1 ;
        RECT 11.37 2.42 11.765 3.57 ;
        RECT 11.37 0.57 11.765 1.35 ;
        RECT 11.37 0.57 11.63 3.57 ;
    END
  END QN
  PIN RN
    DIRECTION INPUT ;
    USE SIGNAL ;
    PORT
      LAYER met1 ;
        RECT 7.23 1.23 7.49 2.395 ;
    END
  END RN
  PIN SN
    DIRECTION INPUT ;
    USE SIGNAL ;
    PORT
      LAYER met1 ;
        RECT 4.47 1.075 4.73 2.315 ;
    END
  END SN
  PIN VDD
    DIRECTION INPUT ;
    USE POWER ;
    SHAPE ABUTMENT ;
    NETEXPR "VDD VDD!" ;
    PORT
      LAYER met1 ;
        RECT 0 3.94 12.42 4.34 ;
    END
  END VDD
  PIN VSS
    DIRECTION INPUT ;
    USE GROUND ;
    SHAPE ABUTMENT ;
    NETEXPR "VSS VSS!" ;
    PORT
      LAYER met1 ;
        RECT 0 -0.2 12.42 0.2 ;
    END
  END VSS
  OBS
    LAYER met1 ;
      RECT 6.405 0.875 9.005 1.045 ;
      RECT 8.775 0.705 9.005 1.045 ;
      RECT 6.405 0.705 6.635 1.045 ;
      RECT 6.015 3.425 9.005 3.595 ;
      RECT 8.775 3.26 9.005 3.595 ;
      RECT 6.015 3.26 6.245 3.595 ;
      RECT 5.585 2.535 5.815 3.235 ;
      RECT 5.585 2.535 8.84 2.765 ;
      RECT 5.975 0.705 6.205 2.765 ;
      RECT 8.345 2.945 8.575 3.235 ;
      RECT 6.875 2.945 7.105 3.235 ;
      RECT 6.875 3.005 8.575 3.175 ;
      RECT 3.865 3.005 5.385 3.235 ;
      RECT 5.155 0.715 5.385 3.235 ;
      RECT 3.865 2.945 4.095 3.235 ;
      RECT 5.155 0.715 5.775 0.945 ;
      RECT 5.545 0.655 5.775 0.945 ;
      RECT 4.535 0.685 4.825 0.915 ;
      RECT 3.675 0.685 3.965 0.915 ;
      RECT 3.675 0.715 4.825 0.885 ;
      RECT 1.895 3.405 3.725 3.575 ;
      RECT 3.555 2.165 3.725 3.575 ;
      RECT 1.895 0.705 2.125 3.575 ;
      RECT 3.555 2.165 3.785 2.455 ;
      RECT 10.155 0.705 10.385 3.235 ;
      RECT 9.295 0.705 9.525 3.235 ;
      RECT 6.805 0.505 8.605 0.735 ;
      RECT 3.185 0.705 3.415 3.235 ;
      RECT 0.605 0.705 0.835 3.235 ;
  END
  PROPERTY CatenaDesignType "deviceLevel" ;
END DFFSRX1_LP

MACRO DFFSRX4_LP
  CLASS CORE ;
  ORIGIN 0 0 ;
  FOREIGN DFFSRX4_LP 0 0 ;
  SIZE 15.18 BY 4.14 ;
  SYMMETRY X Y ;
  SITE CoreSite ;
  PIN CK
    DIRECTION INPUT ;
    USE SIGNAL ;
    PORT
      LAYER met1 ;
        RECT 1.25 2.19 1.51 3.43 ;
    END
  END CK
  PIN D
    DIRECTION INPUT ;
    USE SIGNAL ;
    PORT
      LAYER met1 ;
        RECT 1.25 0.805 1.51 2.045 ;
    END
  END D
  PIN Q
    DIRECTION OUTPUT ;
    USE SIGNAL ;
    PORT
      LAYER met1 ;
        RECT 12.395 2.905 12.625 3.555 ;
        RECT 12.29 0.86 12.625 1.15 ;
        RECT 12.29 0.68 12.55 3.45 ;
        RECT 11.535 1.77 12.55 2 ;
        RECT 11.535 0.68 11.765 3.555 ;
    END
  END Q
  PIN QN
    DIRECTION OUTPUT ;
    USE SIGNAL ;
    PORT
      LAYER met1 ;
        RECT 14.115 0.68 14.39 3.45 ;
        RECT 14.115 0.68 14.345 3.555 ;
        RECT 13.255 1.77 14.39 2 ;
        RECT 13.255 0.68 13.485 3.555 ;
    END
  END QN
  PIN RN
    DIRECTION INPUT ;
    USE SIGNAL ;
    PORT
      LAYER met1 ;
        RECT 7.23 1.62 7.49 2.86 ;
    END
  END RN
  PIN SN
    DIRECTION INPUT ;
    USE SIGNAL ;
    PORT
      LAYER met1 ;
        RECT 4.47 1.06 4.73 2.3 ;
    END
  END SN
  PIN VDD
    DIRECTION INPUT ;
    USE POWER ;
    SHAPE ABUTMENT ;
    NETEXPR "VDD VDD!" ;
    PORT
      LAYER met1 ;
        RECT 0 3.94 15.18 4.34 ;
    END
  END VDD
  PIN VSS
    DIRECTION INPUT ;
    USE GROUND ;
    SHAPE ABUTMENT ;
    NETEXPR "VSS VSS!" ;
    PORT
      LAYER met1 ;
        RECT 0 -0.2 15.18 0.2 ;
    END
  END VSS
  OBS
    LAYER met1 ;
      RECT 5.585 1.25 5.815 3.32 ;
      RECT 9.295 1.25 9.525 2.115 ;
      RECT 5.585 1.25 9.525 1.48 ;
      RECT 5.975 0.705 6.205 1.48 ;
      RECT 6.405 0.88 9.005 1.05 ;
      RECT 8.775 0.705 9.005 1.05 ;
      RECT 6.405 0.705 6.635 1.05 ;
      RECT 6.015 3.545 9.005 3.715 ;
      RECT 8.775 3.325 9.005 3.715 ;
      RECT 6.015 3.325 6.245 3.715 ;
      RECT 8.315 0.51 8.605 0.74 ;
      RECT 6.805 0.51 7.095 0.74 ;
      RECT 6.805 0.54 8.605 0.71 ;
      RECT 8.345 3.005 8.575 3.32 ;
      RECT 6.875 3.005 7.105 3.32 ;
      RECT 6.875 3.005 8.575 3.175 ;
      RECT 5.155 0.715 5.385 3.32 ;
      RECT 3.865 3.005 4.095 3.32 ;
      RECT 3.865 3.005 5.385 3.235 ;
      RECT 5.155 0.715 5.775 0.945 ;
      RECT 5.545 0.655 5.775 0.945 ;
      RECT 4.535 0.54 4.825 0.77 ;
      RECT 3.675 0.54 3.965 0.77 ;
      RECT 3.675 0.57 4.825 0.74 ;
      RECT 1.895 3.475 3.725 3.645 ;
      RECT 3.555 2.165 3.725 3.645 ;
      RECT 1.895 0.705 2.125 3.645 ;
      RECT 3.555 2.165 3.785 2.455 ;
      RECT 10.675 0.68 10.905 3.555 ;
      RECT 9.725 0.88 9.955 3.57 ;
      RECT 3.185 0.705 3.415 3.32 ;
      RECT 0.605 0.705 0.835 3.32 ;
  END
  PROPERTY CatenaDesignType "deviceLevel" ;
END DFFSRX4_LP

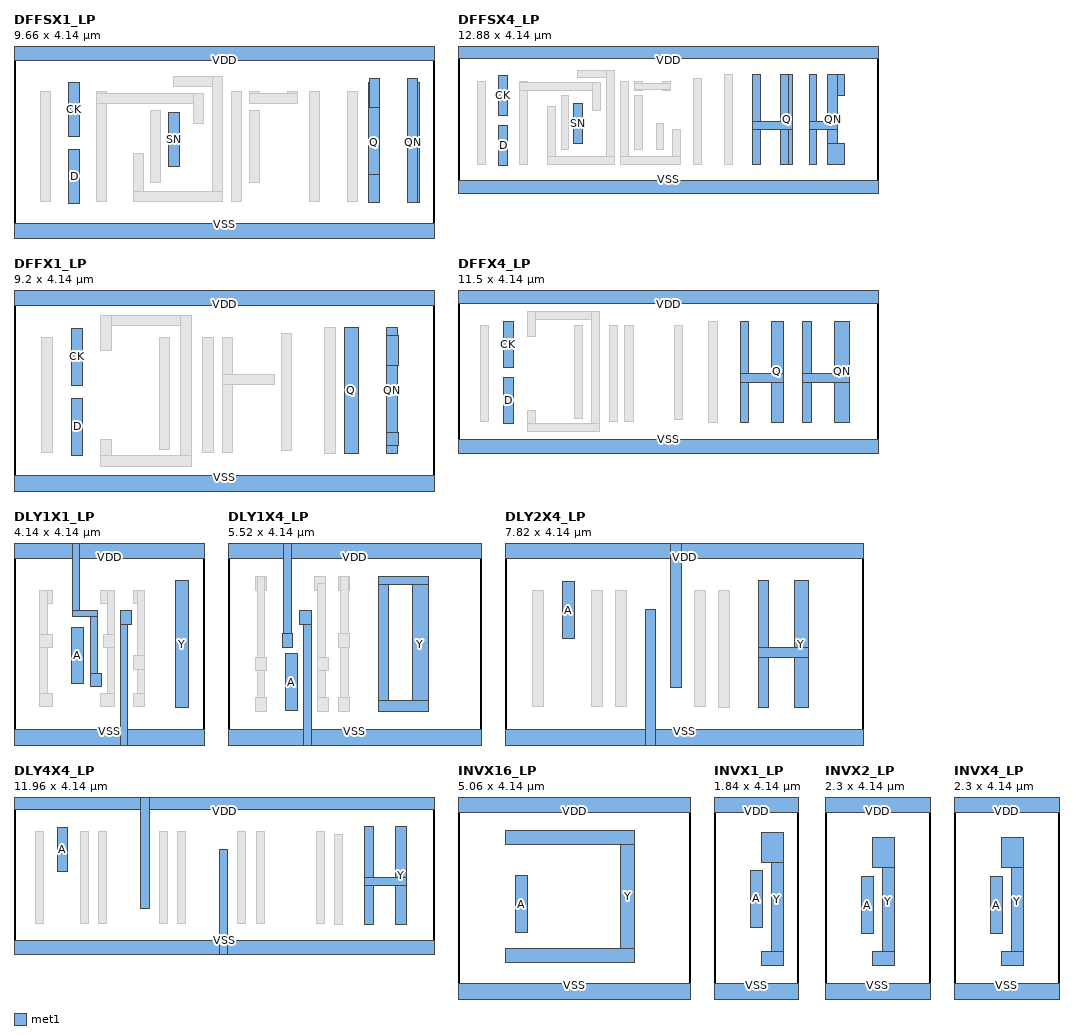
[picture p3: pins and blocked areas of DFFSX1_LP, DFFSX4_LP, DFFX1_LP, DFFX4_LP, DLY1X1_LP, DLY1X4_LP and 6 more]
MACRO DFFSX1_LP
  CLASS CORE ;
  ORIGIN 0 0 ;
  FOREIGN DFFSX1_LP 0 0 ;
  SIZE 9.66 BY 4.14 ;
  SYMMETRY X Y ;
  SITE CoreSite ;
  PIN CK
    DIRECTION INPUT ;
    USE SIGNAL ;
    PORT
      LAYER met1 ;
        RECT 1.25 2.19 1.51 3.43 ;
    END
  END CK
  PIN D
    DIRECTION INPUT ;
    USE SIGNAL ;
    PORT
      LAYER met1 ;
        RECT 1.25 0.655 1.51 1.895 ;
    END
  END D
  PIN Q
    DIRECTION OUTPUT ;
    USE SIGNAL ;
    PORT
      LAYER met1 ;
        RECT 8.185 2.875 8.415 3.525 ;
        RECT 8.15 0.68 8.415 1.33 ;
        RECT 8.15 0.68 8.41 3.45 ;
    END
  END Q
  PIN QN
    DIRECTION OUTPUT ;
    USE SIGNAL ;
    PORT
      LAYER met1 ;
        RECT 9.045 0.68 9.33 3.45 ;
        RECT 9.045 0.68 9.275 3.525 ;
    END
  END QN
  PIN SN
    DIRECTION INPUT ;
    USE SIGNAL ;
    PORT
      LAYER met1 ;
        RECT 3.545 1.5 3.805 2.74 ;
    END
  END SN
  PIN VDD
    DIRECTION INPUT ;
    USE POWER ;
    SHAPE ABUTMENT ;
    NETEXPR "VDD VDD!" ;
    PORT
      LAYER met1 ;
        RECT 0 3.94 9.66 4.34 ;
    END
  END VDD
  PIN VSS
    DIRECTION INPUT ;
    USE GROUND ;
    SHAPE ABUTMENT ;
    NETEXPR "VSS VSS!" ;
    PORT
      LAYER met1 ;
        RECT 0 -0.2 9.66 0.2 ;
    END
  END VSS
  OBS
    LAYER met1 ;
      RECT 6.285 2.945 6.515 3.235 ;
      RECT 5.425 2.945 5.655 3.235 ;
      RECT 5.425 2.945 6.515 3.175 ;
      RECT 3.675 3.355 4.795 3.585 ;
      RECT 4.565 0.705 4.795 3.585 ;
      RECT 2.755 0.705 2.985 1.795 ;
      RECT 2.755 0.705 4.795 0.935 ;
      RECT 1.895 0.705 2.125 3.235 ;
      RECT 1.895 2.965 4.365 3.195 ;
      RECT 4.135 2.505 4.365 3.195 ;
      RECT 7.665 0.705 7.895 3.235 ;
      RECT 6.805 0.705 7.035 3.235 ;
      RECT 5.425 1.145 5.655 2.795 ;
      RECT 4.995 0.705 5.225 3.235 ;
      RECT 3.145 1.145 3.375 2.795 ;
      RECT 0.605 0.705 0.835 3.235 ;
  END
  PROPERTY CatenaDesignType "deviceLevel" ;
END DFFSX1_LP

MACRO DFFSX4_LP
  CLASS CORE ;
  ORIGIN 0 0 ;
  FOREIGN DFFSX4_LP 0 0 ;
  SIZE 12.88 BY 4.14 ;
  SYMMETRY X Y ;
  SITE CoreSite ;
  PIN CK
    DIRECTION INPUT ;
    USE SIGNAL ;
    PORT
      LAYER met1 ;
        RECT 1.25 2.19 1.51 3.43 ;
    END
  END CK
  PIN D
    DIRECTION INPUT ;
    USE SIGNAL ;
    PORT
      LAYER met1 ;
        RECT 1.25 0.655 1.51 1.895 ;
    END
  END D
  PIN Q
    DIRECTION OUTPUT ;
    USE SIGNAL ;
    PORT
      LAYER met1 ;
        RECT 9.905 0.68 10.25 3.45 ;
        RECT 9.905 0.68 10.135 3.455 ;
        RECT 9.045 1.77 10.25 2 ;
        RECT 9.045 0.68 9.275 3.455 ;
    END
  END Q
  PIN QN
    DIRECTION OUTPUT ;
    USE SIGNAL ;
    PORT
      LAYER met1 ;
        RECT 11.625 2.805 11.855 3.455 ;
        RECT 11.345 0.68 11.855 1.33 ;
        RECT 11.345 0.68 11.63 3.45 ;
        RECT 10.765 1.77 11.63 2 ;
        RECT 10.765 0.68 10.995 3.455 ;
    END
  END QN
  PIN SN
    DIRECTION INPUT ;
    USE SIGNAL ;
    PORT
      LAYER met1 ;
        RECT 3.55 1.33 3.81 2.57 ;
    END
  END SN
  PIN VDD
    DIRECTION INPUT ;
    USE POWER ;
    SHAPE ABUTMENT ;
    NETEXPR "VDD VDD!" ;
    PORT
      LAYER met1 ;
        RECT 0 3.94 12.88 4.34 ;
    END
  END VDD
  PIN VSS
    DIRECTION INPUT ;
    USE GROUND ;
    SHAPE ABUTMENT ;
    NETEXPR "VSS VSS!" ;
    PORT
      LAYER met1 ;
        RECT 0 -0.2 12.88 0.2 ;
    END
  END VSS
  OBS
    LAYER met1 ;
      RECT 4.995 0.705 5.225 3.235 ;
      RECT 6.59 0.705 6.82 1.775 ;
      RECT 4.995 0.705 6.82 0.935 ;
      RECT 6.285 2.945 6.515 3.235 ;
      RECT 5.425 2.945 5.655 3.235 ;
      RECT 5.425 3.005 6.515 3.175 ;
      RECT 3.675 3.355 4.795 3.585 ;
      RECT 4.565 0.705 4.795 3.585 ;
      RECT 2.755 0.705 2.985 2.455 ;
      RECT 2.755 0.705 4.795 0.935 ;
      RECT 1.895 0.705 2.125 3.235 ;
      RECT 1.895 2.965 4.365 3.195 ;
      RECT 4.135 2.335 4.365 3.195 ;
      RECT 8.185 0.68 8.415 3.455 ;
      RECT 7.235 0.7 7.465 3.315 ;
      RECT 6.075 1.145 6.305 1.945 ;
      RECT 5.425 1.145 5.655 2.795 ;
      RECT 3.17 1.145 3.4 2.795 ;
      RECT 0.605 0.705 0.835 3.235 ;
  END
  PROPERTY CatenaDesignType "deviceLevel" ;
END DFFSX4_LP

MACRO DFFX1_LP
  CLASS CORE ;
  ORIGIN 0 0 ;
  FOREIGN DFFX1_LP 0 0 ;
  SIZE 9.2 BY 4.14 ;
  SYMMETRY X Y ;
  SITE CoreSite ;
  PIN CK
    DIRECTION INPUT ;
    USE SIGNAL ;
    PORT
      LAYER met1 ;
        RECT 1.25 2.19 1.51 3.43 ;
    END
  END CK
  PIN D
    DIRECTION INPUT ;
    USE SIGNAL ;
    PORT
      LAYER met1 ;
        RECT 1.25 0.655 1.51 1.895 ;
    END
  END D
  PIN Q
    DIRECTION OUTPUT ;
    USE SIGNAL ;
    PORT
      LAYER met1 ;
        RECT 7.23 0.68 7.555 3.45 ;
    END
  END Q
  PIN QN
    DIRECTION OUTPUT ;
    USE SIGNAL ;
    PORT
      LAYER met1 ;
        RECT 8.15 2.62 8.415 3.27 ;
        RECT 8.15 0.86 8.415 1.15 ;
        RECT 8.15 0.68 8.41 3.45 ;
    END
  END QN
  PIN VDD
    DIRECTION INPUT ;
    USE POWER ;
    SHAPE ABUTMENT ;
    NETEXPR "VDD VDD!" ;
    PORT
      LAYER met1 ;
        RECT 0 3.94 9.2 4.34 ;
    END
  END VDD
  PIN VSS
    DIRECTION INPUT ;
    USE GROUND ;
    SHAPE ABUTMENT ;
    NETEXPR "VSS VSS!" ;
    PORT
      LAYER met1 ;
        RECT 0 -0.2 9.2 0.2 ;
    END
  END VSS
  OBS
    LAYER met1 ;
      RECT 4.565 0.705 4.795 3.235 ;
      RECT 4.565 2.195 5.715 2.425 ;
      RECT 1.895 3.485 3.88 3.715 ;
      RECT 3.65 0.415 3.88 3.715 ;
      RECT 1.895 2.945 2.125 3.715 ;
      RECT 1.895 0.415 2.125 0.995 ;
      RECT 1.895 0.415 3.88 0.645 ;
      RECT 6.805 0.68 7.035 3.45 ;
      RECT 5.855 0.745 6.085 3.315 ;
      RECT 4.135 0.705 4.365 3.235 ;
      RECT 3.185 0.785 3.415 3.235 ;
      RECT 0.605 0.705 0.835 3.235 ;
  END
  PROPERTY CatenaDesignType "deviceLevel" ;
END DFFX1_LP

MACRO DFFX4_LP
  CLASS CORE ;
  ORIGIN 0 0 ;
  FOREIGN DFFX4_LP 0 0 ;
  SIZE 11.5 BY 4.14 ;
  SYMMETRY X Y ;
  SITE CoreSite ;
  PIN CK
    DIRECTION INPUT ;
    USE SIGNAL ;
    PORT
      LAYER met1 ;
        RECT 1.25 2.19 1.51 3.43 ;
    END
  END CK
  PIN D
    DIRECTION INPUT ;
    USE SIGNAL ;
    PORT
      LAYER met1 ;
        RECT 1.25 0.655 1.51 1.895 ;
    END
  END D
  PIN Q
    DIRECTION OUTPUT ;
    USE SIGNAL ;
    PORT
      LAYER met1 ;
        RECT 8.585 0.68 8.91 3.45 ;
        RECT 7.725 1.77 8.91 2 ;
        RECT 7.725 0.68 7.955 3.45 ;
    END
  END Q
  PIN QN
    DIRECTION OUTPUT ;
    USE SIGNAL ;
    PORT
      LAYER met1 ;
        RECT 10.305 0.68 10.71 3.45 ;
        RECT 9.445 1.77 10.71 2 ;
        RECT 9.445 0.68 9.675 3.45 ;
    END
  END QN
  PIN VDD
    DIRECTION INPUT ;
    USE POWER ;
    SHAPE ABUTMENT ;
    NETEXPR "VDD VDD!" ;
    PORT
      LAYER met1 ;
        RECT 0 3.94 11.5 4.34 ;
    END
  END VDD
  PIN VSS
    DIRECTION INPUT ;
    USE GROUND ;
    SHAPE ABUTMENT ;
    NETEXPR "VSS VSS!" ;
    PORT
      LAYER met1 ;
        RECT 0 -0.2 11.5 0.2 ;
    END
  END VSS
  OBS
    LAYER met1 ;
      RECT 1.895 3.485 3.88 3.715 ;
      RECT 3.65 0.415 3.88 3.715 ;
      RECT 1.895 3.03 2.125 3.715 ;
      RECT 1.895 0.415 2.125 0.995 ;
      RECT 1.895 0.415 3.88 0.645 ;
      RECT 6.865 0.68 7.095 3.45 ;
      RECT 5.915 0.745 6.145 3.315 ;
      RECT 4.565 0.705 4.795 3.32 ;
      RECT 4.135 0.705 4.365 3.32 ;
      RECT 3.185 0.785 3.415 3.32 ;
      RECT 0.605 0.705 0.835 3.32 ;
  END
  PROPERTY CatenaDesignType "deviceLevel" ;
END DFFX4_LP

MACRO DLY1X1_LP
  CLASS CORE ;
  ORIGIN 0 0 ;
  FOREIGN DLY1X1_LP 0 0 ;
  SIZE 4.14 BY 4.14 ;
  SYMMETRY X Y ;
  SITE CoreSite ;
  PIN A
    DIRECTION INPUT ;
    USE SIGNAL ;
    PORT
      LAYER met1 ;
        RECT 1.25 1.2 1.51 2.44 ;
    END
  END A
  PIN VDD
    DIRECTION INPUT ;
    USE POWER ;
    SHAPE ABUTMENT ;
    NETEXPR "VDD VDD!" ;
    PORT
      LAYER met1 ;
        RECT 0 3.94 4.14 4.34 ;
        RECT 1.675 1.145 1.905 1.435 ;
        RECT 1.28 2.66 1.815 2.8 ;
        RECT 1.675 1.145 1.815 2.8 ;
        RECT 1.28 2.66 1.42 4.34 ;
    END
  END VDD
  PIN VSS
    DIRECTION INPUT ;
    USE GROUND ;
    SHAPE ABUTMENT ;
    NETEXPR "VSS VSS!" ;
    PORT
      LAYER met1 ;
        RECT 0 -0.2 4.14 0.2 ;
        RECT 2.325 2.505 2.555 2.795 ;
        RECT 2.325 -0.2 2.465 2.795 ;
    END
  END VSS
  PIN Y
    DIRECTION OUTPUT ;
    USE SIGNAL ;
    PORT
      LAYER met1 ;
        RECT 3.525 0.68 3.81 3.45 ;
    END
  END Y
  OBS
    LAYER met1 ;
      RECT 2.605 2.955 2.835 3.245 ;
      RECT 2.695 0.705 2.835 3.245 ;
      RECT 2.605 1.525 2.835 1.815 ;
      RECT 2.605 0.705 2.835 0.995 ;
      RECT 1.895 2.955 2.185 3.245 ;
      RECT 2.045 0.705 2.185 3.245 ;
      RECT 1.955 1.995 2.185 2.285 ;
      RECT 1.895 0.705 2.185 0.995 ;
      RECT 0.55 2.945 0.835 3.235 ;
      RECT 0.55 0.705 0.72 3.235 ;
      RECT 0.55 1.995 0.835 2.285 ;
      RECT 0.55 0.705 0.835 0.995 ;
  END
  PROPERTY CatenaDesignType "deviceLevel" ;
END DLY1X1_LP

MACRO DLY1X4_LP
  CLASS CORE ;
  ORIGIN 0 0 ;
  FOREIGN DLY1X4_LP 0 0 ;
  SIZE 5.52 BY 4.14 ;
  SYMMETRY X Y ;
  SITE CoreSite ;
  PIN A
    DIRECTION INPUT ;
    USE SIGNAL ;
    PORT
      LAYER met1 ;
        RECT 1.25 0.62 1.51 1.86 ;
    END
  END A
  PIN VDD
    DIRECTION INPUT ;
    USE POWER ;
    SHAPE ABUTMENT ;
    NETEXPR "VDD VDD!" ;
    PORT
      LAYER met1 ;
        RECT 0 3.94 5.52 4.34 ;
        RECT 1.185 2 1.415 2.29 ;
        RECT 1.215 2 1.385 4.34 ;
    END
  END VDD
  PIN VSS
    DIRECTION INPUT ;
    USE GROUND ;
    SHAPE ABUTMENT ;
    NETEXPR "VSS VSS!" ;
    PORT
      LAYER met1 ;
        RECT 0 -0.2 5.52 0.2 ;
        RECT 1.555 2.505 1.82 2.795 ;
        RECT 1.65 -0.2 1.82 2.795 ;
    END
  END VSS
  PIN Y
    DIRECTION OUTPUT ;
    USE SIGNAL ;
    PORT
      LAYER met1 ;
        RECT 3.275 3.36 4.365 3.53 ;
        RECT 4.01 0.61 4.365 3.53 ;
        RECT 3.275 0.61 4.365 0.84 ;
        RECT 3.275 0.61 3.505 3.53 ;
    END
  END Y
  OBS
    LAYER met1 ;
      RECT 2.415 3.24 2.645 3.53 ;
      RECT 2.445 0.61 2.615 3.53 ;
      RECT 2.415 2 2.645 2.29 ;
      RECT 2.415 0.61 2.645 0.9 ;
      RECT 1.895 3.24 2.125 3.53 ;
      RECT 1.96 0.61 2.13 3.385 ;
      RECT 1.96 1.485 2.19 1.775 ;
      RECT 1.96 0.61 2.19 0.9 ;
      RECT 0.605 3.24 0.835 3.53 ;
      RECT 0.635 0.61 0.805 3.53 ;
      RECT 0.6 1.485 0.83 1.775 ;
      RECT 0.605 0.61 0.835 0.9 ;
  END
  PROPERTY CatenaDesignType "deviceLevel" ;
END DLY1X4_LP

MACRO DLY2X4_LP
  CLASS CORE ;
  ORIGIN 0 0 ;
  FOREIGN DLY2X4_LP 0 0 ;
  SIZE 7.82 BY 4.14 ;
  SYMMETRY X Y ;
  SITE CoreSite ;
  PIN A
    DIRECTION INPUT ;
    USE SIGNAL ;
    PORT
      LAYER met1 ;
        RECT 1.25 2.19 1.51 3.43 ;
    END
  END A
  PIN VDD
    DIRECTION INPUT ;
    USE POWER ;
    SHAPE ABUTMENT ;
    NETEXPR "VDD VDD!" ;
    PORT
      LAYER met1 ;
        RECT 0 3.94 7.82 4.34 ;
        RECT 3.615 1.125 3.845 4.34 ;
    END
  END VDD
  PIN VSS
    DIRECTION INPUT ;
    USE GROUND ;
    SHAPE ABUTMENT ;
    NETEXPR "VSS VSS!" ;
    PORT
      LAYER met1 ;
        RECT 0 -0.2 7.82 0.2 ;
        RECT 3.06 -0.2 3.29 2.815 ;
    END
  END VSS
  PIN Y
    DIRECTION OUTPUT ;
    USE SIGNAL ;
    PORT
      LAYER met1 ;
        RECT 6.31 0.68 6.605 3.45 ;
        RECT 5.515 1.77 6.605 2 ;
        RECT 5.515 0.68 5.745 3.45 ;
    END
  END Y
  OBS
    LAYER met1 ;
      RECT 4.655 0.68 4.885 3.235 ;
      RECT 4.135 0.705 4.365 3.235 ;
      RECT 2.415 0.705 2.645 3.235 ;
      RECT 1.895 0.705 2.125 3.235 ;
      RECT 0.605 0.705 0.835 3.235 ;
  END
  PROPERTY CatenaDesignType "deviceLevel" ;
END DLY2X4_LP

MACRO DLY4X4_LP
  CLASS CORE ;
  ORIGIN 0 0 ;
  FOREIGN DLY4X4_LP 0 0 ;
  SIZE 11.96 BY 4.14 ;
  SYMMETRY X Y ;
  SITE CoreSite ;
  PIN A
    DIRECTION INPUT ;
    USE SIGNAL ;
    PORT
      LAYER met1 ;
        RECT 1.25 2.19 1.51 3.43 ;
    END
  END A
  PIN VDD
    DIRECTION INPUT ;
    USE POWER ;
    SHAPE ABUTMENT ;
    NETEXPR "VDD VDD!" ;
    PORT
      LAYER met1 ;
        RECT 0 3.94 11.96 4.34 ;
        RECT 3.615 1.125 3.845 4.34 ;
    END
  END VDD
  PIN VSS
    DIRECTION INPUT ;
    USE GROUND ;
    SHAPE ABUTMENT ;
    NETEXPR "VSS VSS!" ;
    PORT
      LAYER met1 ;
        RECT 0 -0.2 11.965 0.2 ;
        RECT 5.855 -0.2 6.085 2.815 ;
    END
  END VSS
  PIN Y
    DIRECTION OUTPUT ;
    USE SIGNAL ;
    PORT
      LAYER met1 ;
        RECT 10.855 0.68 11.17 3.45 ;
        RECT 9.995 1.77 11.17 2 ;
        RECT 9.995 0.68 10.225 3.45 ;
    END
  END Y
  OBS
    LAYER met1 ;
      RECT 9.135 0.68 9.365 3.235 ;
      RECT 8.615 0.705 8.845 3.32 ;
      RECT 6.895 0.705 7.125 3.32 ;
      RECT 6.375 0.705 6.605 3.32 ;
      RECT 4.655 0.705 4.885 3.32 ;
      RECT 4.135 0.705 4.365 3.32 ;
      RECT 2.415 0.705 2.645 3.32 ;
      RECT 1.895 0.705 2.125 3.32 ;
      RECT 0.605 0.705 0.835 3.32 ;
  END
  PROPERTY CatenaDesignType "deviceLevel" ;
END DLY4X4_LP

MACRO INVX16_LP
  CLASS CORE ;
  ORIGIN 0 0 ;
  FOREIGN INVX16_LP 0 0 ;
  SIZE 5.06 BY 4.14 ;
  SYMMETRY X Y ;
  SITE CoreSite ;
  PIN A
    DIRECTION INPUT ;
    USE SIGNAL ;
    PORT
      LAYER met1 ;
        RECT 1.25 1.315 1.51 2.555 ;
    END
  END A
  PIN VDD
    DIRECTION INPUT ;
    USE POWER ;
    SHAPE ABUTMENT ;
    NETEXPR "VDD VDD!" ;
    PORT
      LAYER met1 ;
        RECT 0 3.94 5.06 4.34 ;
    END
  END VDD
  PIN VSS
    DIRECTION INPUT ;
    USE GROUND ;
    SHAPE ABUTMENT ;
    NETEXPR "VSS VSS!" ;
    PORT
      LAYER met1 ;
        RECT 0 -0.2 5.06 0.2 ;
    END
  END VSS
  PIN Y
    DIRECTION OUTPUT ;
    USE SIGNAL ;
    PORT
      LAYER met1 ;
        RECT 1.035 3.24 3.845 3.53 ;
        RECT 3.55 0.675 3.845 3.53 ;
        RECT 1.035 0.675 3.845 0.965 ;
    END
  END Y
  PROPERTY CatenaDesignType "deviceLevel" ;
END INVX16_LP

MACRO INVX1_LP
  CLASS CORE ;
  ORIGIN 0 0 ;
  FOREIGN INVX1_LP 0 0 ;
  SIZE 1.84 BY 4.14 ;
  SYMMETRY X Y ;
  SITE CoreSite ;
  PIN A
    DIRECTION INPUT ;
    USE SIGNAL ;
    PORT
      LAYER met1 ;
        RECT 0.79 1.43 1.05 2.67 ;
    END
  END A
  PIN VDD
    DIRECTION INPUT ;
    USE POWER ;
    SHAPE ABUTMENT ;
    NETEXPR "VDD VDD!" ;
    PORT
      LAYER met1 ;
        RECT 0 3.94 1.84 4.34 ;
    END
  END VDD
  PIN VSS
    DIRECTION INPUT ;
    USE GROUND ;
    SHAPE ABUTMENT ;
    NETEXPR "VSS VSS!" ;
    PORT
      LAYER met1 ;
        RECT 0 -0.2 1.84 0.2 ;
    END
  END VSS
  PIN Y
    DIRECTION OUTPUT ;
    USE SIGNAL ;
    PORT
      LAYER met1 ;
        RECT 1.035 2.84 1.51 3.49 ;
        RECT 1.25 0.605 1.51 3.49 ;
        RECT 1.035 0.605 1.51 0.895 ;
    END
  END Y
END INVX1_LP

MACRO INVX2_LP
  CLASS CORE ;
  ORIGIN 0 0 ;
  FOREIGN INVX2_LP 0 0 ;
  SIZE 2.3 BY 4.14 ;
  SYMMETRY X Y ;
  SITE CoreSite ;
  PIN A
    DIRECTION INPUT ;
    USE SIGNAL ;
    PORT
      LAYER met1 ;
        RECT 0.79 1.29 1.05 2.53 ;
    END
  END A
  PIN VDD
    DIRECTION INPUT ;
    USE POWER ;
    SHAPE ABUTMENT ;
    NETEXPR "VDD VDD!" ;
    PORT
      LAYER met1 ;
        RECT 0 3.94 2.3 4.34 ;
    END
  END VDD
  PIN VSS
    DIRECTION INPUT ;
    USE GROUND ;
    SHAPE ABUTMENT ;
    NETEXPR "VSS VSS!" ;
    PORT
      LAYER met1 ;
        RECT 0 -0.2 2.3 0.2 ;
    END
  END VSS
  PIN Y
    DIRECTION OUTPUT ;
    USE SIGNAL ;
    PORT
      LAYER met1 ;
        RECT 1.035 2.735 1.51 3.385 ;
        RECT 1.25 0.61 1.51 3.385 ;
        RECT 1.035 0.61 1.51 0.9 ;
    END
  END Y
  PROPERTY CatenaDesignType "deviceLevel" ;
END INVX2_LP

MACRO INVX4_LP
  CLASS CORE ;
  ORIGIN 0 0 ;
  FOREIGN INVX4_LP 0 0 ;
  SIZE 2.3 BY 4.14 ;
  SYMMETRY X Y ;
  SITE CoreSite ;
  PIN A
    DIRECTION INPUT ;
    USE SIGNAL ;
    PORT
      LAYER met1 ;
        RECT 0.79 1.29 1.05 2.53 ;
    END
  END A
  PIN VDD
    DIRECTION INPUT ;
    USE POWER ;
    SHAPE ABUTMENT ;
    NETEXPR "VDD VDD!" ;
    PORT
      LAYER met1 ;
        RECT 0 3.94 2.3 4.34 ;
    END
  END VDD
  PIN VSS
    DIRECTION INPUT ;
    USE GROUND ;
    SHAPE ABUTMENT ;
    NETEXPR "VSS VSS!" ;
    PORT
      LAYER met1 ;
        RECT 0 -0.2 2.3 0.2 ;
    END
  END VSS
  PIN Y
    DIRECTION OUTPUT ;
    USE SIGNAL ;
    PORT
      LAYER met1 ;
        RECT 1.035 2.735 1.51 3.385 ;
        RECT 1.25 0.61 1.51 3.385 ;
        RECT 1.035 0.61 1.51 0.9 ;
    END
  END Y
  PROPERTY CatenaDesignType "deviceLevel" ;
END INVX4_LP

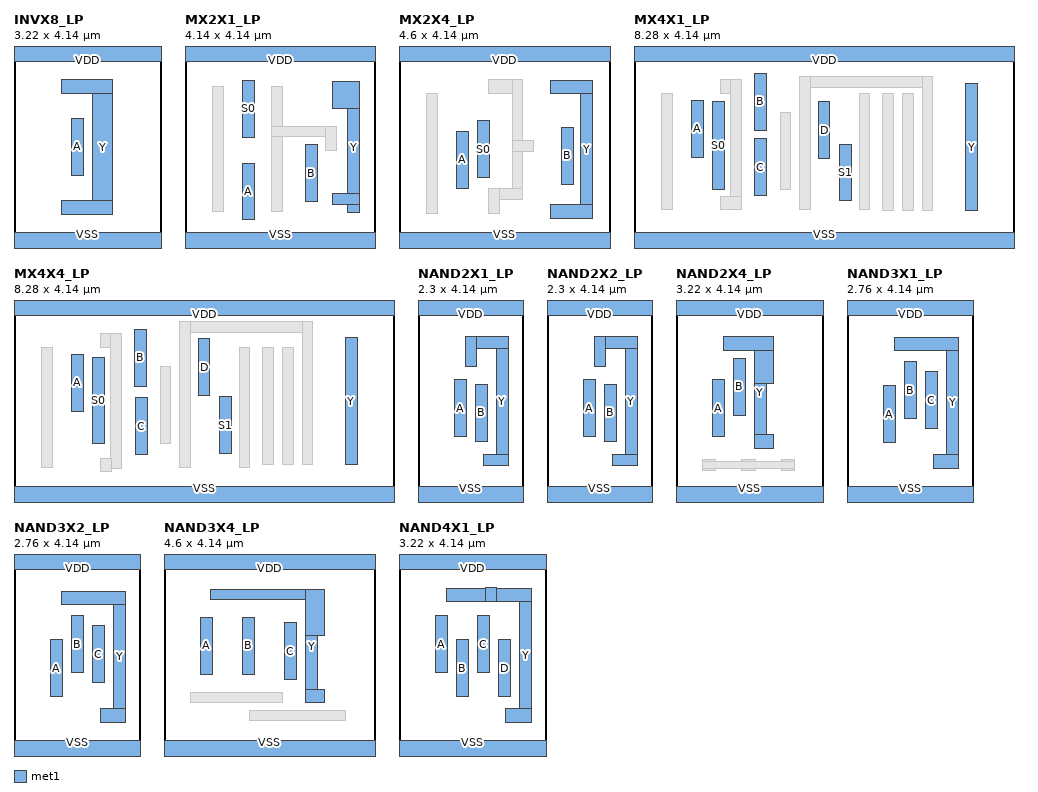
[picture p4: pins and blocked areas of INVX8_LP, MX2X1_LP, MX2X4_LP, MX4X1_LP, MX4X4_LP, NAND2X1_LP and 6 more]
MACRO INVX8_LP
  CLASS CORE ;
  ORIGIN 0 0 ;
  FOREIGN INVX8_LP 0 0 ;
  SIZE 3.22 BY 4.14 ;
  SYMMETRY X Y ;
  SITE CoreSite ;
  PIN A
    DIRECTION INPUT ;
    USE SIGNAL ;
    PORT
      LAYER met1 ;
        RECT 1.25 1.455 1.51 2.695 ;
    END
  END A
  PIN VDD
    DIRECTION INPUT ;
    USE POWER ;
    SHAPE ABUTMENT ;
    NETEXPR "VDD VDD!" ;
    PORT
      LAYER met1 ;
        RECT 0 3.94 3.22 4.34 ;
    END
  END VDD
  PIN VSS
    DIRECTION INPUT ;
    USE GROUND ;
    SHAPE ABUTMENT ;
    NETEXPR "VSS VSS!" ;
    PORT
      LAYER met1 ;
        RECT 0 -0.2 3.22 0.2 ;
    END
  END VSS
  PIN Y
    DIRECTION OUTPUT ;
    USE SIGNAL ;
    PORT
      LAYER met1 ;
        RECT 1.035 3.24 2.155 3.53 ;
        RECT 1.71 0.61 2.155 3.53 ;
        RECT 1.035 0.61 2.155 0.9 ;
    END
  END Y
  PROPERTY CatenaDesignType "deviceLevel" ;
END INVX8_LP

MACRO MX2X1_LP
  CLASS CORE ;
  ORIGIN 0 0 ;
  FOREIGN MX2X1_LP 0 0 ;
  SIZE 4.14 BY 4.14 ;
  SYMMETRY X Y ;
  SITE CoreSite ;
  PIN A
    DIRECTION INPUT ;
    USE SIGNAL ;
    PORT
      LAYER met1 ;
        RECT 1.25 0.48 1.51 1.72 ;
    END
  END A
  PIN B
    DIRECTION INPUT ;
    USE SIGNAL ;
    PORT
      LAYER met1 ;
        RECT 2.63 0.875 2.89 2.115 ;
    END
  END B
  PIN S0
    DIRECTION INPUT ;
    USE SIGNAL ;
    PORT
      LAYER met1 ;
        RECT 1.25 2.28 1.51 3.52 ;
    END
  END S0
  PIN VDD
    DIRECTION INPUT ;
    USE POWER ;
    SHAPE ABUTMENT ;
    NETEXPR "VDD VDD!" ;
    PORT
      LAYER met1 ;
        RECT 0 3.94 4.14 4.34 ;
    END
  END VDD
  PIN VSS
    DIRECTION INPUT ;
    USE GROUND ;
    SHAPE ABUTMENT ;
    NETEXPR "VSS VSS!" ;
    PORT
      LAYER met1 ;
        RECT 0 -0.2 4.14 0.2 ;
    END
  END VSS
  PIN Y
    DIRECTION OUTPUT ;
    USE SIGNAL ;
    PORT
      LAYER met1 ;
        RECT 3.215 2.91 3.81 3.5 ;
        RECT 3.55 0.64 3.81 3.5 ;
        RECT 3.215 0.82 3.81 1.05 ;
    END
  END Y
  OBS
    LAYER met1 ;
      RECT 1.895 0.655 2.125 3.38 ;
      RECT 1.895 2.29 3.3 2.52 ;
      RECT 3.07 2 3.3 2.52 ;
      RECT 0.605 0.655 0.835 3.38 ;
  END
  PROPERTY CatenaDesignType "deviceLevel" ;
  PROPERTY oaTaper "virtuosoDefaultSetup" ;
END MX2X1_LP

MACRO MX2X4_LP
  CLASS CORE ;
  ORIGIN 0 0 ;
  FOREIGN MX2X4_LP 0 0 ;
  SIZE 4.6 BY 4.14 ;
  SYMMETRY X Y ;
  SITE CoreSite ;
  PIN A
    DIRECTION INPUT ;
    USE SIGNAL ;
    PORT
      LAYER met1 ;
        RECT 1.25 1.175 1.51 2.415 ;
    END
  END A
  PIN B
    DIRECTION INPUT ;
    USE SIGNAL ;
    PORT
      LAYER met1 ;
        RECT 3.55 1.255 3.81 2.495 ;
    END
  END B
  PIN S0
    DIRECTION INPUT ;
    USE SIGNAL ;
    PORT
      LAYER met1 ;
        RECT 1.71 1.405 1.97 2.645 ;
    END
  END S0
  PIN VDD
    DIRECTION INPUT ;
    USE POWER ;
    SHAPE ABUTMENT ;
    NETEXPR "VDD VDD!" ;
    PORT
      LAYER met1 ;
        RECT 0 3.94 4.6 4.34 ;
    END
  END VDD
  PIN VSS
    DIRECTION INPUT ;
    USE GROUND ;
    SHAPE ABUTMENT ;
    NETEXPR "VSS VSS!" ;
    PORT
      LAYER met1 ;
        RECT 0 -0.2 4.6 0.2 ;
    END
  END VSS
  PIN Y
    DIRECTION OUTPUT ;
    USE SIGNAL ;
    PORT
      LAYER met1 ;
        RECT 3.305 3.235 4.22 3.525 ;
        RECT 3.96 0.52 4.22 3.525 ;
        RECT 3.305 0.52 4.22 0.81 ;
    END
  END Y
  OBS
    LAYER met1 ;
      RECT 1.955 3.245 2.695 3.535 ;
      RECT 2.465 0.935 2.695 3.535 ;
      RECT 2.465 1.98 2.93 2.21 ;
      RECT 1.955 0.935 2.695 1.165 ;
      RECT 1.955 0.615 2.185 1.165 ;
      RECT 0.605 0.615 0.835 3.235 ;
  END
  PROPERTY CatenaDesignType "deviceLevel" ;
END MX2X4_LP

MACRO MX4X1_LP
  CLASS CORE ;
  ORIGIN 0 0 ;
  FOREIGN MX4X1_LP 0 0 ;
  SIZE 8.28 BY 4.14 ;
  SYMMETRY X Y ;
  SITE CoreSite ;
  PIN A
    DIRECTION INPUT ;
    USE SIGNAL ;
    PORT
      LAYER met1 ;
        RECT 1.25 1.85 1.51 3.09 ;
    END
  END A
  PIN B
    DIRECTION INPUT ;
    USE SIGNAL ;
    PORT
      LAYER met1 ;
        RECT 2.63 2.435 2.89 3.675 ;
    END
  END B
  PIN C
    DIRECTION INPUT ;
    USE SIGNAL ;
    PORT
      LAYER met1 ;
        RECT 2.63 1.005 2.89 2.245 ;
    END
  END C
  PIN D
    DIRECTION INPUT ;
    USE SIGNAL ;
    PORT
      LAYER met1 ;
        RECT 4.01 1.815 4.27 3.055 ;
    END
  END D
  PIN S0
    DIRECTION INPUT ;
    USE SIGNAL ;
    PORT
      LAYER met1 ;
        RECT 1.71 1.15 1.97 3.065 ;
    END
  END S0
  PIN S1
    DIRECTION INPUT ;
    USE SIGNAL ;
    PORT
      LAYER met1 ;
        RECT 4.47 0.895 4.73 2.135 ;
    END
  END S1
  PIN VDD
    DIRECTION INPUT ;
    USE POWER ;
    SHAPE ABUTMENT ;
    NETEXPR "VDD VDD!" ;
    PORT
      LAYER met1 ;
        RECT 0 3.94 8.28 4.34 ;
    END
  END VDD
  PIN VSS
    DIRECTION INPUT ;
    USE GROUND ;
    SHAPE ABUTMENT ;
    NETEXPR "VSS VSS!" ;
    PORT
      LAYER met1 ;
        RECT 0 -0.2 8.28 0.2 ;
    END
  END VSS
  PIN Y
    DIRECTION OUTPUT ;
    USE SIGNAL ;
    PORT
      LAYER met1 ;
        RECT 7.23 0.68 7.49 3.45 ;
    END
  END Y
  OBS
    LAYER met1 ;
      RECT 3.615 3.375 6.515 3.605 ;
      RECT 6.285 0.68 6.515 3.605 ;
      RECT 3.615 0.705 3.845 3.605 ;
      RECT 1.895 3.24 2.34 3.53 ;
      RECT 2.11 0.705 2.34 3.53 ;
      RECT 1.895 0.705 2.34 0.995 ;
      RECT 5.855 0.68 6.085 3.235 ;
      RECT 5.425 0.68 5.655 3.235 ;
      RECT 4.905 0.705 5.135 3.235 ;
      RECT 3.185 1.145 3.415 2.815 ;
      RECT 0.605 0.705 0.835 3.235 ;
  END
  PROPERTY CatenaDesignType "deviceLevel" ;
END MX4X1_LP

MACRO MX4X4_LP
  CLASS CORE ;
  ORIGIN 0 0 ;
  FOREIGN MX4X4_LP 0 0 ;
  SIZE 8.28 BY 4.14 ;
  SYMMETRY X Y ;
  SITE CoreSite ;
  PIN A
    DIRECTION INPUT ;
    USE SIGNAL ;
    PORT
      LAYER met1 ;
        RECT 1.25 1.85 1.51 3.09 ;
    END
  END A
  PIN B
    DIRECTION INPUT ;
    USE SIGNAL ;
    PORT
      LAYER met1 ;
        RECT 2.63 2.39 2.89 3.63 ;
    END
  END B
  PIN C
    DIRECTION INPUT ;
    USE SIGNAL ;
    PORT
      LAYER met1 ;
        RECT 2.65 0.905 2.91 2.145 ;
    END
  END C
  PIN D
    DIRECTION INPUT ;
    USE SIGNAL ;
    PORT
      LAYER met1 ;
        RECT 4.01 2.19 4.27 3.43 ;
    END
  END D
  PIN S0
    DIRECTION INPUT ;
    USE SIGNAL ;
    PORT
      LAYER met1 ;
        RECT 1.71 1.145 1.97 3.01 ;
    END
  END S0
  PIN S1
    DIRECTION INPUT ;
    USE SIGNAL ;
    PORT
      LAYER met1 ;
        RECT 4.47 0.925 4.73 2.165 ;
    END
  END S1
  PIN VDD
    DIRECTION INPUT ;
    USE POWER ;
    SHAPE ABUTMENT ;
    NETEXPR "VDD VDD!" ;
    PORT
      LAYER met1 ;
        RECT 0 3.94 8.28 4.34 ;
    END
  END VDD
  PIN VSS
    DIRECTION INPUT ;
    USE GROUND ;
    SHAPE ABUTMENT ;
    NETEXPR "VSS VSS!" ;
    PORT
      LAYER met1 ;
        RECT 0 -0.2 8.28 0.2 ;
    END
  END VSS
  PIN Y
    DIRECTION OUTPUT ;
    USE SIGNAL ;
    PORT
      LAYER met1 ;
        RECT 7.22 0.68 7.48 3.45 ;
    END
  END Y
  OBS
    LAYER met1 ;
      RECT 3.615 3.57 6.515 3.8 ;
      RECT 6.285 0.68 6.515 3.8 ;
      RECT 3.615 0.63 3.845 3.8 ;
      RECT 1.895 3.24 2.34 3.53 ;
      RECT 2.11 0.61 2.34 3.53 ;
      RECT 1.895 0.535 2.125 0.825 ;
      RECT 5.855 0.68 6.085 3.235 ;
      RECT 5.425 0.68 5.655 3.235 ;
      RECT 4.905 0.63 5.135 3.235 ;
      RECT 3.185 1.145 3.415 2.815 ;
      RECT 0.605 0.63 0.835 3.235 ;
  END
  PROPERTY CatenaDesignType "deviceLevel" ;
END MX4X4_LP

MACRO NAND2X1_LP
  CLASS CORE ;
  ORIGIN 0 0 ;
  FOREIGN NAND2X1_LP 0 0 ;
  SIZE 2.3 BY 4.14 ;
  SYMMETRY X Y ;
  SITE CoreSite ;
  PIN A
    DIRECTION INPUT ;
    USE SIGNAL ;
    PORT
      LAYER met1 ;
        RECT 0.79 1.29 1.05 2.53 ;
    END
  END A
  PIN B
    DIRECTION INPUT ;
    USE SIGNAL ;
    PORT
      LAYER met1 ;
        RECT 1.25 1.19 1.51 2.43 ;
    END
  END B
  PIN VDD
    DIRECTION INPUT ;
    USE POWER ;
    SHAPE ABUTMENT ;
    NETEXPR "VDD VDD!" ;
    PORT
      LAYER met1 ;
        RECT 0 3.94 2.3 4.34 ;
    END
  END VDD
  PIN VSS
    DIRECTION INPUT ;
    USE GROUND ;
    SHAPE ABUTMENT ;
    NETEXPR "VSS VSS!" ;
    PORT
      LAYER met1 ;
        RECT 0 -0.2 2.3 0.2 ;
    END
  END VSS
  PIN Y
    DIRECTION OUTPUT ;
    USE SIGNAL ;
    PORT
      LAYER met1 ;
        RECT 1.035 3.21 1.97 3.47 ;
        RECT 1.71 0.655 1.97 3.47 ;
        RECT 1.435 0.655 1.97 0.915 ;
        RECT 1.035 2.82 1.265 3.47 ;
    END
  END Y
  PROPERTY CatenaDesignType "deviceLevel" ;
END NAND2X1_LP

MACRO NAND2X2_LP
  CLASS CORE ;
  ORIGIN 0 0 ;
  FOREIGN NAND2X2_LP 0 0 ;
  SIZE 2.3 BY 4.14 ;
  SYMMETRY X Y ;
  SITE CoreSite ;
  PIN A
    DIRECTION INPUT ;
    USE SIGNAL ;
    PORT
      LAYER met1 ;
        RECT 0.79 1.29 1.05 2.53 ;
    END
  END A
  PIN B
    DIRECTION INPUT ;
    USE SIGNAL ;
    PORT
      LAYER met1 ;
        RECT 1.25 1.19 1.51 2.43 ;
    END
  END B
  PIN VDD
    DIRECTION INPUT ;
    USE POWER ;
    SHAPE ABUTMENT ;
    NETEXPR "VDD VDD!" ;
    PORT
      LAYER met1 ;
        RECT 0 3.94 2.3 4.34 ;
    END
  END VDD
  PIN VSS
    DIRECTION INPUT ;
    USE GROUND ;
    SHAPE ABUTMENT ;
    NETEXPR "VSS VSS!" ;
    PORT
      LAYER met1 ;
        RECT 0 -0.2 2.3 0.2 ;
    END
  END VSS
  PIN Y
    DIRECTION OUTPUT ;
    USE SIGNAL ;
    PORT
      LAYER met1 ;
        RECT 1.035 3.21 1.97 3.47 ;
        RECT 1.71 0.655 1.97 3.47 ;
        RECT 1.435 0.655 1.97 0.915 ;
        RECT 1.035 2.82 1.265 3.47 ;
    END
  END Y
  PROPERTY CatenaDesignType "deviceLevel" ;
END NAND2X2_LP

MACRO NAND2X4_LP
  CLASS CORE ;
  ORIGIN 0 0 ;
  FOREIGN NAND2X4_LP 0 0 ;
  SIZE 3.22 BY 4.14 ;
  SYMMETRY X Y ;
  SITE CoreSite ;
  PIN A
    DIRECTION INPUT ;
    USE SIGNAL ;
    PORT
      LAYER met1 ;
        RECT 0.79 1.29 1.05 2.53 ;
    END
  END A
  PIN B
    DIRECTION INPUT ;
    USE SIGNAL ;
    PORT
      LAYER met1 ;
        RECT 1.25 1.76 1.51 3 ;
    END
  END B
  PIN VDD
    DIRECTION INPUT ;
    USE POWER ;
    SHAPE ABUTMENT ;
    NETEXPR "VDD VDD!" ;
    PORT
      LAYER met1 ;
        RECT 0 3.94 3.22 4.34 ;
    END
  END VDD
  PIN VSS
    DIRECTION INPUT ;
    USE GROUND ;
    SHAPE ABUTMENT ;
    NETEXPR "VSS VSS!" ;
    PORT
      LAYER met1 ;
        RECT 0 -0.2 3.22 0.2 ;
    END
  END VSS
  PIN Y
    DIRECTION OUTPUT ;
    USE SIGNAL ;
    PORT
      LAYER met1 ;
        RECT 1.035 3.18 2.125 3.47 ;
        RECT 1.71 2.46 2.125 3.47 ;
        RECT 1.71 1.04 2.125 1.33 ;
        RECT 1.71 1.04 1.97 3.47 ;
    END
  END Y
  OBS
    LAYER met1 ;
      RECT 2.295 0.56 2.585 0.79 ;
      RECT 1.435 0.56 1.725 0.79 ;
      RECT 0.575 0.56 0.865 0.79 ;
      RECT 0.575 0.59 2.585 0.76 ;
  END
  PROPERTY CatenaDesignType "deviceLevel" ;
END NAND2X4_LP

MACRO NAND3X1_LP
  CLASS CORE ;
  ORIGIN 0 0 ;
  FOREIGN NAND3X1_LP 0 0 ;
  SIZE 2.76 BY 4.14 ;
  SYMMETRY X Y ;
  SITE CoreSite ;
  PIN A
    DIRECTION INPUT ;
    USE SIGNAL ;
    PORT
      LAYER met1 ;
        RECT 0.79 1.165 1.05 2.405 ;
    END
  END A
  PIN B
    DIRECTION INPUT ;
    USE SIGNAL ;
    PORT
      LAYER met1 ;
        RECT 1.25 1.685 1.51 2.925 ;
    END
  END B
  PIN C
    DIRECTION INPUT ;
    USE SIGNAL ;
    PORT
      LAYER met1 ;
        RECT 1.71 1.47 1.97 2.71 ;
    END
  END C
  PIN VDD
    DIRECTION INPUT ;
    USE POWER ;
    SHAPE ABUTMENT ;
    NETEXPR "VDD VDD!" ;
    PORT
      LAYER met1 ;
        RECT 0 3.94 2.76 4.34 ;
    END
  END VDD
  PIN VSS
    DIRECTION INPUT ;
    USE GROUND ;
    SHAPE ABUTMENT ;
    NETEXPR "VSS VSS!" ;
    PORT
      LAYER met1 ;
        RECT 0 -0.2 2.76 0.2 ;
    END
  END VSS
  PIN Y
    DIRECTION OUTPUT ;
    USE SIGNAL ;
    PORT
      LAYER met1 ;
        RECT 1.035 3.16 2.43 3.45 ;
        RECT 2.17 0.61 2.43 3.45 ;
        RECT 1.895 0.61 2.43 0.9 ;
    END
  END Y
  PROPERTY CatenaDesignType "deviceLevel" ;
END NAND3X1_LP

MACRO NAND3X2_LP
  CLASS CORE ;
  ORIGIN 0 0 ;
  FOREIGN NAND3X2_LP 0 0 ;
  SIZE 2.76 BY 4.14 ;
  SYMMETRY X Y ;
  SITE CoreSite ;
  PIN A
    DIRECTION INPUT ;
    USE SIGNAL ;
    PORT
      LAYER met1 ;
        RECT 0.79 1.165 1.05 2.405 ;
    END
  END A
  PIN B
    DIRECTION INPUT ;
    USE SIGNAL ;
    PORT
      LAYER met1 ;
        RECT 1.25 1.685 1.51 2.925 ;
    END
  END B
  PIN C
    DIRECTION INPUT ;
    USE SIGNAL ;
    PORT
      LAYER met1 ;
        RECT 1.71 1.47 1.97 2.71 ;
    END
  END C
  PIN VDD
    DIRECTION INPUT ;
    USE POWER ;
    SHAPE ABUTMENT ;
    NETEXPR "VDD VDD!" ;
    PORT
      LAYER met1 ;
        RECT 0 3.94 2.76 4.34 ;
    END
  END VDD
  PIN VSS
    DIRECTION INPUT ;
    USE GROUND ;
    SHAPE ABUTMENT ;
    NETEXPR "VSS VSS!" ;
    PORT
      LAYER met1 ;
        RECT 0 -0.2 2.76 0.2 ;
    END
  END VSS
  PIN Y
    DIRECTION OUTPUT ;
    USE SIGNAL ;
    PORT
      LAYER met1 ;
        RECT 1.035 3.16 2.43 3.45 ;
        RECT 2.17 0.61 2.43 3.45 ;
        RECT 1.895 0.61 2.43 0.9 ;
    END
  END Y
  PROPERTY CatenaDesignType "deviceLevel" ;
END NAND3X2_LP

MACRO NAND3X4_LP
  CLASS CORE ;
  ORIGIN 0 0 ;
  FOREIGN NAND3X4_LP 0 0 ;
  SIZE 4.6 BY 4.14 ;
  SYMMETRY X Y ;
  SITE CoreSite ;
  PIN A
    DIRECTION INPUT ;
    USE SIGNAL ;
    PORT
      LAYER met1 ;
        RECT 0.79 1.65 1.05 2.89 ;
    END
  END A
  PIN B
    DIRECTION INPUT ;
    USE SIGNAL ;
    PORT
      LAYER met1 ;
        RECT 1.71 1.65 1.97 2.89 ;
    END
  END B
  PIN C
    DIRECTION INPUT ;
    USE SIGNAL ;
    PORT
      LAYER met1 ;
        RECT 2.63 1.53 2.89 2.77 ;
    END
  END C
  PIN VDD
    DIRECTION INPUT ;
    USE POWER ;
    SHAPE ABUTMENT ;
    NETEXPR "VDD VDD!" ;
    PORT
      LAYER met1 ;
        RECT 0 3.94 4.6 4.34 ;
    END
  END VDD
  PIN VSS
    DIRECTION INPUT ;
    USE GROUND ;
    SHAPE ABUTMENT ;
    NETEXPR "VSS VSS!" ;
    PORT
      LAYER met1 ;
        RECT 0 -0.2 4.6 0.2 ;
    END
  END VSS
  PIN Y
    DIRECTION OUTPUT ;
    USE SIGNAL ;
    PORT
      LAYER met1 ;
        RECT 1.005 3.27 3.505 3.5 ;
        RECT 3.09 2.49 3.505 3.5 ;
        RECT 3.09 1.025 3.505 1.315 ;
        RECT 3.09 1.025 3.35 3.5 ;
    END
  END Y
  OBS
    LAYER met1 ;
      RECT 1.865 0.64 3.965 0.87 ;
      RECT 0.575 1.025 2.585 1.255 ;
  END
  PROPERTY CatenaDesignType "deviceLevel" ;
END NAND3X4_LP

MACRO NAND4X1_LP
  CLASS CORE ;
  ORIGIN 0 0 ;
  FOREIGN NAND4X1_LP 0 0 ;
  SIZE 3.22 BY 4.14 ;
  SYMMETRY X Y ;
  SITE CoreSite ;
  PIN A
    DIRECTION INPUT ;
    USE SIGNAL ;
    PORT
      LAYER met1 ;
        RECT 0.79 1.685 1.05 2.925 ;
    END
  END A
  PIN B
    DIRECTION INPUT ;
    USE SIGNAL ;
    PORT
      LAYER met1 ;
        RECT 1.25 1.165 1.51 2.405 ;
    END
  END B
  PIN C
    DIRECTION INPUT ;
    USE SIGNAL ;
    PORT
      LAYER met1 ;
        RECT 1.71 1.685 1.97 2.925 ;
    END
  END C
  PIN D
    DIRECTION INPUT ;
    USE SIGNAL ;
    PORT
      LAYER met1 ;
        RECT 2.17 1.165 2.43 2.405 ;
    END
  END D
  PIN VDD
    DIRECTION INPUT ;
    USE POWER ;
    SHAPE ABUTMENT ;
    NETEXPR "VDD VDD!" ;
    PORT
      LAYER met1 ;
        RECT 0 3.94 3.22 4.34 ;
    END
  END VDD
  PIN VSS
    DIRECTION INPUT ;
    USE GROUND ;
    SHAPE ABUTMENT ;
    NETEXPR "VSS VSS!" ;
    PORT
      LAYER met1 ;
        RECT 0 -0.2 3.22 0.2 ;
    END
  END VSS
  PIN Y
    DIRECTION OUTPUT ;
    USE SIGNAL ;
    PORT
      LAYER met1 ;
        RECT 1.035 3.23 2.89 3.52 ;
        RECT 2.63 0.61 2.89 3.52 ;
        RECT 2.325 0.61 2.89 0.9 ;
        RECT 1.895 3.23 2.125 3.53 ;
    END
  END Y
  PROPERTY CatenaDesignType "deviceLevel" ;
END NAND4X1_LP

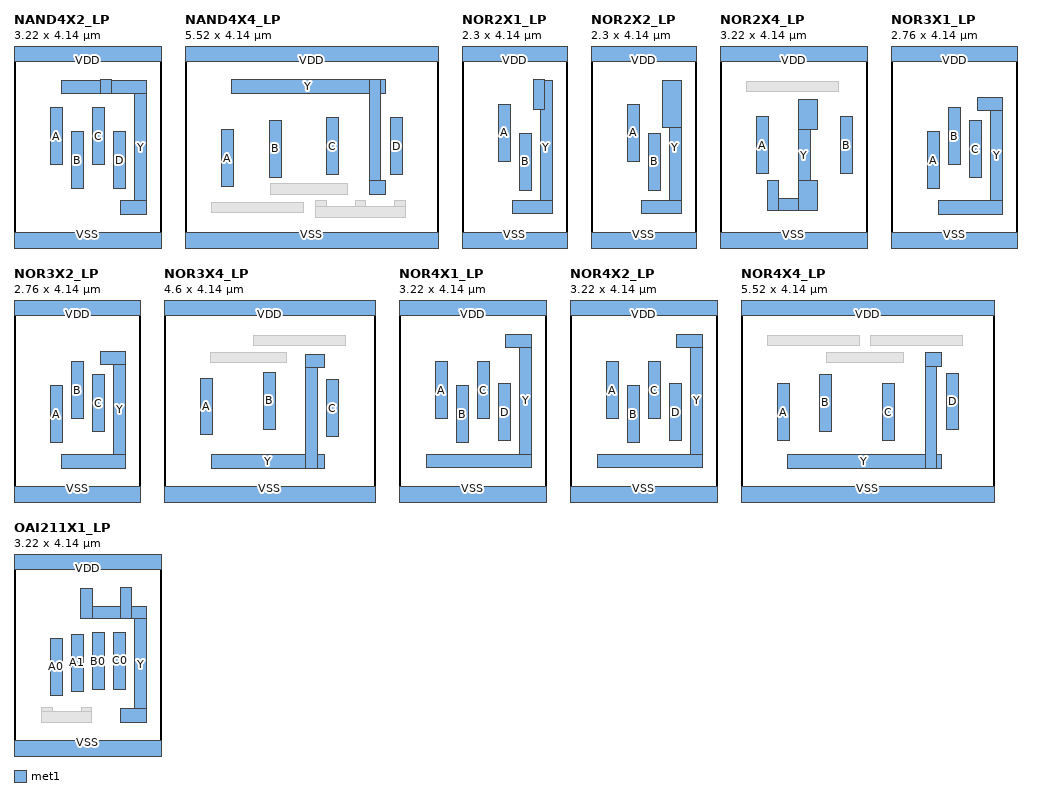
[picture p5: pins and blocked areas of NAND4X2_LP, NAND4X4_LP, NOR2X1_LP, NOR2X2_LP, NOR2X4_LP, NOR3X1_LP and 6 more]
MACRO NAND4X2_LP
  CLASS CORE ;
  ORIGIN 0 0 ;
  FOREIGN NAND4X2_LP 0 0 ;
  SIZE 3.22 BY 4.14 ;
  SYMMETRY X Y ;
  SITE CoreSite ;
  PIN A
    DIRECTION INPUT ;
    USE SIGNAL ;
    PORT
      LAYER met1 ;
        RECT 0.79 1.685 1.05 2.925 ;
    END
  END A
  PIN B
    DIRECTION INPUT ;
    USE SIGNAL ;
    PORT
      LAYER met1 ;
        RECT 1.25 1.165 1.51 2.405 ;
    END
  END B
  PIN C
    DIRECTION INPUT ;
    USE SIGNAL ;
    PORT
      LAYER met1 ;
        RECT 1.71 1.685 1.97 2.925 ;
    END
  END C
  PIN D
    DIRECTION INPUT ;
    USE SIGNAL ;
    PORT
      LAYER met1 ;
        RECT 2.17 1.165 2.43 2.405 ;
    END
  END D
  PIN VDD
    DIRECTION INPUT ;
    USE POWER ;
    SHAPE ABUTMENT ;
    NETEXPR "VDD VDD!" ;
    PORT
      LAYER met1 ;
        RECT 0 3.94 3.22 4.34 ;
    END
  END VDD
  PIN VSS
    DIRECTION INPUT ;
    USE GROUND ;
    SHAPE ABUTMENT ;
    NETEXPR "VSS VSS!" ;
    PORT
      LAYER met1 ;
        RECT 0 -0.2 3.22 0.2 ;
    END
  END VSS
  PIN Y
    DIRECTION OUTPUT ;
    USE SIGNAL ;
    PORT
      LAYER met1 ;
        RECT 1.035 3.23 2.89 3.52 ;
        RECT 2.63 0.61 2.89 3.52 ;
        RECT 2.325 0.61 2.89 0.9 ;
        RECT 1.895 3.23 2.125 3.53 ;
    END
  END Y
  PROPERTY CatenaDesignType "deviceLevel" ;
END NAND4X2_LP

MACRO NAND4X4_LP
  CLASS CORE ;
  ORIGIN 0 0 ;
  FOREIGN NAND4X4_LP 0 0 ;
  SIZE 5.52 BY 4.14 ;
  SYMMETRY X Y ;
  SITE CoreSite ;
  PIN A
    DIRECTION INPUT ;
    USE SIGNAL ;
    PORT
      LAYER met1 ;
        RECT 0.79 1.205 1.05 2.445 ;
    END
  END A
  PIN B
    DIRECTION INPUT ;
    USE SIGNAL ;
    PORT
      LAYER met1 ;
        RECT 1.845 1.415 2.105 2.655 ;
    END
  END B
  PIN C
    DIRECTION INPUT ;
    USE SIGNAL ;
    PORT
      LAYER met1 ;
        RECT 3.09 1.47 3.35 2.71 ;
    END
  END C
  PIN D
    DIRECTION INPUT ;
    USE SIGNAL ;
    PORT
      LAYER met1 ;
        RECT 4.47 1.47 4.73 2.71 ;
    END
  END D
  PIN VDD
    DIRECTION INPUT ;
    USE POWER ;
    SHAPE ABUTMENT ;
    NETEXPR "VDD VDD!" ;
    PORT
      LAYER met1 ;
        RECT 0 3.94 5.52 4.34 ;
    END
  END VDD
  PIN VSS
    DIRECTION INPUT ;
    USE GROUND ;
    SHAPE ABUTMENT ;
    NETEXPR "VSS VSS!" ;
    PORT
      LAYER met1 ;
        RECT 0 -0.2 5.52 0.2 ;
    END
  END VSS
  PIN Y
    DIRECTION OUTPUT ;
    USE SIGNAL ;
    PORT
      LAYER met1 ;
        RECT 1.005 3.24 4.365 3.53 ;
        RECT 4.01 1.04 4.365 1.33 ;
        RECT 4.01 1.04 4.27 3.53 ;
    END
  END Y
  OBS
    LAYER met1 ;
      RECT 4.565 0.535 4.795 0.9 ;
      RECT 3.705 0.535 3.935 0.9 ;
      RECT 2.845 0.535 3.075 0.9 ;
      RECT 2.845 0.535 4.795 0.765 ;
      RECT 1.865 1.04 3.535 1.27 ;
      RECT 0.575 0.64 2.585 0.87 ;
  END
  PROPERTY CatenaDesignType "deviceLevel" ;
END NAND4X4_LP

MACRO NOR2X1_LP
  CLASS CORE ;
  ORIGIN 0 0 ;
  FOREIGN NOR2X1_LP 0 0 ;
  SIZE 2.3 BY 4.14 ;
  SYMMETRY X Y ;
  SITE CoreSite ;
  PIN A
    DIRECTION INPUT ;
    USE SIGNAL ;
    PORT
      LAYER met1 ;
        RECT 0.79 1.76 1.05 3 ;
    END
  END A
  PIN B
    DIRECTION INPUT ;
    USE SIGNAL ;
    PORT
      LAYER met1 ;
        RECT 1.25 1.125 1.51 2.365 ;
    END
  END B
  PIN VDD
    DIRECTION INPUT ;
    USE POWER ;
    SHAPE ABUTMENT ;
    NETEXPR "VDD VDD!" ;
    PORT
      LAYER met1 ;
        RECT 0 3.94 2.3 4.34 ;
    END
  END VDD
  PIN VSS
    DIRECTION INPUT ;
    USE GROUND ;
    SHAPE ABUTMENT ;
    NETEXPR "VSS VSS!" ;
    PORT
      LAYER met1 ;
        RECT 0 -0.2 2.3 0.2 ;
    END
  END VSS
  PIN Y
    DIRECTION OUTPUT ;
    USE SIGNAL ;
    PORT
      LAYER met1 ;
        RECT 1.71 0.62 1.97 3.51 ;
        RECT 1.565 2.89 1.795 3.54 ;
        RECT 1.095 0.62 1.97 0.91 ;
    END
  END Y
  PROPERTY CatenaDesignType "deviceLevel" ;
END NOR2X1_LP

MACRO NOR2X2_LP
  CLASS CORE ;
  ORIGIN 0 0 ;
  FOREIGN NOR2X2_LP 0 0 ;
  SIZE 2.3 BY 4.14 ;
  SYMMETRY X Y ;
  SITE CoreSite ;
  PIN A
    DIRECTION INPUT ;
    USE SIGNAL ;
    PORT
      LAYER met1 ;
        RECT 0.79 1.76 1.05 3 ;
    END
  END A
  PIN B
    DIRECTION INPUT ;
    USE SIGNAL ;
    PORT
      LAYER met1 ;
        RECT 1.25 1.125 1.51 2.365 ;
    END
  END B
  PIN VDD
    DIRECTION INPUT ;
    USE POWER ;
    SHAPE ABUTMENT ;
    NETEXPR "VDD VDD!" ;
    PORT
      LAYER met1 ;
        RECT 0 3.94 2.3 4.34 ;
    END
  END VDD
  PIN VSS
    DIRECTION INPUT ;
    USE GROUND ;
    SHAPE ABUTMENT ;
    NETEXPR "VSS VSS!" ;
    PORT
      LAYER met1 ;
        RECT 0 -0.2 2.3 0.2 ;
    END
  END VSS
  PIN Y
    DIRECTION OUTPUT ;
    USE SIGNAL ;
    PORT
      LAYER met1 ;
        RECT 1.565 2.5 1.97 3.51 ;
        RECT 1.71 0.62 1.97 3.51 ;
        RECT 1.095 0.62 1.97 0.91 ;
    END
  END Y
  PROPERTY CatenaDesignType "deviceLevel" ;
END NOR2X2_LP

MACRO NOR2X4_LP
  CLASS CORE ;
  ORIGIN 0 0 ;
  FOREIGN NOR2X4_LP 0 0 ;
  SIZE 3.22 BY 4.14 ;
  SYMMETRY X Y ;
  SITE CoreSite ;
  PIN A
    DIRECTION INPUT ;
    USE SIGNAL ;
    PORT
      LAYER met1 ;
        RECT 0.79 1.49 1.05 2.73 ;
    END
  END A
  PIN B
    DIRECTION INPUT ;
    USE SIGNAL ;
    PORT
      LAYER met1 ;
        RECT 2.63 1.49 2.89 2.73 ;
    END
  END B
  PIN VDD
    DIRECTION INPUT ;
    USE POWER ;
    SHAPE ABUTMENT ;
    NETEXPR "VDD VDD!" ;
    PORT
      LAYER met1 ;
        RECT 0 3.94 3.22 4.34 ;
    END
  END VDD
  PIN VSS
    DIRECTION INPUT ;
    USE GROUND ;
    SHAPE ABUTMENT ;
    NETEXPR "VSS VSS!" ;
    PORT
      LAYER met1 ;
        RECT 0 -0.2 3.22 0.2 ;
    END
  END VSS
  PIN Y
    DIRECTION OUTPUT ;
    USE SIGNAL ;
    PORT
      LAYER met1 ;
        RECT 1.71 2.445 2.125 3.095 ;
        RECT 1.71 0.68 2.125 1.33 ;
        RECT 1.71 0.68 1.97 3.095 ;
        RECT 1.035 0.68 2.125 0.94 ;
        RECT 1.035 0.68 1.265 1.33 ;
    END
  END Y
  OBS
    LAYER met1 ;
      RECT 0.57 3.27 2.585 3.5 ;
  END
  PROPERTY CatenaDesignType "deviceLevel" ;
END NOR2X4_LP

MACRO NOR3X1_LP
  CLASS CORE ;
  ORIGIN 0 0 ;
  FOREIGN NOR3X1_LP 0 0 ;
  SIZE 2.76 BY 4.14 ;
  SYMMETRY X Y ;
  SITE CoreSite ;
  PIN A
    DIRECTION INPUT ;
    USE SIGNAL ;
    PORT
      LAYER met1 ;
        RECT 0.79 1.165 1.05 2.405 ;
    END
  END A
  PIN B
    DIRECTION INPUT ;
    USE SIGNAL ;
    PORT
      LAYER met1 ;
        RECT 1.25 1.685 1.51 2.925 ;
    END
  END B
  PIN C
    DIRECTION INPUT ;
    USE SIGNAL ;
    PORT
      LAYER met1 ;
        RECT 1.71 1.4 1.97 2.64 ;
    END
  END C
  PIN VDD
    DIRECTION INPUT ;
    USE POWER ;
    SHAPE ABUTMENT ;
    NETEXPR "VDD VDD!" ;
    PORT
      LAYER met1 ;
        RECT 0 3.94 2.76 4.34 ;
    END
  END VDD
  PIN VSS
    DIRECTION INPUT ;
    USE GROUND ;
    SHAPE ABUTMENT ;
    NETEXPR "VSS VSS!" ;
    PORT
      LAYER met1 ;
        RECT 0 -0.2 2.76 0.2 ;
    END
  END VSS
  PIN Y
    DIRECTION OUTPUT ;
    USE SIGNAL ;
    PORT
      LAYER met1 ;
        RECT 1.895 2.865 2.43 3.155 ;
        RECT 2.17 0.61 2.43 3.155 ;
        RECT 1.035 0.61 2.43 0.9 ;
    END
  END Y
  PROPERTY CatenaDesignType "deviceLevel" ;
END NOR3X1_LP

MACRO NOR3X2_LP
  CLASS CORE ;
  ORIGIN 0 0 ;
  FOREIGN NOR3X2_LP 0 0 ;
  SIZE 2.76 BY 4.14 ;
  SYMMETRY X Y ;
  SITE CoreSite ;
  PIN A
    DIRECTION INPUT ;
    USE SIGNAL ;
    PORT
      LAYER met1 ;
        RECT 0.79 1.165 1.05 2.405 ;
    END
  END A
  PIN B
    DIRECTION INPUT ;
    USE SIGNAL ;
    PORT
      LAYER met1 ;
        RECT 1.25 1.685 1.51 2.925 ;
    END
  END B
  PIN C
    DIRECTION INPUT ;
    USE SIGNAL ;
    PORT
      LAYER met1 ;
        RECT 1.71 1.4 1.97 2.64 ;
    END
  END C
  PIN VDD
    DIRECTION INPUT ;
    USE POWER ;
    SHAPE ABUTMENT ;
    NETEXPR "VDD VDD!" ;
    PORT
      LAYER met1 ;
        RECT 0 3.94 2.76 4.34 ;
    END
  END VDD
  PIN VSS
    DIRECTION INPUT ;
    USE GROUND ;
    SHAPE ABUTMENT ;
    NETEXPR "VSS VSS!" ;
    PORT
      LAYER met1 ;
        RECT 0 -0.2 2.76 0.2 ;
    END
  END VSS
  PIN Y
    DIRECTION OUTPUT ;
    USE SIGNAL ;
    PORT
      LAYER met1 ;
        RECT 1.895 2.865 2.43 3.155 ;
        RECT 2.17 0.61 2.43 3.155 ;
        RECT 1.035 0.61 2.43 0.9 ;
    END
  END Y
  PROPERTY CatenaDesignType "deviceLevel" ;
END NOR3X2_LP

MACRO NOR3X4_LP
  CLASS CORE ;
  ORIGIN 0 0 ;
  FOREIGN NOR3X4_LP 0 0 ;
  SIZE 4.6 BY 4.14 ;
  SYMMETRY X Y ;
  SITE CoreSite ;
  PIN A
    DIRECTION INPUT ;
    USE SIGNAL ;
    PORT
      LAYER met1 ;
        RECT 0.79 1.33 1.05 2.57 ;
    END
  END A
  PIN B
    DIRECTION INPUT ;
    USE SIGNAL ;
    PORT
      LAYER met1 ;
        RECT 2.17 1.455 2.43 2.695 ;
    END
  END B
  PIN C
    DIRECTION INPUT ;
    USE SIGNAL ;
    PORT
      LAYER met1 ;
        RECT 3.55 1.295 3.81 2.535 ;
    END
  END C
  PIN VDD
    DIRECTION INPUT ;
    USE POWER ;
    SHAPE ABUTMENT ;
    NETEXPR "VDD VDD!" ;
    PORT
      LAYER met1 ;
        RECT 0 3.94 4.6 4.34 ;
    END
  END VDD
  PIN VSS
    DIRECTION INPUT ;
    USE GROUND ;
    SHAPE ABUTMENT ;
    NETEXPR "VSS VSS!" ;
    PORT
      LAYER met1 ;
        RECT 0 -0.2 4.6 0.2 ;
    END
  END VSS
  PIN Y
    DIRECTION OUTPUT ;
    USE SIGNAL ;
    PORT
      LAYER met1 ;
        RECT 3.09 2.8 3.505 3.09 ;
        RECT 1.035 0.61 3.505 0.9 ;
        RECT 3.09 0.61 3.35 3.09 ;
    END
  END Y
  OBS
    LAYER met1 ;
      RECT 1.955 3.27 3.965 3.5 ;
      RECT 1.005 2.9 2.675 3.13 ;
  END
  PROPERTY CatenaDesignType "deviceLevel" ;
END NOR3X4_LP

MACRO NOR4X1_LP
  CLASS CORE ;
  ORIGIN 0 0 ;
  FOREIGN NOR4X1_LP 0 0 ;
  SIZE 3.22 BY 4.14 ;
  SYMMETRY X Y ;
  SITE CoreSite ;
  PIN A
    DIRECTION INPUT ;
    USE SIGNAL ;
    PORT
      LAYER met1 ;
        RECT 0.79 1.685 1.05 2.925 ;
    END
  END A
  PIN B
    DIRECTION INPUT ;
    USE SIGNAL ;
    PORT
      LAYER met1 ;
        RECT 1.25 1.165 1.51 2.405 ;
    END
  END B
  PIN C
    DIRECTION INPUT ;
    USE SIGNAL ;
    PORT
      LAYER met1 ;
        RECT 1.71 1.685 1.97 2.925 ;
    END
  END C
  PIN D
    DIRECTION INPUT ;
    USE SIGNAL ;
    PORT
      LAYER met1 ;
        RECT 2.17 1.205 2.43 2.445 ;
    END
  END D
  PIN VDD
    DIRECTION INPUT ;
    USE POWER ;
    SHAPE ABUTMENT ;
    NETEXPR "VDD VDD!" ;
    PORT
      LAYER met1 ;
        RECT 0 3.94 3.22 4.34 ;
    END
  END VDD
  PIN VSS
    DIRECTION INPUT ;
    USE GROUND ;
    SHAPE ABUTMENT ;
    NETEXPR "VSS VSS!" ;
    PORT
      LAYER met1 ;
        RECT 0 -0.2 3.22 0.2 ;
    END
  END VSS
  PIN Y
    DIRECTION OUTPUT ;
    USE SIGNAL ;
    PORT
      LAYER met1 ;
        RECT 2.325 3.235 2.89 3.525 ;
        RECT 2.63 0.625 2.89 3.525 ;
        RECT 0.605 0.625 2.89 0.915 ;
    END
  END Y
  PROPERTY CatenaDesignType "deviceLevel" ;
END NOR4X1_LP

MACRO NOR4X2_LP
  CLASS CORE ;
  ORIGIN 0 0 ;
  FOREIGN NOR4X2_LP 0 0 ;
  SIZE 3.22 BY 4.14 ;
  SYMMETRY X Y ;
  SITE CoreSite ;
  PIN A
    DIRECTION INPUT ;
    USE SIGNAL ;
    PORT
      LAYER met1 ;
        RECT 0.79 1.685 1.05 2.925 ;
    END
  END A
  PIN B
    DIRECTION INPUT ;
    USE SIGNAL ;
    PORT
      LAYER met1 ;
        RECT 1.25 1.165 1.51 2.405 ;
    END
  END B
  PIN C
    DIRECTION INPUT ;
    USE SIGNAL ;
    PORT
      LAYER met1 ;
        RECT 1.71 1.685 1.97 2.925 ;
    END
  END C
  PIN D
    DIRECTION INPUT ;
    USE SIGNAL ;
    PORT
      LAYER met1 ;
        RECT 2.17 1.205 2.43 2.445 ;
    END
  END D
  PIN VDD
    DIRECTION INPUT ;
    USE POWER ;
    SHAPE ABUTMENT ;
    NETEXPR "VDD VDD!" ;
    PORT
      LAYER met1 ;
        RECT 0 3.94 3.22 4.34 ;
    END
  END VDD
  PIN VSS
    DIRECTION INPUT ;
    USE GROUND ;
    SHAPE ABUTMENT ;
    NETEXPR "VSS VSS!" ;
    PORT
      LAYER met1 ;
        RECT 0 -0.2 3.22 0.2 ;
    END
  END VSS
  PIN Y
    DIRECTION OUTPUT ;
    USE SIGNAL ;
    PORT
      LAYER met1 ;
        RECT 2.325 3.235 2.89 3.525 ;
        RECT 2.63 0.625 2.89 3.525 ;
        RECT 0.605 0.625 2.89 0.915 ;
    END
  END Y
  PROPERTY CatenaDesignType "deviceLevel" ;
END NOR4X2_LP

MACRO NOR4X4_LP
  CLASS CORE ;
  ORIGIN 0 0 ;
  FOREIGN NOR4X4_LP 0 0 ;
  SIZE 5.52 BY 4.14 ;
  SYMMETRY X Y ;
  SITE CoreSite ;
  PIN A
    DIRECTION INPUT ;
    USE SIGNAL ;
    PORT
      LAYER met1 ;
        RECT 0.79 1.205 1.05 2.445 ;
    END
  END A
  PIN B
    DIRECTION INPUT ;
    USE SIGNAL ;
    PORT
      LAYER met1 ;
        RECT 1.71 1.415 1.97 2.655 ;
    END
  END B
  PIN C
    DIRECTION INPUT ;
    USE SIGNAL ;
    PORT
      LAYER met1 ;
        RECT 3.09 1.205 3.35 2.445 ;
    END
  END C
  PIN D
    DIRECTION INPUT ;
    USE SIGNAL ;
    PORT
      LAYER met1 ;
        RECT 4.47 1.44 4.73 2.68 ;
    END
  END D
  PIN VDD
    DIRECTION INPUT ;
    USE POWER ;
    SHAPE ABUTMENT ;
    NETEXPR "VDD VDD!" ;
    PORT
      LAYER met1 ;
        RECT 0 3.94 5.52 4.34 ;
    END
  END VDD
  PIN VSS
    DIRECTION INPUT ;
    USE GROUND ;
    SHAPE ABUTMENT ;
    NETEXPR "VSS VSS!" ;
    PORT
      LAYER met1 ;
        RECT 0 -0.2 5.52 0.2 ;
    END
  END VSS
  PIN Y
    DIRECTION OUTPUT ;
    USE SIGNAL ;
    PORT
      LAYER met1 ;
        RECT 4.01 2.83 4.365 3.12 ;
        RECT 1.005 0.61 4.365 0.9 ;
        RECT 4.01 0.61 4.27 3.12 ;
    END
  END Y
  OBS
    LAYER met1 ;
      RECT 2.815 3.27 4.825 3.5 ;
      RECT 1.865 2.9 3.535 3.13 ;
      RECT 0.575 3.27 2.585 3.5 ;
  END
  PROPERTY CatenaDesignType "deviceLevel" ;
END NOR4X4_LP

MACRO OAI211X1_LP
  CLASS CORE ;
  ORIGIN 0 0 ;
  FOREIGN OAI211X1_LP 0 0 ;
  SIZE 3.22 BY 4.14 ;
  SYMMETRY X Y ;
  SITE CoreSite ;
  PIN A0
    DIRECTION INPUT ;
    USE SIGNAL ;
    PORT
      LAYER met1 ;
        RECT 0.79 1.19 1.05 2.43 ;
    END
  END A0
  PIN A1
    DIRECTION INPUT ;
    USE SIGNAL ;
    PORT
      LAYER met1 ;
        RECT 1.25 1.285 1.51 2.525 ;
    END
  END A1
  PIN B0
    DIRECTION INPUT ;
    USE SIGNAL ;
    PORT
      LAYER met1 ;
        RECT 1.71 1.31 1.97 2.55 ;
    END
  END B0
  PIN C0
    DIRECTION INPUT ;
    USE SIGNAL ;
    PORT
      LAYER met1 ;
        RECT 2.17 1.32 2.43 2.56 ;
    END
  END C0
  PIN VDD
    DIRECTION INPUT ;
    USE POWER ;
    SHAPE ABUTMENT ;
    NETEXPR "VDD VDD!" ;
    PORT
      LAYER met1 ;
        RECT 0 3.94 3.22 4.34 ;
    END
  END VDD
  PIN VSS
    DIRECTION INPUT ;
    USE GROUND ;
    SHAPE ABUTMENT ;
    NETEXPR "VSS VSS!" ;
    PORT
      LAYER met1 ;
        RECT 0 -0.2 3.22 0.2 ;
    END
  END VSS
  PIN Y
    DIRECTION OUTPUT ;
    USE SIGNAL ;
    PORT
      LAYER met1 ;
        RECT 1.45 2.865 2.89 3.125 ;
        RECT 2.63 0.61 2.89 3.125 ;
        RECT 2.31 0.61 2.89 0.905 ;
        RECT 2.325 2.865 2.555 3.53 ;
        RECT 1.45 2.865 1.71 3.515 ;
    END
  END Y
  OBS
    LAYER met1 ;
      RECT 1.465 0.61 1.695 0.935 ;
      RECT 0.605 0.61 0.835 0.935 ;
      RECT 0.605 0.61 1.695 0.84 ;
  END
  PROPERTY CatenaDesignType "deviceLevel" ;
END OAI211X1_LP

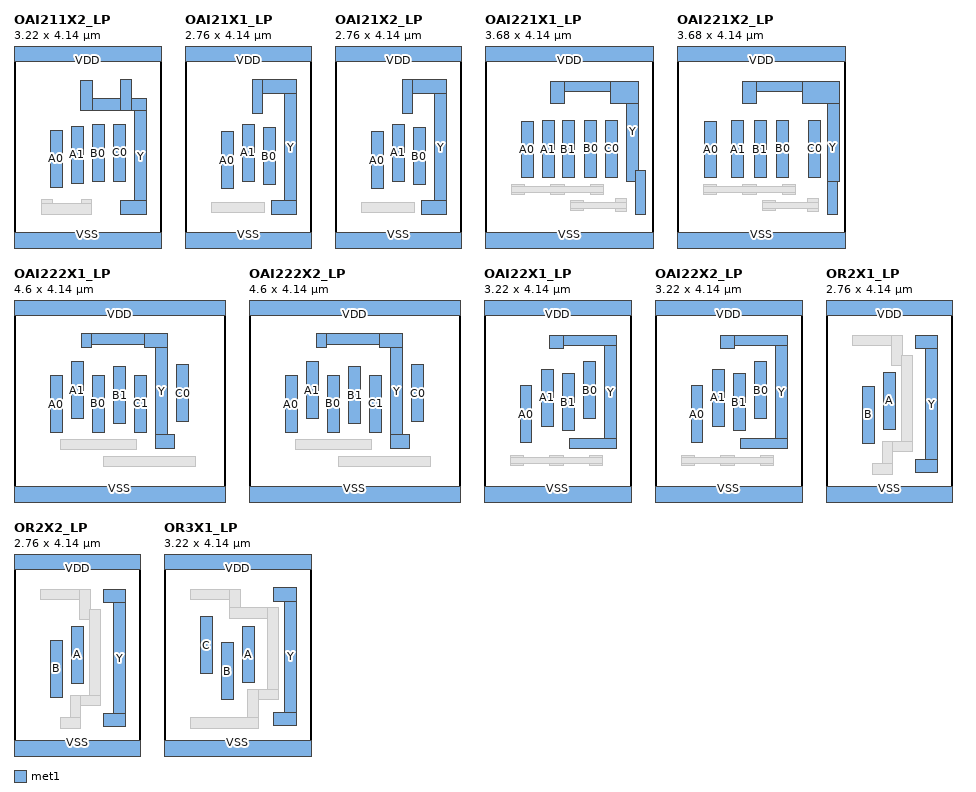
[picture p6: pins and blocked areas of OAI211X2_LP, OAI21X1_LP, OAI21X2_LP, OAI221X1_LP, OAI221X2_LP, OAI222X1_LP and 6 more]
MACRO OAI211X2_LP
  CLASS CORE ;
  ORIGIN 0 0 ;
  FOREIGN OAI211X2_LP 0 0 ;
  SIZE 3.22 BY 4.14 ;
  SYMMETRY X Y ;
  SITE CoreSite ;
  PIN A0
    DIRECTION INPUT ;
    USE SIGNAL ;
    PORT
      LAYER met1 ;
        RECT 0.79 1.19 1.05 2.43 ;
    END
  END A0
  PIN A1
    DIRECTION INPUT ;
    USE SIGNAL ;
    PORT
      LAYER met1 ;
        RECT 1.25 1.285 1.51 2.525 ;
    END
  END A1
  PIN B0
    DIRECTION INPUT ;
    USE SIGNAL ;
    PORT
      LAYER met1 ;
        RECT 1.71 1.31 1.97 2.55 ;
    END
  END B0
  PIN C0
    DIRECTION INPUT ;
    USE SIGNAL ;
    PORT
      LAYER met1 ;
        RECT 2.17 1.32 2.43 2.56 ;
    END
  END C0
  PIN VDD
    DIRECTION INPUT ;
    USE POWER ;
    SHAPE ABUTMENT ;
    NETEXPR "VDD VDD!" ;
    PORT
      LAYER met1 ;
        RECT 0 3.94 3.22 4.34 ;
    END
  END VDD
  PIN VSS
    DIRECTION INPUT ;
    USE GROUND ;
    SHAPE ABUTMENT ;
    NETEXPR "VSS VSS!" ;
    PORT
      LAYER met1 ;
        RECT 0 -0.2 3.22 0.2 ;
    END
  END VSS
  PIN Y
    DIRECTION OUTPUT ;
    USE SIGNAL ;
    PORT
      LAYER met1 ;
        RECT 1.45 2.865 2.89 3.125 ;
        RECT 2.63 0.61 2.89 3.125 ;
        RECT 2.31 0.61 2.89 0.905 ;
        RECT 2.325 2.865 2.555 3.53 ;
        RECT 1.45 2.865 1.71 3.515 ;
    END
  END Y
  OBS
    LAYER met1 ;
      RECT 1.465 0.61 1.695 0.935 ;
      RECT 0.605 0.61 0.835 0.935 ;
      RECT 0.605 0.61 1.695 0.84 ;
  END
  PROPERTY CatenaDesignType "deviceLevel" ;
END OAI211X2_LP

MACRO OAI21X1_LP
  CLASS CORE ;
  ORIGIN 0 0 ;
  FOREIGN OAI21X1_LP 0 0 ;
  SIZE 2.76 BY 4.14 ;
  SYMMETRY X Y ;
  SITE CoreSite ;
  PIN A0
    DIRECTION INPUT ;
    USE SIGNAL ;
    PORT
      LAYER met1 ;
        RECT 0.79 1.165 1.05 2.405 ;
    END
  END A0
  PIN A1
    DIRECTION INPUT ;
    USE SIGNAL ;
    PORT
      LAYER met1 ;
        RECT 1.25 1.325 1.51 2.565 ;
    END
  END A1
  PIN B0
    DIRECTION INPUT ;
    USE SIGNAL ;
    PORT
      LAYER met1 ;
        RECT 1.71 1.245 1.97 2.485 ;
    END
  END B0
  PIN VDD
    DIRECTION INPUT ;
    USE POWER ;
    SHAPE ABUTMENT ;
    NETEXPR "VDD VDD!" ;
    PORT
      LAYER met1 ;
        RECT 0 3.94 2.76 4.34 ;
    END
  END VDD
  PIN VSS
    DIRECTION INPUT ;
    USE GROUND ;
    SHAPE ABUTMENT ;
    NETEXPR "VSS VSS!" ;
    PORT
      LAYER met1 ;
        RECT 0 -0.2 2.76 0.2 ;
    END
  END VSS
  PIN Y
    DIRECTION OUTPUT ;
    USE SIGNAL ;
    PORT
      LAYER met1 ;
        RECT 1.465 3.24 2.43 3.53 ;
        RECT 2.17 0.61 2.43 3.53 ;
        RECT 1.895 0.61 2.43 0.9 ;
        RECT 1.465 2.795 1.695 3.53 ;
    END
  END Y
  OBS
    LAYER met1 ;
      RECT 0.575 0.64 1.725 0.87 ;
  END
  PROPERTY CatenaDesignType "deviceLevel" ;
END OAI21X1_LP

MACRO OAI21X2_LP
  CLASS CORE ;
  ORIGIN 0 0 ;
  FOREIGN OAI21X2_LP 0 0 ;
  SIZE 2.76 BY 4.14 ;
  SYMMETRY X Y ;
  SITE CoreSite ;
  PIN A0
    DIRECTION INPUT ;
    USE SIGNAL ;
    PORT
      LAYER met1 ;
        RECT 0.79 1.165 1.05 2.405 ;
    END
  END A0
  PIN A1
    DIRECTION INPUT ;
    USE SIGNAL ;
    PORT
      LAYER met1 ;
        RECT 1.25 1.325 1.51 2.565 ;
    END
  END A1
  PIN B0
    DIRECTION INPUT ;
    USE SIGNAL ;
    PORT
      LAYER met1 ;
        RECT 1.71 1.245 1.97 2.485 ;
    END
  END B0
  PIN VDD
    DIRECTION INPUT ;
    USE POWER ;
    SHAPE ABUTMENT ;
    NETEXPR "VDD VDD!" ;
    PORT
      LAYER met1 ;
        RECT 0 3.94 2.76 4.34 ;
    END
  END VDD
  PIN VSS
    DIRECTION INPUT ;
    USE GROUND ;
    SHAPE ABUTMENT ;
    NETEXPR "VSS VSS!" ;
    PORT
      LAYER met1 ;
        RECT 0 -0.2 2.76 0.2 ;
    END
  END VSS
  PIN Y
    DIRECTION OUTPUT ;
    USE SIGNAL ;
    PORT
      LAYER met1 ;
        RECT 1.465 3.24 2.43 3.53 ;
        RECT 2.17 0.61 2.43 3.53 ;
        RECT 1.895 0.61 2.43 0.9 ;
        RECT 1.465 2.795 1.695 3.53 ;
    END
  END Y
  OBS
    LAYER met1 ;
      RECT 0.575 0.64 1.725 0.87 ;
  END
  PROPERTY CatenaDesignType "deviceLevel" ;
END OAI21X2_LP

MACRO OAI221X1_LP
  CLASS CORE ;
  ORIGIN 0 0 ;
  FOREIGN OAI221X1_LP 0 0 ;
  SIZE 3.68 BY 4.14 ;
  SYMMETRY X Y ;
  SITE CoreSite ;
  PIN A0
    DIRECTION INPUT ;
    USE SIGNAL ;
    PORT
      LAYER met1 ;
        RECT 0.79 1.395 1.05 2.635 ;
    END
  END A0
  PIN A1
    DIRECTION INPUT ;
    USE SIGNAL ;
    PORT
      LAYER met1 ;
        RECT 1.25 1.4 1.51 2.64 ;
    END
  END A1
  PIN B0
    DIRECTION INPUT ;
    USE SIGNAL ;
    PORT
      LAYER met1 ;
        RECT 2.17 1.415 2.43 2.655 ;
    END
  END B0
  PIN B1
    DIRECTION INPUT ;
    USE SIGNAL ;
    PORT
      LAYER met1 ;
        RECT 1.685 1.405 1.945 2.645 ;
    END
  END B1
  PIN C0
    DIRECTION INPUT ;
    USE SIGNAL ;
    PORT
      LAYER met1 ;
        RECT 2.63 1.415 2.89 2.655 ;
    END
  END C0
  PIN VDD
    DIRECTION INPUT ;
    USE POWER ;
    SHAPE ABUTMENT ;
    NETEXPR "VDD VDD!" ;
    PORT
      LAYER met1 ;
        RECT 0 3.94 3.68 4.34 ;
    END
  END VDD
  PIN VSS
    DIRECTION INPUT ;
    USE GROUND ;
    SHAPE ABUTMENT ;
    NETEXPR "VSS VSS!" ;
    PORT
      LAYER met1 ;
        RECT 0 -0.2 3.68 0.2 ;
    END
  END VSS
  PIN Y
    DIRECTION OUTPUT ;
    USE SIGNAL ;
    PORT
      LAYER met1 ;
        RECT 3.275 0.61 3.505 1.555 ;
        RECT 1.435 3.27 3.35 3.5 ;
        RECT 2.725 3.025 3.35 3.5 ;
        RECT 3.09 1.325 3.35 3.5 ;
        RECT 1.435 3.025 1.725 3.5 ;
    END
  END Y
  OBS
    LAYER met1 ;
      RECT 2.845 0.655 3.075 0.945 ;
      RECT 1.865 0.685 2.155 0.915 ;
      RECT 1.865 0.73 3.075 0.87 ;
      RECT 2.295 1.025 2.585 1.255 ;
      RECT 1.435 1.025 1.725 1.255 ;
      RECT 0.575 1.025 0.865 1.255 ;
      RECT 0.575 1.07 2.585 1.21 ;
  END
  PROPERTY CatenaDesignType "deviceLevel" ;
END OAI221X1_LP

MACRO OAI221X2_LP
  CLASS CORE ;
  ORIGIN 0 0 ;
  FOREIGN OAI221X2_LP 0 0 ;
  SIZE 3.68 BY 4.14 ;
  SYMMETRY X Y ;
  SITE CoreSite ;
  PIN A0
    DIRECTION INPUT ;
    USE SIGNAL ;
    PORT
      LAYER met1 ;
        RECT 0.6 1.395 0.86 2.635 ;
    END
  END A0
  PIN A1
    DIRECTION INPUT ;
    USE SIGNAL ;
    PORT
      LAYER met1 ;
        RECT 1.19 1.4 1.45 2.64 ;
    END
  END A1
  PIN B0
    DIRECTION INPUT ;
    USE SIGNAL ;
    PORT
      LAYER met1 ;
        RECT 2.17 1.415 2.43 2.655 ;
    END
  END B0
  PIN B1
    DIRECTION INPUT ;
    USE SIGNAL ;
    PORT
      LAYER met1 ;
        RECT 1.685 1.405 1.945 2.645 ;
    END
  END B1
  PIN C0
    DIRECTION INPUT ;
    USE SIGNAL ;
    PORT
      LAYER met1 ;
        RECT 2.875 1.415 3.135 2.655 ;
    END
  END C0
  PIN VDD
    DIRECTION INPUT ;
    USE POWER ;
    SHAPE ABUTMENT ;
    NETEXPR "VDD VDD!" ;
    PORT
      LAYER met1 ;
        RECT 0 3.94 3.68 4.34 ;
    END
  END VDD
  PIN VSS
    DIRECTION INPUT ;
    USE GROUND ;
    SHAPE ABUTMENT ;
    NETEXPR "VSS VSS!" ;
    PORT
      LAYER met1 ;
        RECT 0 -0.2 3.68 0.2 ;
    END
  END VSS
  PIN Y
    DIRECTION OUTPUT ;
    USE SIGNAL ;
    PORT
      LAYER met1 ;
        RECT 1.435 3.27 3.535 3.5 ;
        RECT 3.275 1.325 3.535 3.5 ;
        RECT 3.275 0.61 3.505 3.5 ;
        RECT 2.725 3.025 3.535 3.5 ;
        RECT 1.435 3.025 1.725 3.5 ;
    END
  END Y
  OBS
    LAYER met1 ;
      RECT 2.845 0.655 3.075 0.945 ;
      RECT 1.865 0.685 2.155 0.915 ;
      RECT 1.865 0.73 3.075 0.87 ;
      RECT 2.295 1.025 2.585 1.255 ;
      RECT 1.435 1.025 1.725 1.255 ;
      RECT 0.575 1.025 0.865 1.255 ;
      RECT 0.575 1.07 2.585 1.21 ;
  END
  PROPERTY CatenaDesignType "deviceLevel" ;
END OAI221X2_LP

MACRO OAI222X1_LP
  CLASS CORE ;
  ORIGIN 0 0 ;
  FOREIGN OAI222X1_LP 0 0 ;
  SIZE 4.6 BY 4.14 ;
  SYMMETRY X Y ;
  SITE CoreSite ;
  PIN A0
    DIRECTION INPUT ;
    USE SIGNAL ;
    PORT
      LAYER met1 ;
        RECT 0.79 1.38 1.05 2.62 ;
    END
  END A0
  PIN A1
    DIRECTION INPUT ;
    USE SIGNAL ;
    PORT
      LAYER met1 ;
        RECT 1.25 1.685 1.51 2.925 ;
    END
  END A1
  PIN B0
    DIRECTION INPUT ;
    USE SIGNAL ;
    PORT
      LAYER met1 ;
        RECT 1.71 1.39 1.97 2.63 ;
    END
  END B0
  PIN B1
    DIRECTION INPUT ;
    USE SIGNAL ;
    PORT
      LAYER met1 ;
        RECT 2.17 1.58 2.43 2.82 ;
    END
  END B1
  PIN C0
    DIRECTION INPUT ;
    USE SIGNAL ;
    PORT
      LAYER met1 ;
        RECT 3.55 1.62 3.81 2.86 ;
    END
  END C0
  PIN C1
    DIRECTION INPUT ;
    USE SIGNAL ;
    PORT
      LAYER met1 ;
        RECT 2.63 1.385 2.89 2.625 ;
    END
  END C1
  PIN VDD
    DIRECTION INPUT ;
    USE POWER ;
    SHAPE ABUTMENT ;
    NETEXPR "VDD VDD!" ;
    PORT
      LAYER met1 ;
        RECT 0 3.94 4.6 4.34 ;
    END
  END VDD
  PIN VSS
    DIRECTION INPUT ;
    USE GROUND ;
    SHAPE ABUTMENT ;
    NETEXPR "VSS VSS!" ;
    PORT
      LAYER met1 ;
        RECT 0 -0.2 4.6 0.2 ;
    END
  END VSS
  PIN Y
    DIRECTION OUTPUT ;
    USE SIGNAL ;
    PORT
      LAYER met1 ;
        RECT 3.09 1.04 3.505 1.33 ;
        RECT 1.465 3.3 3.35 3.53 ;
        RECT 3.09 1.04 3.35 3.53 ;
        RECT 2.845 3.24 3.35 3.53 ;
        RECT 1.465 3.24 1.695 3.53 ;
    END
  END Y
  OBS
    LAYER met1 ;
      RECT 1.955 0.64 3.965 0.87 ;
      RECT 1.005 1.01 2.675 1.24 ;
  END
  PROPERTY CatenaDesignType "deviceLevel" ;
END OAI222X1_LP

MACRO OAI222X2_LP
  CLASS CORE ;
  ORIGIN 0 0 ;
  FOREIGN OAI222X2_LP 0 0 ;
  SIZE 4.6 BY 4.14 ;
  SYMMETRY X Y ;
  SITE CoreSite ;
  PIN A0
    DIRECTION INPUT ;
    USE SIGNAL ;
    PORT
      LAYER met1 ;
        RECT 0.79 1.38 1.05 2.62 ;
    END
  END A0
  PIN A1
    DIRECTION INPUT ;
    USE SIGNAL ;
    PORT
      LAYER met1 ;
        RECT 1.25 1.685 1.51 2.925 ;
    END
  END A1
  PIN B0
    DIRECTION INPUT ;
    USE SIGNAL ;
    PORT
      LAYER met1 ;
        RECT 1.71 1.39 1.97 2.63 ;
    END
  END B0
  PIN B1
    DIRECTION INPUT ;
    USE SIGNAL ;
    PORT
      LAYER met1 ;
        RECT 2.17 1.58 2.43 2.82 ;
    END
  END B1
  PIN C0
    DIRECTION INPUT ;
    USE SIGNAL ;
    PORT
      LAYER met1 ;
        RECT 3.55 1.62 3.81 2.86 ;
    END
  END C0
  PIN C1
    DIRECTION INPUT ;
    USE SIGNAL ;
    PORT
      LAYER met1 ;
        RECT 2.63 1.385 2.89 2.625 ;
    END
  END C1
  PIN VDD
    DIRECTION INPUT ;
    USE POWER ;
    SHAPE ABUTMENT ;
    NETEXPR "VDD VDD!" ;
    PORT
      LAYER met1 ;
        RECT 0 3.94 4.6 4.34 ;
    END
  END VDD
  PIN VSS
    DIRECTION INPUT ;
    USE GROUND ;
    SHAPE ABUTMENT ;
    NETEXPR "VSS VSS!" ;
    PORT
      LAYER met1 ;
        RECT 0 -0.2 4.6 0.2 ;
    END
  END VSS
  PIN Y
    DIRECTION OUTPUT ;
    USE SIGNAL ;
    PORT
      LAYER met1 ;
        RECT 3.09 1.04 3.505 1.33 ;
        RECT 1.465 3.3 3.35 3.53 ;
        RECT 3.09 1.04 3.35 3.53 ;
        RECT 2.845 3.24 3.35 3.53 ;
        RECT 1.465 3.24 1.695 3.53 ;
    END
  END Y
  OBS
    LAYER met1 ;
      RECT 1.955 0.64 3.965 0.87 ;
      RECT 1.005 1.01 2.675 1.24 ;
  END
  PROPERTY CatenaDesignType "deviceLevel" ;
END OAI222X2_LP

MACRO OAI22X1_LP
  CLASS CORE ;
  ORIGIN 0 0 ;
  FOREIGN OAI22X1_LP 0 0 ;
  SIZE 3.22 BY 4.14 ;
  SYMMETRY X Y ;
  SITE CoreSite ;
  PIN A0
    DIRECTION INPUT ;
    USE SIGNAL ;
    PORT
      LAYER met1 ;
        RECT 0.785 1.165 1.045 2.405 ;
    END
  END A0
  PIN A1
    DIRECTION INPUT ;
    USE SIGNAL ;
    PORT
      LAYER met1 ;
        RECT 1.25 1.52 1.51 2.76 ;
    END
  END A1
  PIN B0
    DIRECTION INPUT ;
    USE SIGNAL ;
    PORT
      LAYER met1 ;
        RECT 2.17 1.685 2.43 2.925 ;
    END
  END B0
  PIN B1
    DIRECTION INPUT ;
    USE SIGNAL ;
    PORT
      LAYER met1 ;
        RECT 1.71 1.42 1.97 2.66 ;
    END
  END B1
  PIN VDD
    DIRECTION INPUT ;
    USE POWER ;
    SHAPE ABUTMENT ;
    NETEXPR "VDD VDD!" ;
    PORT
      LAYER met1 ;
        RECT 0 3.94 3.22 4.34 ;
    END
  END VDD
  PIN VSS
    DIRECTION INPUT ;
    USE GROUND ;
    SHAPE ABUTMENT ;
    NETEXPR "VSS VSS!" ;
    PORT
      LAYER met1 ;
        RECT 0 -0.2 3.22 0.2 ;
    END
  END VSS
  PIN Y
    DIRECTION OUTPUT ;
    USE SIGNAL ;
    PORT
      LAYER met1 ;
        RECT 1.435 3.27 2.89 3.5 ;
        RECT 2.63 1.025 2.89 3.5 ;
        RECT 1.865 1.025 2.89 1.255 ;
        RECT 1.435 3.205 1.725 3.5 ;
    END
  END Y
  OBS
    LAYER met1 ;
      RECT 2.295 0.655 2.585 0.885 ;
      RECT 1.435 0.655 1.725 0.885 ;
      RECT 0.575 0.655 0.865 0.885 ;
      RECT 0.575 0.7 2.585 0.84 ;
  END
  PROPERTY CatenaDesignType "deviceLevel" ;
END OAI22X1_LP

MACRO OAI22X2_LP
  CLASS CORE ;
  ORIGIN 0 0 ;
  FOREIGN OAI22X2_LP 0 0 ;
  SIZE 3.22 BY 4.14 ;
  SYMMETRY X Y ;
  SITE CoreSite ;
  PIN A0
    DIRECTION INPUT ;
    USE SIGNAL ;
    PORT
      LAYER met1 ;
        RECT 0.785 1.165 1.045 2.405 ;
    END
  END A0
  PIN A1
    DIRECTION INPUT ;
    USE SIGNAL ;
    PORT
      LAYER met1 ;
        RECT 1.25 1.52 1.51 2.76 ;
    END
  END A1
  PIN B0
    DIRECTION INPUT ;
    USE SIGNAL ;
    PORT
      LAYER met1 ;
        RECT 2.17 1.685 2.43 2.925 ;
    END
  END B0
  PIN B1
    DIRECTION INPUT ;
    USE SIGNAL ;
    PORT
      LAYER met1 ;
        RECT 1.71 1.42 1.97 2.66 ;
    END
  END B1
  PIN VDD
    DIRECTION INPUT ;
    USE POWER ;
    SHAPE ABUTMENT ;
    NETEXPR "VDD VDD!" ;
    PORT
      LAYER met1 ;
        RECT 0 3.94 3.22 4.34 ;
    END
  END VDD
  PIN VSS
    DIRECTION INPUT ;
    USE GROUND ;
    SHAPE ABUTMENT ;
    NETEXPR "VSS VSS!" ;
    PORT
      LAYER met1 ;
        RECT 0 -0.2 3.22 0.2 ;
    END
  END VSS
  PIN Y
    DIRECTION OUTPUT ;
    USE SIGNAL ;
    PORT
      LAYER met1 ;
        RECT 1.435 3.27 2.89 3.5 ;
        RECT 2.63 1.025 2.89 3.5 ;
        RECT 1.865 1.025 2.89 1.255 ;
        RECT 1.435 3.205 1.725 3.5 ;
    END
  END Y
  OBS
    LAYER met1 ;
      RECT 2.295 0.655 2.585 0.885 ;
      RECT 1.435 0.655 1.725 0.885 ;
      RECT 0.575 0.655 0.865 0.885 ;
      RECT 0.575 0.7 2.585 0.84 ;
  END
  PROPERTY CatenaDesignType "deviceLevel" ;
END OAI22X2_LP

MACRO OR2X1_LP
  CLASS CORE ;
  ORIGIN 0 0 ;
  FOREIGN OR2X1_LP 0 0 ;
  SIZE 2.76 BY 4.14 ;
  SYMMETRY X Y ;
  SITE CoreSite ;
  PIN A
    DIRECTION INPUT ;
    USE SIGNAL ;
    PORT
      LAYER met1 ;
        RECT 1.25 1.455 1.51 2.695 ;
    END
  END A
  PIN B
    DIRECTION INPUT ;
    USE SIGNAL ;
    PORT
      LAYER met1 ;
        RECT 0.79 1.145 1.05 2.385 ;
    END
  END B
  PIN VDD
    DIRECTION INPUT ;
    USE POWER ;
    SHAPE ABUTMENT ;
    NETEXPR "VDD VDD!" ;
    PORT
      LAYER met1 ;
        RECT 0 3.94 2.76 4.34 ;
    END
  END VDD
  PIN VSS
    DIRECTION INPUT ;
    USE GROUND ;
    SHAPE ABUTMENT ;
    NETEXPR "VSS VSS!" ;
    PORT
      LAYER met1 ;
        RECT 0 -0.2 2.76 0.2 ;
    END
  END VSS
  PIN Y
    DIRECTION OUTPUT ;
    USE SIGNAL ;
    PORT
      LAYER met1 ;
        RECT 1.955 3.21 2.43 3.5 ;
        RECT 2.17 0.505 2.43 3.5 ;
        RECT 1.955 0.505 2.43 0.795 ;
    END
  END Y
  OBS
    LAYER met1 ;
      RECT 0.575 3.27 1.66 3.5 ;
      RECT 1.43 2.84 1.66 3.5 ;
      RECT 1.65 0.965 1.88 3.07 ;
      RECT 1.225 0.965 1.88 1.195 ;
      RECT 1.225 0.475 1.455 1.195 ;
      RECT 1.005 0.475 1.455 0.705 ;
  END
  PROPERTY CatenaDesignType "deviceLevel" ;
END OR2X1_LP

MACRO OR2X2_LP
  CLASS CORE ;
  ORIGIN 0 0 ;
  FOREIGN OR2X2_LP 0 0 ;
  SIZE 2.76 BY 4.14 ;
  SYMMETRY X Y ;
  SITE CoreSite ;
  PIN A
    DIRECTION INPUT ;
    USE SIGNAL ;
    PORT
      LAYER met1 ;
        RECT 1.25 1.455 1.51 2.695 ;
    END
  END A
  PIN B
    DIRECTION INPUT ;
    USE SIGNAL ;
    PORT
      LAYER met1 ;
        RECT 0.79 1.145 1.05 2.385 ;
    END
  END B
  PIN VDD
    DIRECTION INPUT ;
    USE POWER ;
    SHAPE ABUTMENT ;
    NETEXPR "VDD VDD!" ;
    PORT
      LAYER met1 ;
        RECT 0 3.94 2.76 4.34 ;
    END
  END VDD
  PIN VSS
    DIRECTION INPUT ;
    USE GROUND ;
    SHAPE ABUTMENT ;
    NETEXPR "VSS VSS!" ;
    PORT
      LAYER met1 ;
        RECT 0 -0.2 2.76 0.2 ;
    END
  END VSS
  PIN Y
    DIRECTION OUTPUT ;
    USE SIGNAL ;
    PORT
      LAYER met1 ;
        RECT 1.955 3.21 2.43 3.5 ;
        RECT 2.17 0.505 2.43 3.5 ;
        RECT 1.955 0.505 2.43 0.795 ;
    END
  END Y
  OBS
    LAYER met1 ;
      RECT 0.575 3.27 1.66 3.5 ;
      RECT 1.43 2.84 1.66 3.5 ;
      RECT 1.65 0.965 1.88 3.07 ;
      RECT 1.225 0.965 1.88 1.195 ;
      RECT 1.225 0.475 1.455 1.195 ;
      RECT 1.005 0.475 1.455 0.705 ;
  END
  PROPERTY CatenaDesignType "deviceLevel" ;
END OR2X2_LP

MACRO OR3X1_LP
  CLASS CORE ;
  ORIGIN 0 0 ;
  FOREIGN OR3X1_LP 0 0 ;
  SIZE 3.22 BY 4.14 ;
  SYMMETRY X Y ;
  SITE CoreSite ;
  PIN A
    DIRECTION INPUT ;
    USE SIGNAL ;
    PORT
      LAYER met1 ;
        RECT 1.71 1.46 1.97 2.7 ;
    END
  END A
  PIN B
    DIRECTION INPUT ;
    USE SIGNAL ;
    PORT
      LAYER met1 ;
        RECT 1.25 1.1 1.51 2.34 ;
    END
  END B
  PIN C
    DIRECTION INPUT ;
    USE SIGNAL ;
    PORT
      LAYER met1 ;
        RECT 0.79 1.665 1.05 2.905 ;
    END
  END C
  PIN VDD
    DIRECTION INPUT ;
    USE POWER ;
    SHAPE ABUTMENT ;
    NETEXPR "VDD VDD!" ;
    PORT
      LAYER met1 ;
        RECT 0 3.94 3.22 4.34 ;
    END
  END VDD
  PIN VSS
    DIRECTION INPUT ;
    USE GROUND ;
    SHAPE ABUTMENT ;
    NETEXPR "VSS VSS!" ;
    PORT
      LAYER met1 ;
        RECT 0 -0.2 3.22 0.2 ;
    END
  END VSS
  PIN Y
    DIRECTION OUTPUT ;
    USE SIGNAL ;
    PORT
      LAYER met1 ;
        RECT 2.385 3.24 2.89 3.53 ;
        RECT 2.63 0.535 2.89 3.53 ;
        RECT 2.385 0.535 2.89 0.825 ;
    END
  END Y
  OBS
    LAYER met1 ;
      RECT 0.575 3.27 1.66 3.5 ;
      RECT 1.43 2.87 1.66 3.5 ;
      RECT 1.43 2.87 2.49 3.1 ;
      RECT 2.26 1.09 2.49 3.1 ;
      RECT 1.82 1.09 2.49 1.32 ;
      RECT 1.82 0.475 2.05 1.32 ;
      RECT 0.575 0.475 2.05 0.705 ;
  END
  PROPERTY CatenaDesignType "deviceLevel" ;
END OR3X1_LP

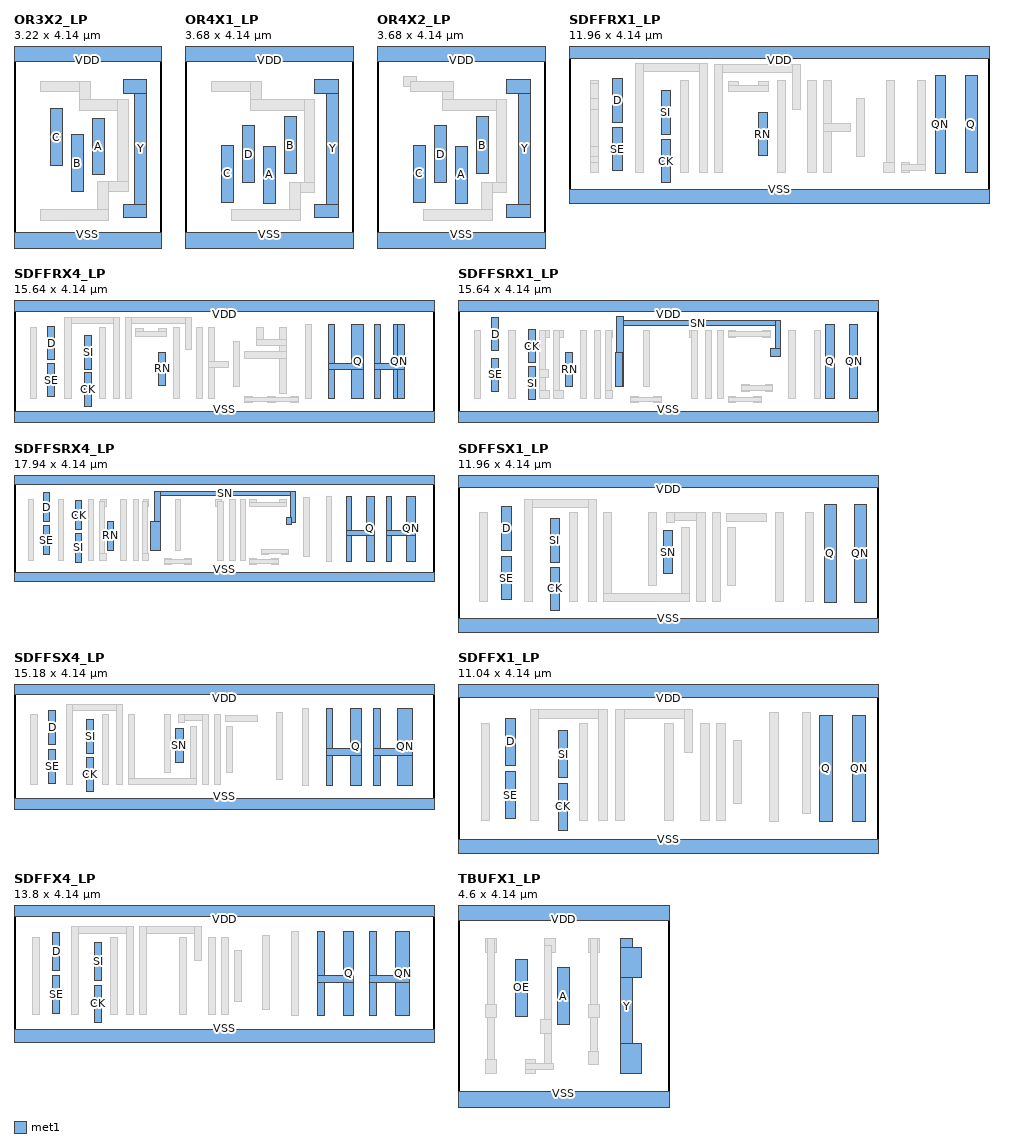
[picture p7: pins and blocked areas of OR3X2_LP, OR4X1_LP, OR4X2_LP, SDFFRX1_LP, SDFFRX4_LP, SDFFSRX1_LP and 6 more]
MACRO OR3X2_LP
  CLASS CORE ;
  ORIGIN 0 0 ;
  FOREIGN OR3X2_LP 0 0 ;
  SIZE 3.22 BY 4.14 ;
  SYMMETRY X Y ;
  SITE CoreSite ;
  PIN A
    DIRECTION INPUT ;
    USE SIGNAL ;
    PORT
      LAYER met1 ;
        RECT 1.71 1.46 1.97 2.7 ;
    END
  END A
  PIN B
    DIRECTION INPUT ;
    USE SIGNAL ;
    PORT
      LAYER met1 ;
        RECT 1.25 1.1 1.51 2.34 ;
    END
  END B
  PIN C
    DIRECTION INPUT ;
    USE SIGNAL ;
    PORT
      LAYER met1 ;
        RECT 0.79 1.665 1.05 2.905 ;
    END
  END C
  PIN VDD
    DIRECTION INPUT ;
    USE POWER ;
    SHAPE ABUTMENT ;
    NETEXPR "VDD VDD!" ;
    PORT
      LAYER met1 ;
        RECT 0 3.94 3.22 4.34 ;
    END
  END VDD
  PIN VSS
    DIRECTION INPUT ;
    USE GROUND ;
    SHAPE ABUTMENT ;
    NETEXPR "VSS VSS!" ;
    PORT
      LAYER met1 ;
        RECT 0 -0.2 3.22 0.2 ;
    END
  END VSS
  PIN Y
    DIRECTION OUTPUT ;
    USE SIGNAL ;
    PORT
      LAYER met1 ;
        RECT 2.385 3.24 2.89 3.53 ;
        RECT 2.63 0.535 2.89 3.53 ;
        RECT 2.385 0.535 2.89 0.825 ;
    END
  END Y
  OBS
    LAYER met1 ;
      RECT 0.575 3.27 1.66 3.5 ;
      RECT 1.43 2.87 1.66 3.5 ;
      RECT 1.43 2.87 2.49 3.1 ;
      RECT 2.26 1.09 2.49 3.1 ;
      RECT 1.82 1.09 2.49 1.32 ;
      RECT 1.82 0.475 2.05 1.32 ;
      RECT 0.575 0.475 2.05 0.705 ;
  END
  PROPERTY CatenaDesignType "deviceLevel" ;
END OR3X2_LP

MACRO OR4X1_LP
  CLASS CORE ;
  ORIGIN 0 0 ;
  FOREIGN OR4X1_LP 0 0 ;
  SIZE 3.68 BY 4.14 ;
  SYMMETRY X Y ;
  SITE CoreSite ;
  PIN A
    DIRECTION INPUT ;
    USE SIGNAL ;
    PORT
      LAYER met1 ;
        RECT 1.71 0.845 1.97 2.085 ;
    END
  END A
  PIN B
    DIRECTION INPUT ;
    USE SIGNAL ;
    PORT
      LAYER met1 ;
        RECT 2.17 1.485 2.43 2.725 ;
    END
  END B
  PIN C
    DIRECTION INPUT ;
    USE SIGNAL ;
    PORT
      LAYER met1 ;
        RECT 0.79 0.865 1.05 2.105 ;
    END
  END C
  PIN D
    DIRECTION INPUT ;
    USE SIGNAL ;
    PORT
      LAYER met1 ;
        RECT 1.25 1.29 1.51 2.53 ;
    END
  END D
  PIN VDD
    DIRECTION INPUT ;
    USE POWER ;
    SHAPE ABUTMENT ;
    NETEXPR "VDD VDD!" ;
    PORT
      LAYER met1 ;
        RECT 0 3.94 3.68 4.34 ;
    END
  END VDD
  PIN VSS
    DIRECTION INPUT ;
    USE GROUND ;
    SHAPE ABUTMENT ;
    NETEXPR "VSS VSS!" ;
    PORT
      LAYER met1 ;
        RECT 0 -0.2 3.68 0.2 ;
    END
  END VSS
  PIN Y
    DIRECTION OUTPUT ;
    USE SIGNAL ;
    PORT
      LAYER met1 ;
        RECT 2.815 3.24 3.35 3.53 ;
        RECT 3.09 0.535 3.35 3.53 ;
        RECT 2.815 0.535 3.35 0.825 ;
    END
  END Y
  OBS
    LAYER met1 ;
      RECT 0.575 3.27 1.66 3.5 ;
      RECT 1.43 2.87 1.66 3.5 ;
      RECT 1.43 2.87 2.83 3.1 ;
      RECT 2.6 1.07 2.83 3.1 ;
      RECT 2.28 1.07 2.83 1.3 ;
      RECT 2.28 0.475 2.51 1.3 ;
      RECT 1.005 0.475 2.51 0.705 ;
  END
  PROPERTY CatenaDesignType "deviceLevel" ;
END OR4X1_LP

MACRO OR4X2_LP
  CLASS CORE ;
  ORIGIN 0 0 ;
  FOREIGN OR4X2_LP 0 0 ;
  SIZE 3.68 BY 4.14 ;
  SYMMETRY X Y ;
  SITE CoreSite ;
  PIN A
    DIRECTION INPUT ;
    USE SIGNAL ;
    PORT
      LAYER met1 ;
        RECT 1.71 0.845 1.97 2.085 ;
    END
  END A
  PIN B
    DIRECTION INPUT ;
    USE SIGNAL ;
    PORT
      LAYER met1 ;
        RECT 2.17 1.485 2.43 2.725 ;
    END
  END B
  PIN C
    DIRECTION INPUT ;
    USE SIGNAL ;
    PORT
      LAYER met1 ;
        RECT 0.79 0.865 1.05 2.105 ;
    END
  END C
  PIN D
    DIRECTION INPUT ;
    USE SIGNAL ;
    PORT
      LAYER met1 ;
        RECT 1.25 1.29 1.51 2.53 ;
    END
  END D
  PIN VDD
    DIRECTION INPUT ;
    USE POWER ;
    SHAPE ABUTMENT ;
    NETEXPR "VDD VDD!" ;
    PORT
      LAYER met1 ;
        RECT 0 3.94 3.68 4.34 ;
    END
  END VDD
  PIN VSS
    DIRECTION INPUT ;
    USE GROUND ;
    SHAPE ABUTMENT ;
    NETEXPR "VSS VSS!" ;
    PORT
      LAYER met1 ;
        RECT 0 -0.2 3.68 0.2 ;
    END
  END VSS
  PIN Y
    DIRECTION OUTPUT ;
    USE SIGNAL ;
    PORT
      LAYER met1 ;
        RECT 2.815 3.24 3.35 3.53 ;
        RECT 3.09 0.535 3.35 3.53 ;
        RECT 2.815 0.535 3.35 0.825 ;
    END
  END Y
  OBS
    LAYER met1 ;
      RECT 0.575 3.38 0.865 3.61 ;
      RECT 1.43 2.87 1.66 3.5 ;
      RECT 0.735 3.27 1.66 3.5 ;
      RECT 1.43 2.87 2.83 3.1 ;
      RECT 2.6 1.07 2.83 3.1 ;
      RECT 2.28 1.07 2.83 1.3 ;
      RECT 2.28 0.475 2.51 1.3 ;
      RECT 1.005 0.475 2.51 0.705 ;
  END
  PROPERTY CatenaDesignType "deviceLevel" ;
END OR4X2_LP

MACRO SDFFRX1_LP
  CLASS CORE ;
  ORIGIN 0 0 ;
  FOREIGN SDFFRX1_LP 0 0 ;
  SIZE 11.96 BY 4.14 ;
  SYMMETRY X Y ;
  SITE CoreSite ;
  PIN CK
    DIRECTION INPUT ;
    USE SIGNAL ;
    PORT
      LAYER met1 ;
        RECT 2.63 0.4 2.89 1.64 ;
    END
  END CK
  PIN D
    DIRECTION INPUT ;
    USE SIGNAL ;
    PORT
      LAYER met1 ;
        RECT 1.25 2.125 1.51 3.365 ;
    END
  END D
  PIN Q
    DIRECTION OUTPUT ;
    USE SIGNAL ;
    PORT
      LAYER met1 ;
        RECT 11.285 0.685 11.63 3.455 ;
    END
  END Q
  PIN QN
    DIRECTION OUTPUT ;
    USE SIGNAL ;
    PORT
      LAYER met1 ;
        RECT 10.425 0.68 10.71 3.45 ;
    END
  END QN
  PIN RN
    DIRECTION INPUT ;
    USE SIGNAL ;
    PORT
      LAYER met1 ;
        RECT 5.39 1.17 5.65 2.41 ;
    END
  END RN
  PIN SE
    DIRECTION INPUT ;
    USE SIGNAL ;
    PORT
      LAYER met1 ;
        RECT 1.25 0.745 1.51 1.985 ;
    END
  END SE
  PIN SI
    DIRECTION INPUT ;
    USE SIGNAL ;
    PORT
      LAYER met1 ;
        RECT 2.63 1.78 2.89 3.02 ;
    END
  END SI
  PIN VDD
    DIRECTION INPUT ;
    USE POWER ;
    SHAPE ABUTMENT ;
    NETEXPR "VDD VDD!" ;
    PORT
      LAYER met1 ;
        RECT 0 3.94 11.96 4.34 ;
    END
  END VDD
  PIN VSS
    DIRECTION INPUT ;
    USE GROUND ;
    SHAPE ABUTMENT ;
    NETEXPR "VSS VSS!" ;
    PORT
      LAYER met1 ;
        RECT 0 -0.2 11.96 0.2 ;
    END
  END VSS
  OBS
    LAYER met1 ;
      RECT 9.91 0.765 10.14 3.32 ;
      RECT 9.475 0.705 9.705 0.995 ;
      RECT 9.475 0.765 10.14 0.935 ;
      RECT 9.045 0.705 9.275 3.32 ;
      RECT 8.955 0.705 9.275 0.995 ;
      RECT 7.235 0.705 7.465 3.32 ;
      RECT 7.235 1.855 8.005 2.085 ;
      RECT 4.135 3.555 6.605 3.785 ;
      RECT 6.375 2.505 6.605 3.785 ;
      RECT 4.135 0.705 4.365 3.785 ;
      RECT 5.395 3.005 5.685 3.29 ;
      RECT 4.535 3.005 4.825 3.29 ;
      RECT 4.535 3.005 5.685 3.175 ;
      RECT 1.895 3.57 3.935 3.8 ;
      RECT 3.705 0.705 3.935 3.8 ;
      RECT 1.895 0.705 2.125 3.8 ;
      RECT 0.605 3.03 0.835 3.32 ;
      RECT 0.61 0.71 0.84 3.24 ;
      RECT 0.605 2.505 0.84 2.795 ;
      RECT 0.605 1.145 0.84 1.435 ;
      RECT 0.605 0.705 0.835 0.995 ;
      RECT 8.175 1.145 8.405 2.795 ;
      RECT 6.805 0.705 7.035 3.32 ;
      RECT 5.945 0.705 6.175 3.32 ;
      RECT 3.185 0.705 3.415 3.32 ;
  END
  PROPERTY CatenaDesignType "deviceLevel" ;
END SDFFRX1_LP

MACRO SDFFRX4_LP
  CLASS CORE ;
  ORIGIN 0 0 ;
  FOREIGN SDFFRX4_LP 0 0 ;
  SIZE 15.64 BY 4.14 ;
  SYMMETRY X Y ;
  SITE CoreSite ;
  PIN CK
    DIRECTION INPUT ;
    USE SIGNAL ;
    PORT
      LAYER met1 ;
        RECT 2.63 0.4 2.89 1.64 ;
    END
  END CK
  PIN D
    DIRECTION INPUT ;
    USE SIGNAL ;
    PORT
      LAYER met1 ;
        RECT 1.25 2.13 1.51 3.37 ;
    END
  END D
  PIN Q
    DIRECTION OUTPUT ;
    USE SIGNAL ;
    PORT
      LAYER met1 ;
        RECT 12.575 0.68 13.01 3.45 ;
        RECT 11.715 1.77 13.01 2 ;
        RECT 11.715 0.68 11.945 3.45 ;
    END
  END Q
  PIN QN
    DIRECTION OUTPUT ;
    USE SIGNAL ;
    PORT
      LAYER met1 ;
        RECT 14.295 0.675 14.525 3.45 ;
        RECT 14.13 0.675 14.525 3.445 ;
        RECT 13.435 1.77 14.525 2 ;
        RECT 13.435 0.68 13.665 3.45 ;
    END
  END QN
  PIN RN
    DIRECTION INPUT ;
    USE SIGNAL ;
    PORT
      LAYER met1 ;
        RECT 5.39 1.17 5.65 2.41 ;
    END
  END RN
  PIN SE
    DIRECTION INPUT ;
    USE SIGNAL ;
    PORT
      LAYER met1 ;
        RECT 1.25 0.745 1.51 1.985 ;
    END
  END SE
  PIN SI
    DIRECTION INPUT ;
    USE SIGNAL ;
    PORT
      LAYER met1 ;
        RECT 2.63 1.78 2.89 3.02 ;
    END
  END SI
  PIN VDD
    DIRECTION INPUT ;
    USE POWER ;
    SHAPE ABUTMENT ;
    NETEXPR "VDD VDD!" ;
    PORT
      LAYER met1 ;
        RECT 0 3.94 15.64 4.34 ;
    END
  END VDD
  PIN VSS
    DIRECTION INPUT ;
    USE GROUND ;
    SHAPE ABUTMENT ;
    NETEXPR "VSS VSS!" ;
    PORT
      LAYER met1 ;
        RECT 0 -0.2 15.64 0.2 ;
    END
  END VSS
  OBS
    LAYER met1 ;
      RECT 10.305 0.54 10.595 0.77 ;
      RECT 9.445 0.54 9.735 0.77 ;
      RECT 8.585 0.54 8.875 0.77 ;
      RECT 8.585 0.57 10.595 0.74 ;
      RECT 9.905 0.88 10.135 3.315 ;
      RECT 9.045 2.665 9.275 3.315 ;
      RECT 9.045 2.665 10.135 2.895 ;
      RECT 8.575 2.195 10.135 2.425 ;
      RECT 7.235 0.705 7.465 3.32 ;
      RECT 7.235 1.855 8.005 2.085 ;
      RECT 4.135 3.465 6.605 3.695 ;
      RECT 6.375 2.505 6.605 3.695 ;
      RECT 4.135 0.705 4.365 3.695 ;
      RECT 5.395 3.005 5.685 3.29 ;
      RECT 4.535 3.005 4.825 3.29 ;
      RECT 4.535 3.005 5.685 3.175 ;
      RECT 1.895 3.47 3.935 3.7 ;
      RECT 3.705 0.705 3.935 3.7 ;
      RECT 1.895 0.705 2.125 3.7 ;
      RECT 10.855 0.68 11.085 3.45 ;
      RECT 8.175 1.145 8.405 2.795 ;
      RECT 6.805 0.705 7.035 3.32 ;
      RECT 5.945 0.705 6.175 3.32 ;
      RECT 3.185 0.705 3.415 3.32 ;
      RECT 0.605 0.705 0.835 3.32 ;
  END
  PROPERTY CatenaDesignType "deviceLevel" ;
END SDFFRX4_LP

MACRO SDFFSRX1_LP
  CLASS CORE ;
  ORIGIN 0 0 ;
  FOREIGN SDFFSRX1_LP 0 0 ;
  SIZE 15.64 BY 4.14 ;
  SYMMETRY X Y ;
  SITE CoreSite ;
  PIN CK
    DIRECTION INPUT ;
    USE SIGNAL ;
    PORT
      LAYER met1 ;
        RECT 2.63 2.02 2.89 3.26 ;
    END
  END CK
  PIN D
    DIRECTION INPUT ;
    USE SIGNAL ;
    PORT
      LAYER met1 ;
        RECT 1.25 2.46 1.51 3.7 ;
    END
  END D
  PIN Q
    DIRECTION OUTPUT ;
    USE SIGNAL ;
    PORT
      LAYER met1 ;
        RECT 13.69 0.68 14.035 3.45 ;
    END
  END Q
  PIN QN
    DIRECTION OUTPUT ;
    USE SIGNAL ;
    PORT
      LAYER met1 ;
        RECT 14.59 0.675 14.885 3.45 ;
    END
  END QN
  PIN RN
    DIRECTION INPUT ;
    USE SIGNAL ;
    PORT
      LAYER met1 ;
        RECT 4.01 1.145 4.27 2.385 ;
    END
  END RN
  PIN SE
    DIRECTION INPUT ;
    USE SIGNAL ;
    PORT
      LAYER met1 ;
        RECT 1.25 0.945 1.51 2.185 ;
    END
  END SE
  PIN SI
    DIRECTION INPUT ;
    USE SIGNAL ;
    PORT
      LAYER met1 ;
        RECT 2.63 0.635 2.89 1.875 ;
    END
  END SI
  PIN SN
    DIRECTION INPUT ;
    USE SIGNAL ;
    PORT
      LAYER met1 ;
        RECT 5.885 3.39 12.005 3.59 ;
        RECT 11.805 2.245 12.005 3.59 ;
        RECT 11.62 2.245 12.005 2.535 ;
        RECT 5.885 1.15 6.145 3.75 ;
        RECT 5.85 1.145 6.11 2.385 ;
    END
  END SN
  PIN VDD
    DIRECTION INPUT ;
    USE POWER ;
    SHAPE ABUTMENT ;
    NETEXPR "VDD VDD!" ;
    PORT
      LAYER met1 ;
        RECT 0 3.94 15.64 4.34 ;
    END
  END VDD
  PIN VSS
    DIRECTION INPUT ;
    USE GROUND ;
    SHAPE ABUTMENT ;
    NETEXPR "VSS VSS!" ;
    PORT
      LAYER met1 ;
        RECT 0 -0.2 15.64 0.2 ;
    END
  END VSS
  OBS
    LAYER met1 ;
      RECT 11.435 0.965 11.725 1.195 ;
      RECT 10.575 0.965 10.865 1.195 ;
      RECT 10.575 0.995 11.725 1.165 ;
      RECT 11.345 2.975 11.635 3.205 ;
      RECT 10.055 2.975 10.345 3.205 ;
      RECT 10.055 3.005 11.635 3.175 ;
      RECT 11.005 0.54 11.295 0.77 ;
      RECT 10.055 0.54 10.345 0.77 ;
      RECT 10.055 0.57 11.295 0.74 ;
      RECT 8.615 2.945 8.935 3.235 ;
      RECT 8.705 0.705 8.935 3.235 ;
      RECT 7.295 0.54 7.585 0.77 ;
      RECT 6.435 0.54 6.725 0.77 ;
      RECT 6.435 0.57 7.585 0.74 ;
      RECT 5.48 2.945 5.745 3.235 ;
      RECT 5.48 0.705 5.71 3.235 ;
      RECT 5.48 0.705 5.745 0.995 ;
      RECT 3.555 2.945 3.935 3.235 ;
      RECT 3.555 0.705 3.785 3.235 ;
      RECT 3.555 0.705 3.935 0.995 ;
      RECT 3.03 2.945 3.415 3.235 ;
      RECT 3.03 0.705 3.26 3.235 ;
      RECT 3.03 1.485 3.375 1.775 ;
      RECT 3.03 0.705 3.415 0.995 ;
      RECT 13.275 0.705 13.505 3.235 ;
      RECT 12.325 0.705 12.555 3.235 ;
      RECT 9.655 0.705 9.885 3.235 ;
      RECT 9.225 0.705 9.455 3.235 ;
      RECT 6.895 1.145 7.125 3.235 ;
      RECT 5.085 0.705 5.315 3.235 ;
      RECT 4.565 0.705 4.795 3.235 ;
      RECT 1.895 0.705 2.125 3.235 ;
      RECT 0.605 0.705 0.835 3.235 ;
  END
  PROPERTY CatenaDesignType "deviceLevel" ;
END SDFFSRX1_LP

MACRO SDFFSRX4_LP
  CLASS CORE ;
  ORIGIN 0 0 ;
  FOREIGN SDFFSRX4_LP 0 0 ;
  SIZE 17.94 BY 4.14 ;
  SYMMETRY X Y ;
  SITE CoreSite ;
  PIN CK
    DIRECTION INPUT ;
    USE SIGNAL ;
    PORT
      LAYER met1 ;
        RECT 2.63 2.02 2.89 3.26 ;
    END
  END CK
  PIN D
    DIRECTION INPUT ;
    USE SIGNAL ;
    PORT
      LAYER met1 ;
        RECT 1.25 2.36 1.51 3.6 ;
    END
  END D
  PIN Q
    DIRECTION OUTPUT ;
    USE SIGNAL ;
    PORT
      LAYER met1 ;
        RECT 15.05 0.68 15.395 3.45 ;
        RECT 14.195 1.77 15.395 2 ;
        RECT 14.195 0.68 14.425 3.45 ;
    END
  END Q
  PIN QN
    DIRECTION OUTPUT ;
    USE SIGNAL ;
    PORT
      LAYER met1 ;
        RECT 16.775 0.68 17.15 3.455 ;
        RECT 15.915 1.77 17.15 2 ;
        RECT 15.915 0.68 16.145 3.45 ;
    END
  END QN
  PIN RN
    DIRECTION INPUT ;
    USE SIGNAL ;
    PORT
      LAYER met1 ;
        RECT 4.01 1.145 4.27 2.385 ;
    END
  END RN
  PIN SE
    DIRECTION INPUT ;
    USE SIGNAL ;
    PORT
      LAYER met1 ;
        RECT 1.25 0.945 1.51 2.185 ;
    END
  END SE
  PIN SI
    DIRECTION INPUT ;
    USE SIGNAL ;
    PORT
      LAYER met1 ;
        RECT 2.63 0.635 2.89 1.875 ;
    END
  END SI
  PIN SN
    DIRECTION INPUT ;
    USE SIGNAL ;
    PORT
      LAYER met1 ;
        RECT 6.02 3.47 12.005 3.67 ;
        RECT 11.805 2.325 12.005 3.67 ;
        RECT 11.62 2.245 11.85 2.535 ;
        RECT 6.02 1.145 6.25 3.67 ;
        RECT 5.85 1.145 6.25 2.385 ;
    END
  END SN
  PIN VDD
    DIRECTION INPUT ;
    USE POWER ;
    SHAPE ABUTMENT ;
    NETEXPR "VDD VDD!" ;
    PORT
      LAYER met1 ;
        RECT 0 3.94 17.94 4.34 ;
    END
  END VDD
  PIN VSS
    DIRECTION INPUT ;
    USE GROUND ;
    SHAPE ABUTMENT ;
    NETEXPR "VSS VSS!" ;
    PORT
      LAYER met1 ;
        RECT 0 -0.2 17.94 0.2 ;
    END
  END VSS
  OBS
    LAYER met1 ;
      RECT 11.435 0.965 11.725 1.195 ;
      RECT 10.575 0.965 10.865 1.195 ;
      RECT 10.575 0.995 11.725 1.165 ;
      RECT 11.345 3.005 11.635 3.29 ;
      RECT 10.055 3.005 10.345 3.29 ;
      RECT 10.055 3.005 11.635 3.175 ;
      RECT 11.005 0.54 11.295 0.77 ;
      RECT 10.055 0.54 10.345 0.77 ;
      RECT 10.055 0.57 11.295 0.74 ;
      RECT 8.615 3.03 8.845 3.32 ;
      RECT 8.705 0.705 8.935 3.235 ;
      RECT 7.295 0.54 7.585 0.77 ;
      RECT 6.435 0.54 6.725 0.77 ;
      RECT 6.435 0.57 7.585 0.74 ;
      RECT 5.515 3.03 5.745 3.32 ;
      RECT 5.48 0.705 5.71 3.235 ;
      RECT 5.48 0.705 5.745 0.995 ;
      RECT 3.705 3.03 3.935 3.32 ;
      RECT 3.64 0.705 3.87 3.235 ;
      RECT 3.64 0.705 3.935 0.995 ;
      RECT 13.335 0.68 13.565 3.45 ;
      RECT 12.385 0.88 12.615 3.4 ;
      RECT 9.655 0.705 9.885 3.32 ;
      RECT 9.225 0.705 9.455 3.32 ;
      RECT 6.895 1.145 7.125 3.32 ;
      RECT 5.085 0.705 5.315 3.32 ;
      RECT 4.565 0.705 4.795 3.32 ;
      RECT 3.185 0.705 3.415 3.32 ;
      RECT 1.895 0.705 2.125 3.32 ;
      RECT 0.605 0.705 0.835 3.32 ;
  END
  PROPERTY CatenaDesignType "deviceLevel" ;
END SDFFSRX4_LP

MACRO SDFFSX1_LP
  CLASS CORE ;
  ORIGIN 0 0 ;
  FOREIGN SDFFSX1_LP 0 0 ;
  SIZE 11.96 BY 4.14 ;
  SYMMETRY X Y ;
  SITE CoreSite ;
  PIN CK
    DIRECTION INPUT ;
    USE SIGNAL ;
    PORT
      LAYER met1 ;
        RECT 2.63 0.435 2.89 1.675 ;
    END
  END CK
  PIN D
    DIRECTION INPUT ;
    USE SIGNAL ;
    PORT
      LAYER met1 ;
        RECT 1.25 2.15 1.51 3.39 ;
    END
  END D
  PIN Q
    DIRECTION OUTPUT ;
    USE SIGNAL ;
    PORT
      LAYER met1 ;
        RECT 10.425 0.68 10.77 3.45 ;
    END
  END Q
  PIN QN
    DIRECTION OUTPUT ;
    USE SIGNAL ;
    PORT
      LAYER met1 ;
        RECT 11.285 0.675 11.63 3.45 ;
    END
  END QN
  PIN SE
    DIRECTION INPUT ;
    USE SIGNAL ;
    PORT
      LAYER met1 ;
        RECT 1.25 0.745 1.51 1.985 ;
    END
  END SE
  PIN SI
    DIRECTION INPUT ;
    USE SIGNAL ;
    PORT
      LAYER met1 ;
        RECT 2.63 1.82 2.89 3.06 ;
    END
  END SI
  PIN SN
    DIRECTION INPUT ;
    USE SIGNAL ;
    PORT
      LAYER met1 ;
        RECT 5.85 1.485 6.11 2.725 ;
    END
  END SN
  PIN VDD
    DIRECTION INPUT ;
    USE POWER ;
    SHAPE ABUTMENT ;
    NETEXPR "VDD VDD!" ;
    PORT
      LAYER met1 ;
        RECT 0 3.94 11.96 4.34 ;
    END
  END VDD
  PIN VSS
    DIRECTION INPUT ;
    USE GROUND ;
    SHAPE ABUTMENT ;
    NETEXPR "VSS VSS!" ;
    PORT
      LAYER met1 ;
        RECT 0 -0.2 11.96 0.2 ;
    END
  END VSS
  OBS
    LAYER met1 ;
      RECT 5.945 3.005 7.035 3.235 ;
      RECT 6.805 0.705 7.035 3.235 ;
      RECT 5.945 2.945 6.175 3.235 ;
      RECT 4.135 0.705 4.365 3.235 ;
      RECT 6.375 0.705 6.605 2.795 ;
      RECT 4.135 0.705 6.605 0.935 ;
      RECT 1.895 3.375 3.935 3.605 ;
      RECT 3.705 0.705 3.935 3.605 ;
      RECT 1.895 0.705 2.125 3.605 ;
      RECT 9.905 0.705 10.135 3.235 ;
      RECT 9.045 0.705 9.275 3.235 ;
      RECT 7.635 2.975 8.785 3.205 ;
      RECT 7.665 1.145 7.895 2.795 ;
      RECT 7.235 0.705 7.465 3.235 ;
      RECT 5.425 1.145 5.655 3.235 ;
      RECT 3.185 0.705 3.415 3.235 ;
      RECT 0.605 0.705 0.835 3.235 ;
  END
  PROPERTY CatenaDesignType "deviceLevel" ;
END SDFFSX1_LP

MACRO SDFFSX4_LP
  CLASS CORE ;
  ORIGIN 0 0 ;
  FOREIGN SDFFSX4_LP 0 0 ;
  SIZE 15.18 BY 4.14 ;
  SYMMETRY X Y ;
  SITE CoreSite ;
  PIN CK
    DIRECTION INPUT ;
    USE SIGNAL ;
    PORT
      LAYER met1 ;
        RECT 2.63 0.435 2.89 1.675 ;
    END
  END CK
  PIN D
    DIRECTION INPUT ;
    USE SIGNAL ;
    PORT
      LAYER met1 ;
        RECT 1.25 2.15 1.51 3.39 ;
    END
  END D
  PIN Q
    DIRECTION OUTPUT ;
    USE SIGNAL ;
    PORT
      LAYER met1 ;
        RECT 12.145 0.68 12.55 3.45 ;
        RECT 11.285 1.77 12.55 2 ;
        RECT 11.285 0.68 11.515 3.45 ;
    END
  END Q
  PIN QN
    DIRECTION OUTPUT ;
    USE SIGNAL ;
    PORT
      LAYER met1 ;
        RECT 13.865 0.675 14.39 3.45 ;
        RECT 13.005 1.77 14.39 2 ;
        RECT 13.005 0.68 13.235 3.45 ;
    END
  END QN
  PIN SE
    DIRECTION INPUT ;
    USE SIGNAL ;
    PORT
      LAYER met1 ;
        RECT 1.25 0.745 1.51 1.985 ;
    END
  END SE
  PIN SI
    DIRECTION INPUT ;
    USE SIGNAL ;
    PORT
      LAYER met1 ;
        RECT 2.63 1.82 2.89 3.06 ;
    END
  END SI
  PIN SN
    DIRECTION INPUT ;
    USE SIGNAL ;
    PORT
      LAYER met1 ;
        RECT 5.85 1.485 6.11 2.725 ;
    END
  END SN
  PIN VDD
    DIRECTION INPUT ;
    USE POWER ;
    SHAPE ABUTMENT ;
    NETEXPR "VDD VDD!" ;
    PORT
      LAYER met1 ;
        RECT 0 3.94 15.18 4.34 ;
    END
  END VDD
  PIN VSS
    DIRECTION INPUT ;
    USE GROUND ;
    SHAPE ABUTMENT ;
    NETEXPR "VSS VSS!" ;
    PORT
      LAYER met1 ;
        RECT 0 -0.2 15.18 0.2 ;
    END
  END VSS
  OBS
    LAYER met1 ;
      RECT 5.945 3.005 7.035 3.235 ;
      RECT 6.805 0.705 7.035 3.235 ;
      RECT 5.945 2.945 6.175 3.235 ;
      RECT 4.135 0.705 4.365 3.235 ;
      RECT 6.375 0.705 6.605 2.795 ;
      RECT 4.135 0.705 6.605 0.935 ;
      RECT 1.895 3.375 3.935 3.605 ;
      RECT 3.705 0.705 3.935 3.605 ;
      RECT 1.895 0.705 2.125 3.605 ;
      RECT 10.425 0.68 10.655 3.45 ;
      RECT 9.475 0.88 9.705 3.315 ;
      RECT 7.635 2.975 8.785 3.205 ;
      RECT 7.665 1.145 7.895 2.795 ;
      RECT 7.235 0.705 7.465 3.235 ;
      RECT 5.425 1.145 5.655 3.235 ;
      RECT 3.185 0.705 3.415 3.235 ;
      RECT 0.605 0.705 0.835 3.235 ;
  END
  PROPERTY CatenaDesignType "deviceLevel" ;
END SDFFSX4_LP

MACRO SDFFX1_LP
  CLASS CORE ;
  ORIGIN 0 0 ;
  FOREIGN SDFFX1_LP 0 0 ;
  SIZE 11.04 BY 4.14 ;
  SYMMETRY X Y ;
  SITE CoreSite ;
  PIN CK
    DIRECTION INPUT ;
    USE SIGNAL ;
    PORT
      LAYER met1 ;
        RECT 2.63 0.435 2.89 1.675 ;
    END
  END CK
  PIN D
    DIRECTION INPUT ;
    USE SIGNAL ;
    PORT
      LAYER met1 ;
        RECT 1.25 2.15 1.51 3.39 ;
    END
  END D
  PIN Q
    DIRECTION OUTPUT ;
    USE SIGNAL ;
    PORT
      LAYER met1 ;
        RECT 9.505 0.68 9.85 3.455 ;
    END
  END Q
  PIN QN
    DIRECTION OUTPUT ;
    USE SIGNAL ;
    PORT
      LAYER met1 ;
        RECT 10.365 0.675 10.71 3.45 ;
    END
  END QN
  PIN SE
    DIRECTION INPUT ;
    USE SIGNAL ;
    PORT
      LAYER met1 ;
        RECT 1.25 0.745 1.51 1.985 ;
    END
  END SE
  PIN SI
    DIRECTION INPUT ;
    USE SIGNAL ;
    PORT
      LAYER met1 ;
        RECT 2.63 1.82 2.89 3.06 ;
    END
  END SI
  PIN VDD
    DIRECTION INPUT ;
    USE POWER ;
    SHAPE ABUTMENT ;
    NETEXPR "VDD VDD!" ;
    PORT
      LAYER met1 ;
        RECT 0 3.94 11.04 4.34 ;
    END
  END VDD
  PIN VSS
    DIRECTION INPUT ;
    USE GROUND ;
    SHAPE ABUTMENT ;
    NETEXPR "VSS VSS!" ;
    PORT
      LAYER met1 ;
        RECT 0 -0.2 11.04 0.2 ;
    END
  END VSS
  OBS
    LAYER met1 ;
      RECT 4.135 3.375 6.175 3.605 ;
      RECT 5.945 2.475 6.175 3.605 ;
      RECT 4.135 0.705 4.365 3.605 ;
      RECT 1.895 3.375 3.935 3.605 ;
      RECT 3.705 0.705 3.935 3.605 ;
      RECT 1.895 0.705 2.125 3.605 ;
      RECT 9.045 0.88 9.275 3.53 ;
      RECT 8.185 0.68 8.415 3.53 ;
      RECT 7.235 1.145 7.465 2.795 ;
      RECT 6.805 0.705 7.035 3.235 ;
      RECT 6.375 0.705 6.605 3.235 ;
      RECT 5.425 0.705 5.655 3.235 ;
      RECT 3.185 0.705 3.415 3.235 ;
      RECT 0.605 0.705 0.835 3.235 ;
  END
  PROPERTY CatenaDesignType "deviceLevel" ;
END SDFFX1_LP

MACRO SDFFX4_LP
  CLASS CORE ;
  ORIGIN 0 0 ;
  FOREIGN SDFFX4_LP 0 0 ;
  SIZE 13.8 BY 4.14 ;
  SYMMETRY X Y ;
  SITE CoreSite ;
  PIN CK
    DIRECTION INPUT ;
    USE SIGNAL ;
    PORT
      LAYER met1 ;
        RECT 2.63 0.435 2.89 1.675 ;
    END
  END CK
  PIN D
    DIRECTION INPUT ;
    USE SIGNAL ;
    PORT
      LAYER met1 ;
        RECT 1.25 2.15 1.51 3.39 ;
    END
  END D
  PIN Q
    DIRECTION OUTPUT ;
    USE SIGNAL ;
    PORT
      LAYER met1 ;
        RECT 10.825 0.675 11.17 3.45 ;
        RECT 9.965 1.77 11.17 2 ;
        RECT 9.965 0.68 10.195 3.45 ;
    END
  END Q
  PIN QN
    DIRECTION OUTPUT ;
    USE SIGNAL ;
    PORT
      LAYER met1 ;
        RECT 12.545 0.675 13.01 3.45 ;
        RECT 11.685 1.77 13.01 2 ;
        RECT 11.685 0.68 11.915 3.45 ;
    END
  END QN
  PIN SE
    DIRECTION INPUT ;
    USE SIGNAL ;
    PORT
      LAYER met1 ;
        RECT 1.25 0.745 1.51 1.985 ;
    END
  END SE
  PIN SI
    DIRECTION INPUT ;
    USE SIGNAL ;
    PORT
      LAYER met1 ;
        RECT 2.63 1.82 2.89 3.06 ;
    END
  END SI
  PIN VDD
    DIRECTION INPUT ;
    USE POWER ;
    SHAPE ABUTMENT ;
    NETEXPR "VDD VDD!" ;
    PORT
      LAYER met1 ;
        RECT 0 3.94 13.8 4.34 ;
    END
  END VDD
  PIN VSS
    DIRECTION INPUT ;
    USE GROUND ;
    SHAPE ABUTMENT ;
    NETEXPR "VSS VSS!" ;
    PORT
      LAYER met1 ;
        RECT 0 -0.2 13.8 0.2 ;
    END
  END VSS
  OBS
    LAYER met1 ;
      RECT 4.135 3.375 6.175 3.605 ;
      RECT 5.945 2.475 6.175 3.605 ;
      RECT 4.135 0.705 4.365 3.605 ;
      RECT 1.895 3.375 3.935 3.605 ;
      RECT 3.705 0.705 3.935 3.605 ;
      RECT 1.895 0.705 2.125 3.605 ;
      RECT 9.105 0.68 9.335 3.45 ;
      RECT 8.155 0.88 8.385 3.315 ;
      RECT 7.235 1.145 7.465 2.795 ;
      RECT 6.805 0.705 7.035 3.235 ;
      RECT 6.375 0.705 6.605 3.235 ;
      RECT 5.425 0.705 5.655 3.235 ;
      RECT 3.185 0.705 3.415 3.235 ;
      RECT 0.605 0.705 0.835 3.235 ;
  END
  PROPERTY CatenaDesignType "deviceLevel" ;
END SDFFX4_LP

MACRO TBUFX1_LP
  CLASS CORE ;
  ORIGIN 0 0 ;
  FOREIGN TBUFX1_LP 0 0 ;
  SIZE 4.6 BY 4.14 ;
  SYMMETRY X Y ;
  SITE CoreSite ;
  PIN A
    DIRECTION INPUT ;
    USE SIGNAL ;
    PORT
      LAYER met1 ;
        RECT 2.17 1.665 2.43 2.905 ;
    END
  END A
  PIN OE
    DIRECTION INPUT ;
    USE SIGNAL ;
    PORT
      LAYER met1 ;
        RECT 1.25 1.85 1.51 3.09 ;
    END
  END OE
  PIN VDD
    DIRECTION INPUT ;
    USE POWER ;
    SHAPE ABUTMENT ;
    NETEXPR "VDD VDD!" ;
    PORT
      LAYER met1 ;
        RECT 0 3.94 4.6 4.34 ;
    END
  END VDD
  PIN VSS
    DIRECTION INPUT ;
    USE GROUND ;
    SHAPE ABUTMENT ;
    NETEXPR "VSS VSS!" ;
    PORT
      LAYER met1 ;
        RECT 0 -0.2 4.6 0.2 ;
    END
  END VSS
  PIN Y
    DIRECTION OUTPUT ;
    USE SIGNAL ;
    PORT
      LAYER met1 ;
        RECT 3.55 2.7 3.995 3.35 ;
        RECT 3.55 0.61 3.995 1.26 ;
        RECT 3.55 0.61 3.81 3.53 ;
    END
  END Y
  OBS
    LAYER met1 ;
      RECT 2.845 3.24 3.075 3.53 ;
      RECT 2.89 0.785 3.03 3.53 ;
      RECT 2.845 1.82 3.075 2.11 ;
      RECT 2.835 0.785 3.065 1.075 ;
      RECT 1.895 3.24 2.125 3.53 ;
      RECT 1.89 0.685 2.03 3.385 ;
      RECT 1.8 1.48 2.03 1.77 ;
      RECT 1.465 0.61 1.695 0.9 ;
      RECT 1.465 0.685 2.08 0.825 ;
      RECT 0.605 3.24 0.835 3.53 ;
      RECT 0.635 0.61 0.805 3.53 ;
      RECT 0.605 1.82 0.835 2.11 ;
      RECT 0.605 0.61 0.835 0.9 ;
  END
  PROPERTY CatenaDesignType "deviceLevel" ;
END TBUFX1_LP

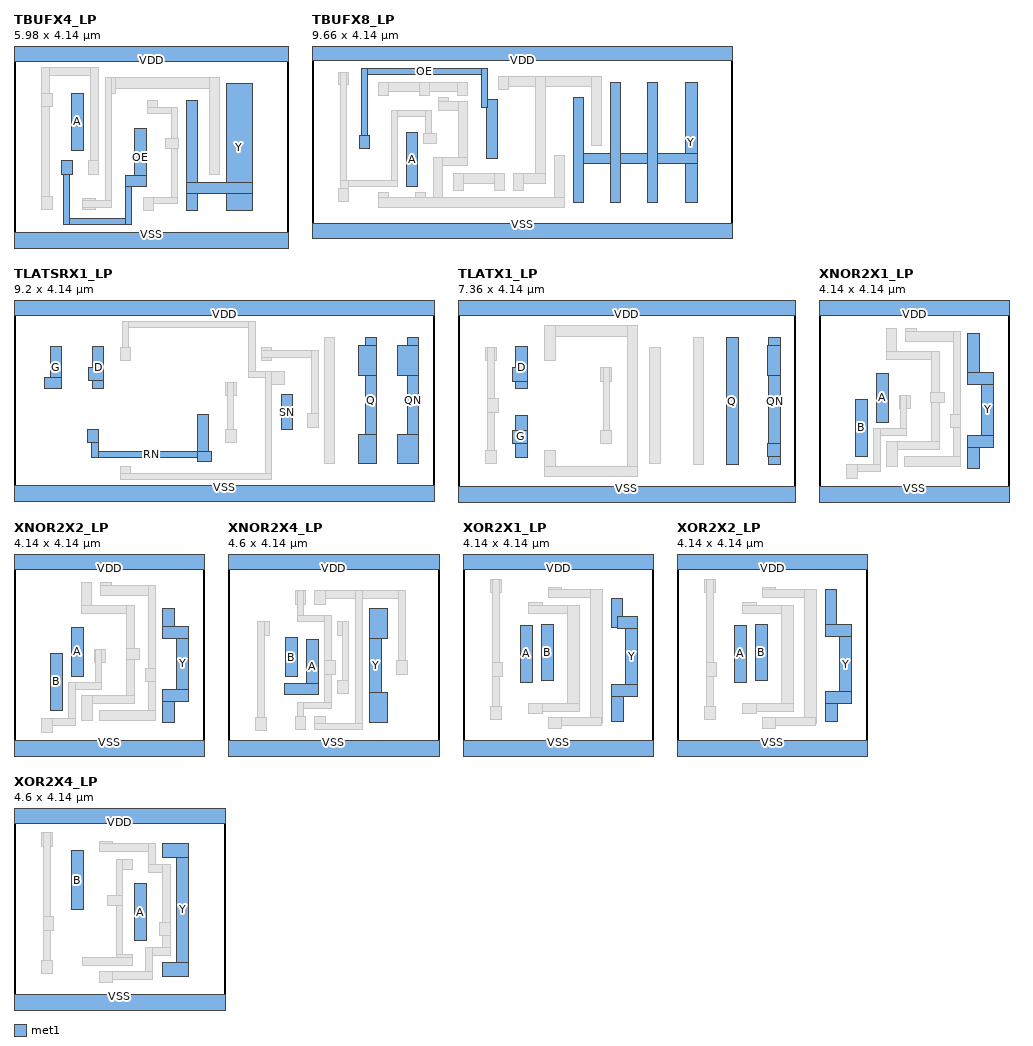
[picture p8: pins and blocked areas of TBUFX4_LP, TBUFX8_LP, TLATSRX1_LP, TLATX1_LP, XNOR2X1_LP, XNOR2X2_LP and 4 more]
MACRO TBUFX4_LP
  CLASS CORE ;
  ORIGIN 0 0 ;
  FOREIGN TBUFX4_LP 0 0 ;
  SIZE 5.98 BY 4.14 ;
  SYMMETRY X Y ;
  SITE CoreSite ;
  PIN A
    DIRECTION INPUT ;
    USE SIGNAL ;
    PORT
      LAYER met1 ;
        RECT 1.25 1.995 1.51 3.235 ;
    END
  END A
  PIN OE
    DIRECTION INPUT ;
    USE SIGNAL ;
    PORT
      LAYER met1 ;
        RECT 2.63 1.22 2.89 2.47 ;
        RECT 2.43 1.22 2.89 1.45 ;
        RECT 2.43 0.375 2.57 1.45 ;
        RECT 1.08 0.375 2.57 0.515 ;
        RECT 1.035 1.48 1.265 1.77 ;
        RECT 1.08 0.375 1.22 1.78 ;
    END
  END OE
  PIN VDD
    DIRECTION INPUT ;
    USE POWER ;
    SHAPE ABUTMENT ;
    NETEXPR "VDD VDD!" ;
    PORT
      LAYER met1 ;
        RECT 0 3.94 5.98 4.34 ;
    END
  END VDD
  PIN VSS
    DIRECTION INPUT ;
    USE GROUND ;
    SHAPE ABUTMENT ;
    NETEXPR "VSS VSS!" ;
    PORT
      LAYER met1 ;
        RECT 0 -0.2 5.98 0.2 ;
    END
  END VSS
  PIN Y
    DIRECTION OUTPUT ;
    USE SIGNAL ;
    PORT
      LAYER met1 ;
        RECT 4.625 0.68 5.19 3.45 ;
        RECT 3.765 1.06 5.19 1.29 ;
        RECT 3.765 0.68 3.995 3.09 ;
    END
  END Y
  OBS
    LAYER met1 ;
      RECT 1.985 3.345 4.485 3.575 ;
      RECT 4.255 1.46 4.485 3.575 ;
      RECT 1.985 3.24 2.215 3.575 ;
      RECT 1.985 0.755 2.125 3.575 ;
      RECT 1.495 0.71 1.785 0.94 ;
      RECT 1.495 0.755 2.125 0.895 ;
      RECT 2.905 2.8 3.135 3.09 ;
      RECT 2.905 2.8 3.565 2.94 ;
      RECT 3.425 0.83 3.565 2.94 ;
      RECT 3.305 2.03 3.595 2.26 ;
      RECT 2.815 0.83 3.565 0.97 ;
      RECT 2.815 0.68 3.045 0.97 ;
      RECT 0.605 3.63 1.845 3.8 ;
      RECT 1.675 1.48 1.845 3.8 ;
      RECT 0.605 0.705 0.775 3.8 ;
      RECT 0.605 2.945 0.835 3.235 ;
      RECT 1.615 1.48 1.845 1.77 ;
      RECT 0.605 0.705 0.835 0.995 ;
  END
  PROPERTY CatenaDesignType "deviceLevel" ;
END TBUFX4_LP

MACRO TBUFX8_LP
  CLASS CORE ;
  ORIGIN 0 0 ;
  FOREIGN TBUFX8_LP 0 0 ;
  SIZE 9.66 BY 4.14 ;
  SYMMETRY X Y ;
  SITE CoreSite ;
  PIN A
    DIRECTION INPUT ;
    USE SIGNAL ;
    PORT
      LAYER met1 ;
        RECT 2.17 1.04 2.43 2.28 ;
    END
  END A
  PIN OE
    DIRECTION INPUT ;
    USE SIGNAL ;
    PORT
      LAYER met1 ;
        RECT 4.01 1.68 4.27 3.04 ;
        RECT 1.135 3.615 4.03 3.755 ;
        RECT 3.89 2.855 4.03 3.755 ;
        RECT 1.09 1.92 1.32 2.21 ;
        RECT 1.135 1.92 1.275 3.755 ;
    END
  END OE
  PIN VDD
    DIRECTION INPUT ;
    USE POWER ;
    SHAPE ABUTMENT ;
    NETEXPR "VDD VDD!" ;
    PORT
      LAYER met1 ;
        RECT 0 3.94 9.66 4.34 ;
    END
  END VDD
  PIN VSS
    DIRECTION INPUT ;
    USE GROUND ;
    SHAPE ABUTMENT ;
    NETEXPR "VSS VSS!" ;
    PORT
      LAYER met1 ;
        RECT 0 -0.2 9.66 0.2 ;
    END
  END VSS
  PIN Y
    DIRECTION OUTPUT ;
    USE SIGNAL ;
    PORT
      LAYER met1 ;
        RECT 8.585 0.68 8.87 3.45 ;
        RECT 6.005 1.58 8.87 1.81 ;
        RECT 7.725 0.68 7.955 3.45 ;
        RECT 6.865 0.68 7.095 3.45 ;
        RECT 6.005 0.68 6.235 3.09 ;
    END
  END Y
  OBS
    LAYER met1 ;
      RECT 4.285 3.345 6.665 3.575 ;
      RECT 6.435 2 6.665 3.575 ;
      RECT 5.145 1.12 5.375 3.575 ;
      RECT 4.285 3.285 4.515 3.575 ;
      RECT 4.625 1.12 5.375 1.35 ;
      RECT 4.625 0.945 4.855 1.35 ;
      RECT 2.905 2.8 3.135 3.09 ;
      RECT 2.905 2.8 3.58 3 ;
      RECT 3.38 1.525 3.58 3 ;
      RECT 5.575 0.555 5.805 1.77 ;
      RECT 2.8 1.525 3.58 1.725 ;
      RECT 2.8 0.555 3 1.725 ;
      RECT 2.385 0.555 2.615 0.9 ;
      RECT 1.525 0.555 1.755 0.9 ;
      RECT 1.525 0.555 5.805 0.785 ;
      RECT 3.245 1.125 4.425 1.355 ;
      RECT 4.195 0.945 4.425 1.355 ;
      RECT 3.245 0.945 3.475 1.355 ;
      RECT 1.525 3.23 3.565 3.43 ;
      RECT 3.335 3.14 3.565 3.43 ;
      RECT 2.475 3.14 2.705 3.43 ;
      RECT 1.525 3.14 1.755 3.43 ;
      RECT 0.605 3.39 0.835 3.68 ;
      RECT 0.645 0.705 0.785 3.68 ;
      RECT 1.835 2.655 2.755 2.795 ;
      RECT 2.615 2.03 2.755 2.795 ;
      RECT 1.835 1.04 1.975 2.795 ;
      RECT 2.57 2.03 2.86 2.26 ;
      RECT 0.645 1.04 1.975 1.18 ;
      RECT 0.645 0.705 0.835 1.18 ;
      RECT 0.605 0.705 0.835 0.995 ;
  END
  PROPERTY CatenaDesignType "deviceLevel" ;
END TBUFX8_LP

MACRO TLATSRX1_LP
  CLASS CORE ;
  ORIGIN 0 0 ;
  FOREIGN TLATSRX1_LP 0 0 ;
  SIZE 9.2 BY 4.14 ;
  SYMMETRY X Y ;
  SITE CoreSite ;
  PIN D
    DIRECTION INPUT ;
    USE SIGNAL ;
    PORT
      LAYER met1 ;
        RECT 1.71 2.34 1.97 3.255 ;
        RECT 1.625 2.505 1.97 2.795 ;
    END
  END D
  PIN G
    DIRECTION INPUT ;
    USE SIGNAL ;
    PORT
      LAYER met1 ;
        RECT 0.79 2.34 1.05 3.255 ;
        RECT 0.665 2.34 1.05 2.57 ;
    END
  END G
  PIN Q
    DIRECTION OUTPUT ;
    USE SIGNAL ;
    PORT
      LAYER met1 ;
        RECT 7.69 0.68 7.95 3.45 ;
        RECT 7.55 2.62 7.95 3.27 ;
        RECT 7.55 0.68 7.95 1.33 ;
    END
  END Q
  PIN QN
    DIRECTION OUTPUT ;
    USE SIGNAL ;
    PORT
      LAYER met1 ;
        RECT 8.61 0.68 8.87 3.45 ;
        RECT 8.41 2.62 8.87 3.27 ;
        RECT 8.41 0.68 8.87 1.33 ;
    END
  END QN
  PIN RN
    DIRECTION INPUT ;
    USE SIGNAL ;
    PORT
      LAYER met1 ;
        RECT 1.7 0.815 4.32 0.955 ;
        RECT 4.01 0.725 4.32 0.955 ;
        RECT 4.01 0.725 4.27 1.77 ;
        RECT 1.61 1.145 1.84 1.435 ;
        RECT 1.7 0.815 1.84 1.435 ;
    END
  END RN
  PIN SN
    DIRECTION INPUT ;
    USE SIGNAL ;
    PORT
      LAYER met1 ;
        RECT 5.85 1.43 6.11 2.205 ;
    END
  END SN
  PIN VDD
    DIRECTION INPUT ;
    USE POWER ;
    SHAPE ABUTMENT ;
    NETEXPR "VDD VDD!" ;
    PORT
      LAYER met1 ;
        RECT 0 3.94 9.2 4.34 ;
    END
  END VDD
  PIN VSS
    DIRECTION INPUT ;
    USE GROUND ;
    SHAPE ABUTMENT ;
    NETEXPR "VSS VSS!" ;
    PORT
      LAYER met1 ;
        RECT 0 -0.2 9.2 0.2 ;
    END
  END VSS
  OBS
    LAYER met1 ;
      RECT 5.42 2.945 5.65 3.235 ;
      RECT 5.42 3.02 6.66 3.16 ;
      RECT 6.52 1.485 6.66 3.16 ;
      RECT 6.43 1.485 6.66 1.775 ;
      RECT 2.37 3.66 5.28 3.8 ;
      RECT 5.14 2.57 5.28 3.8 ;
      RECT 2.37 2.945 2.51 3.8 ;
      RECT 2.325 2.945 2.555 3.235 ;
      RECT 5.14 2.57 5.925 2.71 ;
      RECT 5.51 2.42 5.925 2.71 ;
      RECT 5.51 0.34 5.65 2.71 ;
      RECT 2.325 0.34 2.555 0.63 ;
      RECT 2.325 0.34 5.65 0.48 ;
      RECT 4.64 2.185 4.87 2.475 ;
      RECT 4.675 1.145 4.815 2.475 ;
      RECT 4.64 1.145 4.87 1.435 ;
      RECT 6.8 0.68 7.03 3.45 ;
  END
  PROPERTY CatenaDesignType "deviceLevel" ;
END TLATSRX1_LP

MACRO TLATX1_LP
  CLASS CORE ;
  ORIGIN 0 0 ;
  FOREIGN TLATX1_LP 0 0 ;
  SIZE 7.36 BY 4.14 ;
  SYMMETRY X Y ;
  SITE CoreSite ;
  PIN D
    DIRECTION INPUT ;
    USE SIGNAL ;
    PORT
      LAYER met1 ;
        RECT 1.25 2.34 1.51 3.255 ;
        RECT 1.195 2.505 1.51 2.795 ;
    END
  END D
  PIN G
    DIRECTION INPUT ;
    USE SIGNAL ;
    PORT
      LAYER met1 ;
        RECT 1.25 0.83 1.51 1.75 ;
        RECT 1.18 1.145 1.51 1.435 ;
    END
  END G
  PIN Q
    DIRECTION OUTPUT ;
    USE SIGNAL ;
    PORT
      LAYER met1 ;
        RECT 5.85 0.68 6.11 3.45 ;
    END
  END Q
  PIN QN
    DIRECTION OUTPUT ;
    USE SIGNAL ;
    PORT
      LAYER met1 ;
        RECT 6.77 0.68 7.03 3.45 ;
        RECT 6.735 2.62 7.03 3.27 ;
        RECT 6.735 0.86 7.03 1.15 ;
    END
  END QN
  PIN VDD
    DIRECTION INPUT ;
    USE POWER ;
    SHAPE ABUTMENT ;
    NETEXPR "VDD VDD!" ;
    PORT
      LAYER met1 ;
        RECT 0 3.94 7.36 4.34 ;
    END
  END VDD
  PIN VSS
    DIRECTION INPUT ;
    USE GROUND ;
    SHAPE ABUTMENT ;
    NETEXPR "VSS VSS!" ;
    PORT
      LAYER met1 ;
        RECT 0 -0.2 7.36 0.2 ;
    END
  END VSS
  OBS
    LAYER met1 ;
      RECT 1.895 3.485 3.92 3.715 ;
      RECT 3.69 0.415 3.92 3.715 ;
      RECT 1.895 2.945 2.125 3.715 ;
      RECT 1.895 0.415 2.125 0.995 ;
      RECT 1.895 0.415 3.92 0.645 ;
      RECT 3.105 2.505 3.335 2.795 ;
      RECT 3.16 1.145 3.3 2.795 ;
      RECT 3.105 1.145 3.335 1.435 ;
      RECT 0.605 2.945 0.835 3.235 ;
      RECT 0.65 0.705 0.79 3.235 ;
      RECT 0.65 1.825 0.88 2.115 ;
      RECT 0.605 0.705 0.835 0.995 ;
      RECT 5.125 0.68 5.355 3.45 ;
      RECT 4.175 0.705 4.405 3.235 ;
  END
  PROPERTY CatenaDesignType "deviceLevel" ;
END TLATX1_LP

MACRO XNOR2X1_LP
  CLASS CORE ;
  ORIGIN 0 0 ;
  FOREIGN XNOR2X1_LP 0 0 ;
  SIZE 4.14 BY 4.14 ;
  SYMMETRY X Y ;
  SITE CoreSite ;
  PIN A
    DIRECTION INPUT ;
    USE SIGNAL ;
    PORT
      LAYER met1 ;
        RECT 1.25 1.6 1.51 2.675 ;
    END
  END A
  PIN B
    DIRECTION INPUT ;
    USE SIGNAL ;
    PORT
      LAYER met1 ;
        RECT 0.79 0.87 1.05 2.11 ;
    END
  END B
  PIN VDD
    DIRECTION INPUT ;
    USE POWER ;
    SHAPE ABUTMENT ;
    NETEXPR "VDD VDD!" ;
    PORT
      LAYER met1 ;
        RECT 0 3.94 4.14 4.34 ;
    END
  END VDD
  PIN VSS
    DIRECTION INPUT ;
    USE GROUND ;
    SHAPE ABUTMENT ;
    NETEXPR "VSS VSS!" ;
    PORT
      LAYER met1 ;
        RECT 0 -0.2 4.14 0.2 ;
    END
  END VSS
  PIN Y
    DIRECTION OUTPUT ;
    USE SIGNAL ;
    PORT
      LAYER met1 ;
        RECT 3.23 2.44 3.81 2.7 ;
        RECT 3.55 1.055 3.81 2.7 ;
        RECT 3.23 1.055 3.81 1.315 ;
        RECT 3.23 2.44 3.49 3.545 ;
        RECT 3.23 0.61 3.49 1.315 ;
    END
  END Y
  OBS
    LAYER met1 ;
      RECT 1.895 3.365 2.125 3.655 ;
      RECT 1.895 3.365 3.09 3.595 ;
      RECT 2.92 0.64 3.09 3.595 ;
      RECT 2.86 1.49 3.09 1.78 ;
      RECT 1.865 0.64 3.09 0.87 ;
      RECT 1.465 2.975 1.695 3.655 ;
      RECT 1.465 2.975 2.615 3.145 ;
      RECT 2.445 1.01 2.615 3.145 ;
      RECT 2.44 2.03 2.73 2.26 ;
      RECT 1.47 1.01 2.615 1.18 ;
      RECT 1.47 0.64 1.7 1.18 ;
      RECT 1.76 1.905 1.99 2.195 ;
      RECT 1.77 1.32 1.91 2.195 ;
      RECT 1.19 1.32 1.91 1.46 ;
      RECT 1.19 0.54 1.33 1.46 ;
      RECT 0.605 0.54 1.33 0.68 ;
      RECT 0.605 0.39 0.835 0.68 ;
  END
  PROPERTY CatenaDesignType "deviceLevel" ;
END XNOR2X1_LP

MACRO XNOR2X2_LP
  CLASS CORE ;
  ORIGIN 0 0 ;
  FOREIGN XNOR2X2_LP 0 0 ;
  SIZE 4.14 BY 4.14 ;
  SYMMETRY X Y ;
  SITE CoreSite ;
  PIN A
    DIRECTION INPUT ;
    USE SIGNAL ;
    PORT
      LAYER met1 ;
        RECT 1.25 1.6 1.51 2.675 ;
    END
  END A
  PIN B
    DIRECTION INPUT ;
    USE SIGNAL ;
    PORT
      LAYER met1 ;
        RECT 0.79 0.87 1.05 2.11 ;
    END
  END B
  PIN VDD
    DIRECTION INPUT ;
    USE POWER ;
    SHAPE ABUTMENT ;
    NETEXPR "VDD VDD!" ;
    PORT
      LAYER met1 ;
        RECT 0 3.94 4.14 4.34 ;
    END
  END VDD
  PIN VSS
    DIRECTION INPUT ;
    USE GROUND ;
    SHAPE ABUTMENT ;
    NETEXPR "VSS VSS!" ;
    PORT
      LAYER met1 ;
        RECT 0 -0.2 4.14 0.2 ;
    END
  END VSS
  PIN Y
    DIRECTION OUTPUT ;
    USE SIGNAL ;
    PORT
      LAYER met1 ;
        RECT 3.23 2.44 3.81 2.7 ;
        RECT 3.55 1.055 3.81 2.7 ;
        RECT 3.23 1.055 3.81 1.315 ;
        RECT 3.23 2.44 3.49 3.09 ;
        RECT 3.23 0.61 3.49 1.315 ;
    END
  END Y
  OBS
    LAYER met1 ;
      RECT 1.895 3.365 2.125 3.655 ;
      RECT 1.895 3.365 3.09 3.595 ;
      RECT 2.92 0.64 3.09 3.595 ;
      RECT 2.86 1.49 3.09 1.78 ;
      RECT 1.865 0.64 3.09 0.87 ;
      RECT 1.465 2.975 1.695 3.655 ;
      RECT 1.465 2.975 2.615 3.145 ;
      RECT 2.445 1.01 2.615 3.145 ;
      RECT 2.445 1.975 2.735 2.205 ;
      RECT 1.47 1.01 2.615 1.18 ;
      RECT 1.47 0.64 1.7 1.18 ;
      RECT 1.76 1.905 1.99 2.195 ;
      RECT 1.77 1.32 1.91 2.195 ;
      RECT 1.19 1.32 1.91 1.46 ;
      RECT 1.19 0.54 1.33 1.46 ;
      RECT 0.605 0.54 1.33 0.68 ;
      RECT 0.605 0.39 0.835 0.68 ;
  END
  PROPERTY CatenaDesignType "deviceLevel" ;
END XNOR2X2_LP

MACRO XNOR2X4_LP
  CLASS CORE ;
  ORIGIN 0 0 ;
  FOREIGN XNOR2X4_LP 0 0 ;
  SIZE 4.6 BY 4.14 ;
  SYMMETRY X Y ;
  SITE CoreSite ;
  PIN A
    DIRECTION INPUT ;
    USE SIGNAL ;
    PORT
      LAYER met1 ;
        RECT 1.71 1.21 1.97 2.415 ;
        RECT 1.235 1.21 1.97 1.44 ;
    END
  END A
  PIN B
    DIRECTION INPUT ;
    USE SIGNAL ;
    PORT
      LAYER met1 ;
        RECT 1.25 1.6 1.51 2.45 ;
    END
  END B
  PIN VDD
    DIRECTION INPUT ;
    USE POWER ;
    SHAPE ABUTMENT ;
    NETEXPR "VDD VDD!" ;
    PORT
      LAYER met1 ;
        RECT 0 3.94 4.6 4.34 ;
    END
  END VDD
  PIN VSS
    DIRECTION INPUT ;
    USE GROUND ;
    SHAPE ABUTMENT ;
    NETEXPR "VSS VSS!" ;
    PORT
      LAYER met1 ;
        RECT 0 -0.2 4.6 0.2 ;
    END
  END VSS
  PIN Y
    DIRECTION OUTPUT ;
    USE SIGNAL ;
    PORT
      LAYER met1 ;
        RECT 3.09 2.44 3.475 3.09 ;
        RECT 3.09 0.61 3.475 1.26 ;
        RECT 3.09 0.61 3.35 3.09 ;
    END
  END Y
  OBS
    LAYER met1 ;
      RECT 1.895 3.3 3.875 3.47 ;
      RECT 3.705 1.65 3.875 3.47 ;
      RECT 2.78 0.44 2.92 3.47 ;
      RECT 1.895 3.18 2.125 3.47 ;
      RECT 3.675 1.65 3.905 1.94 ;
      RECT 1.895 0.44 2.125 0.73 ;
      RECT 1.895 0.44 2.92 0.58 ;
      RECT 2.395 2.505 2.625 2.795 ;
      RECT 2.485 1.225 2.625 2.795 ;
      RECT 2.395 1.225 2.625 1.515 ;
      RECT 1.465 3.18 1.695 3.47 ;
      RECT 1.51 2.8 1.65 3.47 ;
      RECT 1.51 2.8 2.25 2.94 ;
      RECT 2.11 0.895 2.25 2.94 ;
      RECT 2.11 1.655 2.34 1.945 ;
      RECT 1.51 0.895 2.25 1.035 ;
      RECT 1.51 0.44 1.65 1.035 ;
      RECT 1.465 0.44 1.695 0.73 ;
      RECT 0.635 2.505 0.915 2.795 ;
      RECT 0.635 0.425 0.805 2.795 ;
      RECT 0.605 0.425 0.835 0.715 ;
  END
  PROPERTY CatenaDesignType "deviceLevel" ;
END XNOR2X4_LP

MACRO XOR2X1_LP
  CLASS CORE ;
  ORIGIN 0 0 ;
  FOREIGN XOR2X1_LP 0 0 ;
  SIZE 4.14 BY 4.14 ;
  SYMMETRY X Y ;
  SITE CoreSite ;
  PIN A
    DIRECTION INPUT ;
    USE SIGNAL ;
    PORT
      LAYER met1 ;
        RECT 1.25 1.48 1.51 2.72 ;
    END
  END A
  PIN B
    DIRECTION INPUT ;
    USE SIGNAL ;
    PORT
      LAYER met1 ;
        RECT 1.71 1.505 1.97 2.745 ;
    END
  END B
  PIN VDD
    DIRECTION INPUT ;
    USE POWER ;
    SHAPE ABUTMENT ;
    NETEXPR "VDD VDD!" ;
    PORT
      LAYER met1 ;
        RECT 0 3.94 4.14 4.34 ;
    END
  END VDD
  PIN VSS
    DIRECTION INPUT ;
    USE GROUND ;
    SHAPE ABUTMENT ;
    NETEXPR "VSS VSS!" ;
    PORT
      LAYER met1 ;
        RECT 0 -0.2 4.14 0.2 ;
    END
  END VSS
  PIN Y
    DIRECTION OUTPUT ;
    USE SIGNAL ;
    PORT
      LAYER met1 ;
        RECT 3.55 1.175 3.81 2.91 ;
        RECT 3.36 2.65 3.81 2.91 ;
        RECT 3.23 1.175 3.81 1.435 ;
        RECT 3.23 0.615 3.49 1.435 ;
        RECT 3.245 2.66 3.475 3.31 ;
    END
  END Y
  OBS
    LAYER met1 ;
      RECT 1.865 3.32 2.155 3.55 ;
      RECT 1.865 3.32 3.03 3.49 ;
      RECT 2.77 0.575 3.03 3.49 ;
      RECT 1.865 0.535 3.025 0.705 ;
      RECT 1.865 0.475 2.155 0.705 ;
      RECT 1.435 2.98 1.725 3.21 ;
      RECT 1.435 2.98 2.535 3.15 ;
      RECT 2.275 0.845 2.535 3.15 ;
      RECT 1.435 0.845 2.535 1.015 ;
      RECT 1.435 0.785 1.725 1.015 ;
      RECT 0.605 3.435 0.835 3.725 ;
      RECT 0.635 0.655 0.805 3.725 ;
      RECT 0.635 1.61 0.865 1.9 ;
      RECT 0.605 0.655 0.835 0.945 ;
  END
  PROPERTY CatenaDesignType "deviceLevel" ;
END XOR2X1_LP

MACRO XOR2X2_LP
  CLASS CORE ;
  ORIGIN 0 0 ;
  FOREIGN XOR2X2_LP 0 0 ;
  SIZE 4.14 BY 4.14 ;
  SYMMETRY X Y ;
  SITE CoreSite ;
  PIN A
    DIRECTION INPUT ;
    USE SIGNAL ;
    PORT
      LAYER met1 ;
        RECT 1.25 1.48 1.51 2.72 ;
    END
  END A
  PIN B
    DIRECTION INPUT ;
    USE SIGNAL ;
    PORT
      LAYER met1 ;
        RECT 1.71 1.505 1.97 2.745 ;
    END
  END B
  PIN VDD
    DIRECTION INPUT ;
    USE POWER ;
    SHAPE ABUTMENT ;
    NETEXPR "VDD VDD!" ;
    PORT
      LAYER met1 ;
        RECT 0 3.94 4.14 4.34 ;
    END
  END VDD
  PIN VSS
    DIRECTION INPUT ;
    USE GROUND ;
    SHAPE ABUTMENT ;
    NETEXPR "VSS VSS!" ;
    PORT
      LAYER met1 ;
        RECT 0 -0.2 4.14 0.2 ;
    END
  END VSS
  PIN Y
    DIRECTION OUTPUT ;
    USE SIGNAL ;
    PORT
      LAYER met1 ;
        RECT 3.245 2.48 3.81 2.74 ;
        RECT 3.55 1.005 3.81 2.74 ;
        RECT 3.23 1.005 3.81 1.265 ;
        RECT 3.23 0.615 3.49 1.265 ;
        RECT 3.245 2.48 3.475 3.49 ;
    END
  END Y
  OBS
    LAYER met1 ;
      RECT 1.865 3.32 2.155 3.55 ;
      RECT 1.865 3.32 3.03 3.49 ;
      RECT 2.77 0.575 3.03 3.49 ;
      RECT 1.865 0.535 3.025 0.705 ;
      RECT 1.865 0.475 2.155 0.705 ;
      RECT 1.435 2.98 1.725 3.21 ;
      RECT 1.435 2.98 2.535 3.15 ;
      RECT 2.275 0.845 2.535 3.15 ;
      RECT 1.435 0.845 2.535 1.015 ;
      RECT 1.435 0.785 1.725 1.015 ;
      RECT 0.605 3.435 0.835 3.725 ;
      RECT 0.635 0.655 0.805 3.725 ;
      RECT 0.635 1.61 0.865 1.9 ;
      RECT 0.605 0.655 0.835 0.945 ;
  END
  PROPERTY CatenaDesignType "deviceLevel" ;
END XOR2X2_LP

MACRO XOR2X4_LP
  CLASS CORE ;
  ORIGIN 0 0 ;
  FOREIGN XOR2X4_LP 0 0 ;
  SIZE 4.6 BY 4.14 ;
  SYMMETRY X Y ;
  SITE CoreSite ;
  PIN A
    DIRECTION INPUT ;
    USE SIGNAL ;
    PORT
      LAYER met1 ;
        RECT 2.63 1.375 2.89 2.615 ;
    END
  END A
  PIN B
    DIRECTION INPUT ;
    USE SIGNAL ;
    PORT
      LAYER met1 ;
        RECT 1.25 2.055 1.51 3.345 ;
    END
  END B
  PIN VDD
    DIRECTION INPUT ;
    USE POWER ;
    SHAPE ABUTMENT ;
    NETEXPR "VDD VDD!" ;
    PORT
      LAYER met1 ;
        RECT 0 3.94 4.6 4.34 ;
    END
  END VDD
  PIN VSS
    DIRECTION INPUT ;
    USE GROUND ;
    SHAPE ABUTMENT ;
    NETEXPR "VSS VSS!" ;
    PORT
      LAYER met1 ;
        RECT 0 -0.2 4.6 0.2 ;
    END
  END VSS
  PIN Y
    DIRECTION OUTPUT ;
    USE SIGNAL ;
    PORT
      LAYER met1 ;
        RECT 3.23 3.2 3.81 3.495 ;
        RECT 3.55 0.605 3.81 3.495 ;
        RECT 3.23 0.605 3.81 0.9 ;
    END
  END Y
  OBS
    LAYER met1 ;
      RECT 1.865 3.32 2.155 3.55 ;
      RECT 1.865 3.32 3.09 3.49 ;
      RECT 2.92 2.875 3.09 3.49 ;
      RECT 2.92 2.875 3.41 3.045 ;
      RECT 3.24 1.065 3.41 3.045 ;
      RECT 3.18 1.485 3.41 1.775 ;
      RECT 2.855 1.065 3.41 1.235 ;
      RECT 2.855 0.535 3.025 1.235 ;
      RECT 1.865 0.535 3.025 0.705 ;
      RECT 1.865 0.475 2.155 0.705 ;
      RECT 2.23 2.92 2.585 3.15 ;
      RECT 2.23 0.845 2.37 3.15 ;
      RECT 2.04 2.145 2.37 2.375 ;
      RECT 2.23 0.845 2.585 1.075 ;
      RECT 1.485 0.845 2.585 1.015 ;
      RECT 0.605 3.44 0.835 3.73 ;
      RECT 0.635 0.655 0.805 3.73 ;
      RECT 0.635 1.61 0.865 1.9 ;
      RECT 0.605 0.655 0.835 0.945 ;
  END
  PROPERTY CatenaDesignType "deviceLevel" ;
END XOR2X4_LP

END LIBRARY
